VERSION 5.8 ;
BUSBITCHARS "[]" ;
DIVIDERCHAR "/" ;
UNITS
    DATABASE MICRONS 1000 ;
END UNITS

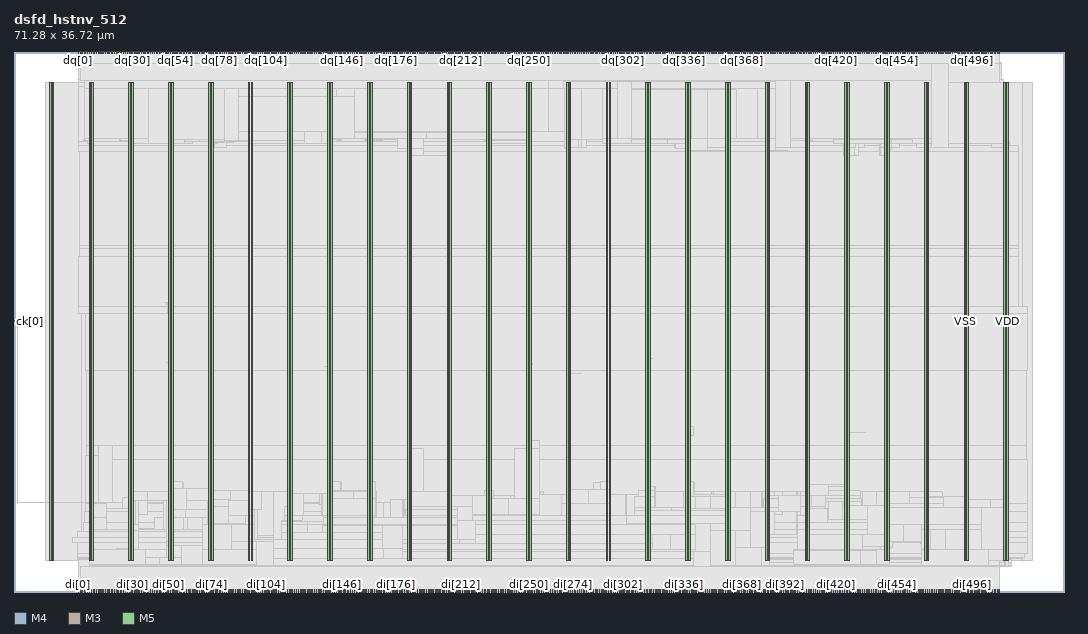
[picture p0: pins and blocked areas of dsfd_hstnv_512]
MACRO dsfd_hstnv_512
  FOREIGN dsfd_hstnv_512 0 0 ;
  CLASS BLOCK ;
  SIZE 71.28 BY 36.72 ;
  PIN ck[0]
    DIRECTION INPUT ;
    USE SIGNAL ;
    PORT
      LAYER M4 ;
        RECT  0 18.384 0.192 18.408 ;
    END
    PORT
      LAYER M4 ;
        RECT  0.156 18.384 0.275 18.408 ;
    END
  END ck[0]
  PIN di[0]
    DIRECTION INPUT ;
    USE SIGNAL ;
    PORT
      LAYER M3 ;
        RECT  4.356 0 4.374 0.144 ;
    END
  END di[0]
  PIN di[100]
    DIRECTION INPUT ;
    USE SIGNAL ;
    PORT
      LAYER M3 ;
        RECT  16.596 0 16.614 0.144 ;
    END
  END di[100]
  PIN di[101]
    DIRECTION INPUT ;
    USE SIGNAL ;
    PORT
      LAYER M5 ;
        RECT  16.704 0 16.728 0.192 ;
    END
  END di[101]
  PIN di[102]
    DIRECTION INPUT ;
    USE SIGNAL ;
    PORT
      LAYER M3 ;
        RECT  16.848 0 16.866 0.144 ;
    END
  END di[102]
  PIN di[103]
    DIRECTION INPUT ;
    USE SIGNAL ;
    PORT
      LAYER M5 ;
        RECT  16.992 0 17.016 0.192 ;
    END
  END di[103]
  PIN di[104]
    DIRECTION INPUT ;
    USE SIGNAL ;
    PORT
      LAYER M3 ;
        RECT  17.1 0 17.118 0.144 ;
    END
  END di[104]
  PIN di[105]
    DIRECTION INPUT ;
    USE SIGNAL ;
    PORT
      LAYER M5 ;
        RECT  17.232 0 17.256 0.192 ;
    END
  END di[105]
  PIN di[106]
    DIRECTION INPUT ;
    USE SIGNAL ;
    PORT
      LAYER M3 ;
        RECT  17.352 0 17.37 0.144 ;
    END
  END di[106]
  PIN di[107]
    DIRECTION INPUT ;
    USE SIGNAL ;
    PORT
      LAYER M5 ;
        RECT  17.472 0 17.496 0.192 ;
    END
  END di[107]
  PIN di[108]
    DIRECTION INPUT ;
    USE SIGNAL ;
    PORT
      LAYER M3 ;
        RECT  17.568 0 17.586 0.144 ;
    END
  END di[108]
  PIN di[109]
    DIRECTION INPUT ;
    USE SIGNAL ;
    PORT
      LAYER M5 ;
        RECT  17.712 0 17.736 0.192 ;
    END
  END di[109]
  PIN di[10]
    DIRECTION INPUT ;
    USE SIGNAL ;
    PORT
      LAYER M3 ;
        RECT  5.58 0 5.598 0.144 ;
    END
  END di[10]
  PIN di[110]
    DIRECTION INPUT ;
    USE SIGNAL ;
    PORT
      LAYER M3 ;
        RECT  17.82 0 17.838 0.144 ;
    END
  END di[110]
  PIN di[111]
    DIRECTION INPUT ;
    USE SIGNAL ;
    PORT
      LAYER M5 ;
        RECT  17.952 0 17.976 0.192 ;
    END
  END di[111]
  PIN di[112]
    DIRECTION INPUT ;
    USE SIGNAL ;
    PORT
      LAYER M3 ;
        RECT  18.072 0 18.09 0.144 ;
    END
  END di[112]
  PIN di[113]
    DIRECTION INPUT ;
    USE SIGNAL ;
    PORT
      LAYER M5 ;
        RECT  18.192 0 18.216 0.192 ;
    END
  END di[113]
  PIN di[114]
    DIRECTION INPUT ;
    USE SIGNAL ;
    PORT
      LAYER M3 ;
        RECT  18.324 0 18.342 0.144 ;
    END
  END di[114]
  PIN di[115]
    DIRECTION INPUT ;
    USE SIGNAL ;
    PORT
      LAYER M5 ;
        RECT  18.432 0 18.456 0.192 ;
    END
  END di[115]
  PIN di[116]
    DIRECTION INPUT ;
    USE SIGNAL ;
    PORT
      LAYER M3 ;
        RECT  18.576 0 18.594 0.144 ;
    END
  END di[116]
  PIN di[117]
    DIRECTION INPUT ;
    USE SIGNAL ;
    PORT
      LAYER M5 ;
        RECT  18.672 0 18.696 0.192 ;
    END
  END di[117]
  PIN di[118]
    DIRECTION INPUT ;
    USE SIGNAL ;
    PORT
      LAYER M3 ;
        RECT  18.792 0 18.81 0.144 ;
    END
  END di[118]
  PIN di[119]
    DIRECTION INPUT ;
    USE SIGNAL ;
    PORT
      LAYER M5 ;
        RECT  18.912 0 18.936 0.192 ;
    END
  END di[119]
  PIN di[11]
    DIRECTION INPUT ;
    USE SIGNAL ;
    PORT
      LAYER M5 ;
        RECT  5.712 0 5.736 0.192 ;
    END
  END di[11]
  PIN di[120]
    DIRECTION INPUT ;
    USE SIGNAL ;
    PORT
      LAYER M3 ;
        RECT  19.044 0 19.062 0.144 ;
    END
  END di[120]
  PIN di[121]
    DIRECTION INPUT ;
    USE SIGNAL ;
    PORT
      LAYER M5 ;
        RECT  19.152 0 19.176 0.192 ;
    END
  END di[121]
  PIN di[122]
    DIRECTION INPUT ;
    USE SIGNAL ;
    PORT
      LAYER M3 ;
        RECT  19.296 0 19.314 0.144 ;
    END
  END di[122]
  PIN di[123]
    DIRECTION INPUT ;
    USE SIGNAL ;
    PORT
      LAYER M5 ;
        RECT  19.44 0 19.464 0.192 ;
    END
  END di[123]
  PIN di[124]
    DIRECTION INPUT ;
    USE SIGNAL ;
    PORT
      LAYER M3 ;
        RECT  19.548 0 19.566 0.144 ;
    END
  END di[124]
  PIN di[125]
    DIRECTION INPUT ;
    USE SIGNAL ;
    PORT
      LAYER M5 ;
        RECT  19.68 0 19.704 0.192 ;
    END
  END di[125]
  PIN di[126]
    DIRECTION INPUT ;
    USE SIGNAL ;
    PORT
      LAYER M3 ;
        RECT  19.8 0 19.818 0.144 ;
    END
  END di[126]
  PIN di[127]
    DIRECTION INPUT ;
    USE SIGNAL ;
    PORT
      LAYER M5 ;
        RECT  19.92 0 19.944 0.192 ;
    END
  END di[127]
  PIN di[128]
    DIRECTION INPUT ;
    USE SIGNAL ;
    PORT
      LAYER M3 ;
        RECT  20.016 0 20.034 0.144 ;
    END
  END di[128]
  PIN di[129]
    DIRECTION INPUT ;
    USE SIGNAL ;
    PORT
      LAYER M5 ;
        RECT  20.16 0 20.184 0.192 ;
    END
  END di[129]
  PIN di[12]
    DIRECTION INPUT ;
    USE SIGNAL ;
    PORT
      LAYER M3 ;
        RECT  5.832 0 5.85 0.144 ;
    END
  END di[12]
  PIN di[130]
    DIRECTION INPUT ;
    USE SIGNAL ;
    PORT
      LAYER M3 ;
        RECT  20.268 0 20.286 0.144 ;
    END
  END di[130]
  PIN di[131]
    DIRECTION INPUT ;
    USE SIGNAL ;
    PORT
      LAYER M5 ;
        RECT  20.4 0 20.424 0.192 ;
    END
  END di[131]
  PIN di[132]
    DIRECTION INPUT ;
    USE SIGNAL ;
    PORT
      LAYER M3 ;
        RECT  20.52 0 20.538 0.144 ;
    END
  END di[132]
  PIN di[133]
    DIRECTION INPUT ;
    USE SIGNAL ;
    PORT
      LAYER M5 ;
        RECT  20.64 0 20.664 0.192 ;
    END
  END di[133]
  PIN di[134]
    DIRECTION INPUT ;
    USE SIGNAL ;
    PORT
      LAYER M3 ;
        RECT  20.772 0 20.79 0.144 ;
    END
  END di[134]
  PIN di[135]
    DIRECTION INPUT ;
    USE SIGNAL ;
    PORT
      LAYER M5 ;
        RECT  20.88 0 20.904 0.192 ;
    END
  END di[135]
  PIN di[136]
    DIRECTION INPUT ;
    USE SIGNAL ;
    PORT
      LAYER M3 ;
        RECT  21.024 0 21.042 0.144 ;
    END
  END di[136]
  PIN di[137]
    DIRECTION INPUT ;
    USE SIGNAL ;
    PORT
      LAYER M5 ;
        RECT  21.12 0 21.144 0.192 ;
    END
  END di[137]
  PIN di[138]
    DIRECTION INPUT ;
    USE SIGNAL ;
    PORT
      LAYER M3 ;
        RECT  21.24 0 21.258 0.144 ;
    END
  END di[138]
  PIN di[139]
    DIRECTION INPUT ;
    USE SIGNAL ;
    PORT
      LAYER M5 ;
        RECT  21.36 0 21.384 0.192 ;
    END
  END di[139]
  PIN di[13]
    DIRECTION INPUT ;
    USE SIGNAL ;
    PORT
      LAYER M5 ;
        RECT  5.952 0 5.976 0.192 ;
    END
  END di[13]
  PIN di[140]
    DIRECTION INPUT ;
    USE SIGNAL ;
    PORT
      LAYER M3 ;
        RECT  21.492 0 21.51 0.144 ;
    END
  END di[140]
  PIN di[141]
    DIRECTION INPUT ;
    USE SIGNAL ;
    PORT
      LAYER M5 ;
        RECT  21.6 0 21.624 0.192 ;
    END
  END di[141]
  PIN di[142]
    DIRECTION INPUT ;
    USE SIGNAL ;
    PORT
      LAYER M3 ;
        RECT  21.744 0 21.762 0.144 ;
    END
  END di[142]
  PIN di[143]
    DIRECTION INPUT ;
    USE SIGNAL ;
    PORT
      LAYER M5 ;
        RECT  21.888 0 21.912 0.192 ;
    END
  END di[143]
  PIN di[144]
    DIRECTION INPUT ;
    USE SIGNAL ;
    PORT
      LAYER M3 ;
        RECT  21.996 0 22.014 0.144 ;
    END
  END di[144]
  PIN di[145]
    DIRECTION INPUT ;
    USE SIGNAL ;
    PORT
      LAYER M5 ;
        RECT  22.128 0 22.152 0.192 ;
    END
  END di[145]
  PIN di[146]
    DIRECTION INPUT ;
    USE SIGNAL ;
    PORT
      LAYER M3 ;
        RECT  22.248 0 22.266 0.144 ;
    END
  END di[146]
  PIN di[147]
    DIRECTION INPUT ;
    USE SIGNAL ;
    PORT
      LAYER M5 ;
        RECT  22.368 0 22.392 0.192 ;
    END
  END di[147]
  PIN di[148]
    DIRECTION INPUT ;
    USE SIGNAL ;
    PORT
      LAYER M3 ;
        RECT  22.464 0 22.482 0.144 ;
    END
  END di[148]
  PIN di[149]
    DIRECTION INPUT ;
    USE SIGNAL ;
    PORT
      LAYER M5 ;
        RECT  22.608 0 22.632 0.192 ;
    END
  END di[149]
  PIN di[14]
    DIRECTION INPUT ;
    USE SIGNAL ;
    PORT
      LAYER M3 ;
        RECT  6.084 0 6.102 0.144 ;
    END
  END di[14]
  PIN di[150]
    DIRECTION INPUT ;
    USE SIGNAL ;
    PORT
      LAYER M3 ;
        RECT  22.716 0 22.734 0.144 ;
    END
  END di[150]
  PIN di[151]
    DIRECTION INPUT ;
    USE SIGNAL ;
    PORT
      LAYER M5 ;
        RECT  22.848 0 22.872 0.192 ;
    END
  END di[151]
  PIN di[152]
    DIRECTION INPUT ;
    USE SIGNAL ;
    PORT
      LAYER M3 ;
        RECT  22.968 0 22.986 0.144 ;
    END
  END di[152]
  PIN di[153]
    DIRECTION INPUT ;
    USE SIGNAL ;
    PORT
      LAYER M5 ;
        RECT  23.088 0 23.112 0.192 ;
    END
  END di[153]
  PIN di[154]
    DIRECTION INPUT ;
    USE SIGNAL ;
    PORT
      LAYER M3 ;
        RECT  23.22 0 23.238 0.144 ;
    END
  END di[154]
  PIN di[155]
    DIRECTION INPUT ;
    USE SIGNAL ;
    PORT
      LAYER M5 ;
        RECT  23.328 0 23.352 0.192 ;
    END
  END di[155]
  PIN di[156]
    DIRECTION INPUT ;
    USE SIGNAL ;
    PORT
      LAYER M3 ;
        RECT  23.472 0 23.49 0.144 ;
    END
  END di[156]
  PIN di[157]
    DIRECTION INPUT ;
    USE SIGNAL ;
    PORT
      LAYER M5 ;
        RECT  23.568 0 23.592 0.192 ;
    END
  END di[157]
  PIN di[158]
    DIRECTION INPUT ;
    USE SIGNAL ;
    PORT
      LAYER M3 ;
        RECT  23.688 0 23.706 0.144 ;
    END
  END di[158]
  PIN di[159]
    DIRECTION INPUT ;
    USE SIGNAL ;
    PORT
      LAYER M5 ;
        RECT  23.808 0 23.832 0.192 ;
    END
  END di[159]
  PIN di[15]
    DIRECTION INPUT ;
    USE SIGNAL ;
    PORT
      LAYER M5 ;
        RECT  6.192 0 6.216 0.192 ;
    END
  END di[15]
  PIN di[160]
    DIRECTION INPUT ;
    USE SIGNAL ;
    PORT
      LAYER M3 ;
        RECT  23.94 0 23.958 0.144 ;
    END
  END di[160]
  PIN di[161]
    DIRECTION INPUT ;
    USE SIGNAL ;
    PORT
      LAYER M5 ;
        RECT  24.048 0 24.072 0.192 ;
    END
  END di[161]
  PIN di[162]
    DIRECTION INPUT ;
    USE SIGNAL ;
    PORT
      LAYER M3 ;
        RECT  24.192 0 24.21 0.144 ;
    END
  END di[162]
  PIN di[163]
    DIRECTION INPUT ;
    USE SIGNAL ;
    PORT
      LAYER M5 ;
        RECT  24.288 0 24.312 0.192 ;
    END
  END di[163]
  PIN di[164]
    DIRECTION INPUT ;
    USE SIGNAL ;
    PORT
      LAYER M3 ;
        RECT  24.444 0 24.462 0.144 ;
    END
  END di[164]
  PIN di[165]
    DIRECTION INPUT ;
    USE SIGNAL ;
    PORT
      LAYER M5 ;
        RECT  24.576 0 24.6 0.192 ;
    END
  END di[165]
  PIN di[166]
    DIRECTION INPUT ;
    USE SIGNAL ;
    PORT
      LAYER M3 ;
        RECT  24.696 0 24.714 0.144 ;
    END
  END di[166]
  PIN di[167]
    DIRECTION INPUT ;
    USE SIGNAL ;
    PORT
      LAYER M5 ;
        RECT  24.816 0 24.84 0.192 ;
    END
  END di[167]
  PIN di[168]
    DIRECTION INPUT ;
    USE SIGNAL ;
    PORT
      LAYER M3 ;
        RECT  24.912 0 24.93 0.144 ;
    END
  END di[168]
  PIN di[169]
    DIRECTION INPUT ;
    USE SIGNAL ;
    PORT
      LAYER M5 ;
        RECT  25.056 0 25.08 0.192 ;
    END
  END di[169]
  PIN di[16]
    DIRECTION INPUT ;
    USE SIGNAL ;
    PORT
      LAYER M3 ;
        RECT  6.336 0 6.354 0.144 ;
    END
  END di[16]
  PIN di[170]
    DIRECTION INPUT ;
    USE SIGNAL ;
    PORT
      LAYER M3 ;
        RECT  25.164 0 25.182 0.144 ;
    END
  END di[170]
  PIN di[171]
    DIRECTION INPUT ;
    USE SIGNAL ;
    PORT
      LAYER M5 ;
        RECT  25.296 0 25.32 0.192 ;
    END
  END di[171]
  PIN di[172]
    DIRECTION INPUT ;
    USE SIGNAL ;
    PORT
      LAYER M3 ;
        RECT  25.416 0 25.434 0.144 ;
    END
  END di[172]
  PIN di[173]
    DIRECTION INPUT ;
    USE SIGNAL ;
    PORT
      LAYER M5 ;
        RECT  25.536 0 25.56 0.192 ;
    END
  END di[173]
  PIN di[174]
    DIRECTION INPUT ;
    USE SIGNAL ;
    PORT
      LAYER M3 ;
        RECT  25.668 0 25.686 0.144 ;
    END
  END di[174]
  PIN di[175]
    DIRECTION INPUT ;
    USE SIGNAL ;
    PORT
      LAYER M5 ;
        RECT  25.776 0 25.8 0.192 ;
    END
  END di[175]
  PIN di[176]
    DIRECTION INPUT ;
    USE SIGNAL ;
    PORT
      LAYER M3 ;
        RECT  25.92 0 25.938 0.144 ;
    END
  END di[176]
  PIN di[177]
    DIRECTION INPUT ;
    USE SIGNAL ;
    PORT
      LAYER M5 ;
        RECT  26.016 0 26.04 0.192 ;
    END
  END di[177]
  PIN di[178]
    DIRECTION INPUT ;
    USE SIGNAL ;
    PORT
      LAYER M3 ;
        RECT  26.136 0 26.154 0.144 ;
    END
  END di[178]
  PIN di[179]
    DIRECTION INPUT ;
    USE SIGNAL ;
    PORT
      LAYER M5 ;
        RECT  26.256 0 26.28 0.192 ;
    END
  END di[179]
  PIN di[17]
    DIRECTION INPUT ;
    USE SIGNAL ;
    PORT
      LAYER M5 ;
        RECT  6.432 0 6.456 0.192 ;
    END
  END di[17]
  PIN di[180]
    DIRECTION INPUT ;
    USE SIGNAL ;
    PORT
      LAYER M3 ;
        RECT  26.388 0 26.406 0.144 ;
    END
  END di[180]
  PIN di[181]
    DIRECTION INPUT ;
    USE SIGNAL ;
    PORT
      LAYER M5 ;
        RECT  26.496 0 26.52 0.192 ;
    END
  END di[181]
  PIN di[182]
    DIRECTION INPUT ;
    USE SIGNAL ;
    PORT
      LAYER M3 ;
        RECT  26.64 0 26.658 0.144 ;
    END
  END di[182]
  PIN di[183]
    DIRECTION INPUT ;
    USE SIGNAL ;
    PORT
      LAYER M5 ;
        RECT  26.736 0 26.76 0.192 ;
    END
  END di[183]
  PIN di[184]
    DIRECTION INPUT ;
    USE SIGNAL ;
    PORT
      LAYER M3 ;
        RECT  26.892 0 26.91 0.144 ;
    END
  END di[184]
  PIN di[185]
    DIRECTION INPUT ;
    USE SIGNAL ;
    PORT
      LAYER M5 ;
        RECT  27.024 0 27.048 0.192 ;
    END
  END di[185]
  PIN di[186]
    DIRECTION INPUT ;
    USE SIGNAL ;
    PORT
      LAYER M3 ;
        RECT  27.144 0 27.162 0.144 ;
    END
  END di[186]
  PIN di[187]
    DIRECTION INPUT ;
    USE SIGNAL ;
    PORT
      LAYER M5 ;
        RECT  27.264 0 27.288 0.192 ;
    END
  END di[187]
  PIN di[188]
    DIRECTION INPUT ;
    USE SIGNAL ;
    PORT
      LAYER M3 ;
        RECT  27.36 0 27.378 0.144 ;
    END
  END di[188]
  PIN di[189]
    DIRECTION INPUT ;
    USE SIGNAL ;
    PORT
      LAYER M5 ;
        RECT  27.504 0 27.528 0.192 ;
    END
  END di[189]
  PIN di[18]
    DIRECTION INPUT ;
    USE SIGNAL ;
    PORT
      LAYER M3 ;
        RECT  6.588 0 6.606 0.144 ;
    END
  END di[18]
  PIN di[190]
    DIRECTION INPUT ;
    USE SIGNAL ;
    PORT
      LAYER M3 ;
        RECT  27.612 0 27.63 0.144 ;
    END
  END di[190]
  PIN di[191]
    DIRECTION INPUT ;
    USE SIGNAL ;
    PORT
      LAYER M5 ;
        RECT  27.744 0 27.768 0.192 ;
    END
  END di[191]
  PIN di[192]
    DIRECTION INPUT ;
    USE SIGNAL ;
    PORT
      LAYER M3 ;
        RECT  27.864 0 27.882 0.144 ;
    END
  END di[192]
  PIN di[193]
    DIRECTION INPUT ;
    USE SIGNAL ;
    PORT
      LAYER M5 ;
        RECT  27.984 0 28.008 0.192 ;
    END
  END di[193]
  PIN di[194]
    DIRECTION INPUT ;
    USE SIGNAL ;
    PORT
      LAYER M3 ;
        RECT  28.116 0 28.134 0.144 ;
    END
  END di[194]
  PIN di[195]
    DIRECTION INPUT ;
    USE SIGNAL ;
    PORT
      LAYER M5 ;
        RECT  28.224 0 28.248 0.192 ;
    END
  END di[195]
  PIN di[196]
    DIRECTION INPUT ;
    USE SIGNAL ;
    PORT
      LAYER M3 ;
        RECT  28.368 0 28.386 0.144 ;
    END
  END di[196]
  PIN di[197]
    DIRECTION INPUT ;
    USE SIGNAL ;
    PORT
      LAYER M5 ;
        RECT  28.464 0 28.488 0.192 ;
    END
  END di[197]
  PIN di[198]
    DIRECTION INPUT ;
    USE SIGNAL ;
    PORT
      LAYER M3 ;
        RECT  28.584 0 28.602 0.144 ;
    END
  END di[198]
  PIN di[199]
    DIRECTION INPUT ;
    USE SIGNAL ;
    PORT
      LAYER M5 ;
        RECT  28.704 0 28.728 0.192 ;
    END
  END di[199]
  PIN di[19]
    DIRECTION INPUT ;
    USE SIGNAL ;
    PORT
      LAYER M5 ;
        RECT  6.672 0 6.696 0.192 ;
    END
  END di[19]
  PIN di[1]
    DIRECTION INPUT ;
    USE SIGNAL ;
    PORT
      LAYER M5 ;
        RECT  4.512 0 4.536 0.192 ;
    END
  END di[1]
  PIN di[200]
    DIRECTION INPUT ;
    USE SIGNAL ;
    PORT
      LAYER M3 ;
        RECT  28.836 0 28.854 0.144 ;
    END
  END di[200]
  PIN di[201]
    DIRECTION INPUT ;
    USE SIGNAL ;
    PORT
      LAYER M5 ;
        RECT  28.944 0 28.968 0.192 ;
    END
  END di[201]
  PIN di[202]
    DIRECTION INPUT ;
    USE SIGNAL ;
    PORT
      LAYER M3 ;
        RECT  29.088 0 29.106 0.144 ;
    END
  END di[202]
  PIN di[203]
    DIRECTION INPUT ;
    USE SIGNAL ;
    PORT
      LAYER M5 ;
        RECT  29.184 0 29.208 0.192 ;
    END
  END di[203]
  PIN di[204]
    DIRECTION INPUT ;
    USE SIGNAL ;
    PORT
      LAYER M3 ;
        RECT  29.34 0 29.358 0.144 ;
    END
  END di[204]
  PIN di[205]
    DIRECTION INPUT ;
    USE SIGNAL ;
    PORT
      LAYER M5 ;
        RECT  29.472 0 29.496 0.192 ;
    END
  END di[205]
  PIN di[206]
    DIRECTION INPUT ;
    USE SIGNAL ;
    PORT
      LAYER M3 ;
        RECT  29.592 0 29.61 0.144 ;
    END
  END di[206]
  PIN di[207]
    DIRECTION INPUT ;
    USE SIGNAL ;
    PORT
      LAYER M5 ;
        RECT  29.712 0 29.736 0.192 ;
    END
  END di[207]
  PIN di[208]
    DIRECTION INPUT ;
    USE SIGNAL ;
    PORT
      LAYER M3 ;
        RECT  29.808 0 29.826 0.144 ;
    END
  END di[208]
  PIN di[209]
    DIRECTION INPUT ;
    USE SIGNAL ;
    PORT
      LAYER M5 ;
        RECT  29.952 0 29.976 0.192 ;
    END
  END di[209]
  PIN di[20]
    DIRECTION INPUT ;
    USE SIGNAL ;
    PORT
      LAYER M3 ;
        RECT  6.804 0 6.822 0.144 ;
    END
  END di[20]
  PIN di[210]
    DIRECTION INPUT ;
    USE SIGNAL ;
    PORT
      LAYER M3 ;
        RECT  30.06 0 30.078 0.144 ;
    END
  END di[210]
  PIN di[211]
    DIRECTION INPUT ;
    USE SIGNAL ;
    PORT
      LAYER M5 ;
        RECT  30.192 0 30.216 0.192 ;
    END
  END di[211]
  PIN di[212]
    DIRECTION INPUT ;
    USE SIGNAL ;
    PORT
      LAYER M3 ;
        RECT  30.312 0 30.33 0.144 ;
    END
  END di[212]
  PIN di[213]
    DIRECTION INPUT ;
    USE SIGNAL ;
    PORT
      LAYER M5 ;
        RECT  30.432 0 30.456 0.192 ;
    END
  END di[213]
  PIN di[214]
    DIRECTION INPUT ;
    USE SIGNAL ;
    PORT
      LAYER M3 ;
        RECT  30.564 0 30.582 0.144 ;
    END
  END di[214]
  PIN di[215]
    DIRECTION INPUT ;
    USE SIGNAL ;
    PORT
      LAYER M5 ;
        RECT  30.672 0 30.696 0.192 ;
    END
  END di[215]
  PIN di[216]
    DIRECTION INPUT ;
    USE SIGNAL ;
    PORT
      LAYER M3 ;
        RECT  30.816 0 30.834 0.144 ;
    END
  END di[216]
  PIN di[217]
    DIRECTION INPUT ;
    USE SIGNAL ;
    PORT
      LAYER M5 ;
        RECT  30.912 0 30.936 0.192 ;
    END
  END di[217]
  PIN di[218]
    DIRECTION INPUT ;
    USE SIGNAL ;
    PORT
      LAYER M3 ;
        RECT  31.032 0 31.05 0.144 ;
    END
  END di[218]
  PIN di[219]
    DIRECTION INPUT ;
    USE SIGNAL ;
    PORT
      LAYER M5 ;
        RECT  31.152 0 31.176 0.192 ;
    END
  END di[219]
  PIN di[21]
    DIRECTION INPUT ;
    USE SIGNAL ;
    PORT
      LAYER M5 ;
        RECT  6.96 0 6.984 0.192 ;
    END
  END di[21]
  PIN di[220]
    DIRECTION INPUT ;
    USE SIGNAL ;
    PORT
      LAYER M3 ;
        RECT  31.284 0 31.302 0.144 ;
    END
  END di[220]
  PIN di[221]
    DIRECTION INPUT ;
    USE SIGNAL ;
    PORT
      LAYER M5 ;
        RECT  31.392 0 31.416 0.192 ;
    END
  END di[221]
  PIN di[222]
    DIRECTION INPUT ;
    USE SIGNAL ;
    PORT
      LAYER M3 ;
        RECT  31.536 0 31.554 0.144 ;
    END
  END di[222]
  PIN di[223]
    DIRECTION INPUT ;
    USE SIGNAL ;
    PORT
      LAYER M5 ;
        RECT  31.632 0 31.656 0.192 ;
    END
  END di[223]
  PIN di[224]
    DIRECTION INPUT ;
    USE SIGNAL ;
    PORT
      LAYER M3 ;
        RECT  31.788 0 31.806 0.144 ;
    END
  END di[224]
  PIN di[225]
    DIRECTION INPUT ;
    USE SIGNAL ;
    PORT
      LAYER M5 ;
        RECT  31.92 0 31.944 0.192 ;
    END
  END di[225]
  PIN di[226]
    DIRECTION INPUT ;
    USE SIGNAL ;
    PORT
      LAYER M3 ;
        RECT  32.004 0 32.022 0.144 ;
    END
  END di[226]
  PIN di[227]
    DIRECTION INPUT ;
    USE SIGNAL ;
    PORT
      LAYER M5 ;
        RECT  32.16 0 32.184 0.192 ;
    END
  END di[227]
  PIN di[228]
    DIRECTION INPUT ;
    USE SIGNAL ;
    PORT
      LAYER M3 ;
        RECT  32.256 0 32.274 0.144 ;
    END
  END di[228]
  PIN di[229]
    DIRECTION INPUT ;
    USE SIGNAL ;
    PORT
      LAYER M5 ;
        RECT  32.4 0 32.424 0.192 ;
    END
  END di[229]
  PIN di[22]
    DIRECTION INPUT ;
    USE SIGNAL ;
    PORT
      LAYER M3 ;
        RECT  7.056 0 7.074 0.144 ;
    END
  END di[22]
  PIN di[230]
    DIRECTION INPUT ;
    USE SIGNAL ;
    PORT
      LAYER M3 ;
        RECT  32.508 0 32.526 0.144 ;
    END
  END di[230]
  PIN di[231]
    DIRECTION INPUT ;
    USE SIGNAL ;
    PORT
      LAYER M5 ;
        RECT  32.64 0 32.664 0.192 ;
    END
  END di[231]
  PIN di[232]
    DIRECTION INPUT ;
    USE SIGNAL ;
    PORT
      LAYER M3 ;
        RECT  32.76 0 32.778 0.144 ;
    END
  END di[232]
  PIN di[233]
    DIRECTION INPUT ;
    USE SIGNAL ;
    PORT
      LAYER M5 ;
        RECT  32.88 0 32.904 0.192 ;
    END
  END di[233]
  PIN di[234]
    DIRECTION INPUT ;
    USE SIGNAL ;
    PORT
      LAYER M3 ;
        RECT  33.012 0 33.03 0.144 ;
    END
  END di[234]
  PIN di[235]
    DIRECTION INPUT ;
    USE SIGNAL ;
    PORT
      LAYER M5 ;
        RECT  33.12 0 33.144 0.192 ;
    END
  END di[235]
  PIN di[236]
    DIRECTION INPUT ;
    USE SIGNAL ;
    PORT
      LAYER M3 ;
        RECT  33.228 0 33.246 0.144 ;
    END
  END di[236]
  PIN di[237]
    DIRECTION INPUT ;
    USE SIGNAL ;
    PORT
      LAYER M5 ;
        RECT  33.36 0 33.384 0.192 ;
    END
  END di[237]
  PIN di[238]
    DIRECTION INPUT ;
    USE SIGNAL ;
    PORT
      LAYER M3 ;
        RECT  33.48 0 33.498 0.144 ;
    END
  END di[238]
  PIN di[239]
    DIRECTION INPUT ;
    USE SIGNAL ;
    PORT
      LAYER M5 ;
        RECT  33.6 0 33.624 0.192 ;
    END
  END di[239]
  PIN di[23]
    DIRECTION INPUT ;
    USE SIGNAL ;
    PORT
      LAYER M5 ;
        RECT  7.2 0 7.224 0.192 ;
    END
  END di[23]
  PIN di[240]
    DIRECTION INPUT ;
    USE SIGNAL ;
    PORT
      LAYER M3 ;
        RECT  33.732 0 33.75 0.144 ;
    END
  END di[240]
  PIN di[241]
    DIRECTION INPUT ;
    USE SIGNAL ;
    PORT
      LAYER M5 ;
        RECT  33.84 0 33.864 0.192 ;
    END
  END di[241]
  PIN di[242]
    DIRECTION INPUT ;
    USE SIGNAL ;
    PORT
      LAYER M3 ;
        RECT  33.984 0 34.002 0.144 ;
    END
  END di[242]
  PIN di[243]
    DIRECTION INPUT ;
    USE SIGNAL ;
    PORT
      LAYER M5 ;
        RECT  34.08 0 34.104 0.192 ;
    END
  END di[243]
  PIN di[244]
    DIRECTION INPUT ;
    USE SIGNAL ;
    PORT
      LAYER M3 ;
        RECT  34.236 0 34.254 0.144 ;
    END
  END di[244]
  PIN di[245]
    DIRECTION INPUT ;
    USE SIGNAL ;
    PORT
      LAYER M5 ;
        RECT  34.32 0 34.344 0.192 ;
    END
  END di[245]
  PIN di[246]
    DIRECTION INPUT ;
    USE SIGNAL ;
    PORT
      LAYER M3 ;
        RECT  34.452 0 34.47 0.144 ;
    END
  END di[246]
  PIN di[247]
    DIRECTION INPUT ;
    USE SIGNAL ;
    PORT
      LAYER M5 ;
        RECT  34.608 0 34.632 0.192 ;
    END
  END di[247]
  PIN di[248]
    DIRECTION INPUT ;
    USE SIGNAL ;
    PORT
      LAYER M3 ;
        RECT  34.704 0 34.722 0.144 ;
    END
  END di[248]
  PIN di[249]
    DIRECTION INPUT ;
    USE SIGNAL ;
    PORT
      LAYER M5 ;
        RECT  34.848 0 34.872 0.192 ;
    END
  END di[249]
  PIN di[24]
    DIRECTION INPUT ;
    USE SIGNAL ;
    PORT
      LAYER M3 ;
        RECT  7.308 0 7.326 0.144 ;
    END
  END di[24]
  PIN di[250]
    DIRECTION INPUT ;
    USE SIGNAL ;
    PORT
      LAYER M3 ;
        RECT  34.956 0 34.974 0.144 ;
    END
  END di[250]
  PIN di[251]
    DIRECTION INPUT ;
    USE SIGNAL ;
    PORT
      LAYER M5 ;
        RECT  35.088 0 35.112 0.192 ;
    END
  END di[251]
  PIN di[252]
    DIRECTION INPUT ;
    USE SIGNAL ;
    PORT
      LAYER M3 ;
        RECT  35.208 0 35.226 0.144 ;
    END
  END di[252]
  PIN di[253]
    DIRECTION INPUT ;
    USE SIGNAL ;
    PORT
      LAYER M5 ;
        RECT  35.328 0 35.352 0.192 ;
    END
  END di[253]
  PIN di[254]
    DIRECTION INPUT ;
    USE SIGNAL ;
    PORT
      LAYER M3 ;
        RECT  35.46 0 35.478 0.144 ;
    END
  END di[254]
  PIN di[255]
    DIRECTION INPUT ;
    USE SIGNAL ;
    PORT
      LAYER M5 ;
        RECT  35.568 0 35.592 0.192 ;
    END
  END di[255]
  PIN di[256]
    DIRECTION INPUT ;
    USE SIGNAL ;
    PORT
      LAYER M3 ;
        RECT  35.676 0 35.694 0.144 ;
    END
  END di[256]
  PIN di[257]
    DIRECTION INPUT ;
    USE SIGNAL ;
    PORT
      LAYER M5 ;
        RECT  35.808 0 35.832 0.192 ;
    END
  END di[257]
  PIN di[258]
    DIRECTION INPUT ;
    USE SIGNAL ;
    PORT
      LAYER M3 ;
        RECT  35.928 0 35.946 0.144 ;
    END
  END di[258]
  PIN di[259]
    DIRECTION INPUT ;
    USE SIGNAL ;
    PORT
      LAYER M5 ;
        RECT  36.048 0 36.072 0.192 ;
    END
  END di[259]
  PIN di[25]
    DIRECTION INPUT ;
    USE SIGNAL ;
    PORT
      LAYER M5 ;
        RECT  7.44 0 7.464 0.192 ;
    END
  END di[25]
  PIN di[260]
    DIRECTION INPUT ;
    USE SIGNAL ;
    PORT
      LAYER M3 ;
        RECT  36.18 0 36.198 0.144 ;
    END
  END di[260]
  PIN di[261]
    DIRECTION INPUT ;
    USE SIGNAL ;
    PORT
      LAYER M5 ;
        RECT  36.288 0 36.312 0.192 ;
    END
  END di[261]
  PIN di[262]
    DIRECTION INPUT ;
    USE SIGNAL ;
    PORT
      LAYER M3 ;
        RECT  36.432 0 36.45 0.144 ;
    END
  END di[262]
  PIN di[263]
    DIRECTION INPUT ;
    USE SIGNAL ;
    PORT
      LAYER M5 ;
        RECT  36.528 0 36.552 0.192 ;
    END
  END di[263]
  PIN di[264]
    DIRECTION INPUT ;
    USE SIGNAL ;
    PORT
      LAYER M3 ;
        RECT  36.684 0 36.702 0.144 ;
    END
  END di[264]
  PIN di[265]
    DIRECTION INPUT ;
    USE SIGNAL ;
    PORT
      LAYER M5 ;
        RECT  36.768 0 36.792 0.192 ;
    END
  END di[265]
  PIN di[266]
    DIRECTION INPUT ;
    USE SIGNAL ;
    PORT
      LAYER M3 ;
        RECT  36.9 0 36.918 0.144 ;
    END
  END di[266]
  PIN di[267]
    DIRECTION INPUT ;
    USE SIGNAL ;
    PORT
      LAYER M5 ;
        RECT  37.056 0 37.08 0.192 ;
    END
  END di[267]
  PIN di[268]
    DIRECTION INPUT ;
    USE SIGNAL ;
    PORT
      LAYER M3 ;
        RECT  37.152 0 37.17 0.144 ;
    END
  END di[268]
  PIN di[269]
    DIRECTION INPUT ;
    USE SIGNAL ;
    PORT
      LAYER M5 ;
        RECT  37.296 0 37.32 0.192 ;
    END
  END di[269]
  PIN di[26]
    DIRECTION INPUT ;
    USE SIGNAL ;
    PORT
      LAYER M3 ;
        RECT  7.56 0 7.578 0.144 ;
    END
  END di[26]
  PIN di[270]
    DIRECTION INPUT ;
    USE SIGNAL ;
    PORT
      LAYER M3 ;
        RECT  37.404 0 37.422 0.144 ;
    END
  END di[270]
  PIN di[271]
    DIRECTION INPUT ;
    USE SIGNAL ;
    PORT
      LAYER M5 ;
        RECT  37.536 0 37.56 0.192 ;
    END
  END di[271]
  PIN di[272]
    DIRECTION INPUT ;
    USE SIGNAL ;
    PORT
      LAYER M3 ;
        RECT  37.656 0 37.674 0.144 ;
    END
  END di[272]
  PIN di[273]
    DIRECTION INPUT ;
    USE SIGNAL ;
    PORT
      LAYER M5 ;
        RECT  37.776 0 37.8 0.192 ;
    END
  END di[273]
  PIN di[274]
    DIRECTION INPUT ;
    USE SIGNAL ;
    PORT
      LAYER M3 ;
        RECT  37.908 0 37.926 0.144 ;
    END
  END di[274]
  PIN di[275]
    DIRECTION INPUT ;
    USE SIGNAL ;
    PORT
      LAYER M5 ;
        RECT  38.016 0 38.04 0.192 ;
    END
  END di[275]
  PIN di[276]
    DIRECTION INPUT ;
    USE SIGNAL ;
    PORT
      LAYER M3 ;
        RECT  38.124 0 38.142 0.144 ;
    END
  END di[276]
  PIN di[277]
    DIRECTION INPUT ;
    USE SIGNAL ;
    PORT
      LAYER M5 ;
        RECT  38.256 0 38.28 0.192 ;
    END
  END di[277]
  PIN di[278]
    DIRECTION INPUT ;
    USE SIGNAL ;
    PORT
      LAYER M3 ;
        RECT  38.376 0 38.394 0.144 ;
    END
  END di[278]
  PIN di[279]
    DIRECTION INPUT ;
    USE SIGNAL ;
    PORT
      LAYER M5 ;
        RECT  38.496 0 38.52 0.192 ;
    END
  END di[279]
  PIN di[27]
    DIRECTION INPUT ;
    USE SIGNAL ;
    PORT
      LAYER M5 ;
        RECT  7.68 0 7.704 0.192 ;
    END
  END di[27]
  PIN di[280]
    DIRECTION INPUT ;
    USE SIGNAL ;
    PORT
      LAYER M3 ;
        RECT  38.628 0 38.646 0.144 ;
    END
  END di[280]
  PIN di[281]
    DIRECTION INPUT ;
    USE SIGNAL ;
    PORT
      LAYER M5 ;
        RECT  38.736 0 38.76 0.192 ;
    END
  END di[281]
  PIN di[282]
    DIRECTION INPUT ;
    USE SIGNAL ;
    PORT
      LAYER M3 ;
        RECT  38.88 0 38.898 0.144 ;
    END
  END di[282]
  PIN di[283]
    DIRECTION INPUT ;
    USE SIGNAL ;
    PORT
      LAYER M5 ;
        RECT  38.976 0 39 0.192 ;
    END
  END di[283]
  PIN di[284]
    DIRECTION INPUT ;
    USE SIGNAL ;
    PORT
      LAYER M3 ;
        RECT  39.132 0 39.15 0.144 ;
    END
  END di[284]
  PIN di[285]
    DIRECTION INPUT ;
    USE SIGNAL ;
    PORT
      LAYER M5 ;
        RECT  39.216 0 39.24 0.192 ;
    END
  END di[285]
  PIN di[286]
    DIRECTION INPUT ;
    USE SIGNAL ;
    PORT
      LAYER M3 ;
        RECT  39.348 0 39.366 0.144 ;
    END
  END di[286]
  PIN di[287]
    DIRECTION INPUT ;
    USE SIGNAL ;
    PORT
      LAYER M5 ;
        RECT  39.504 0 39.528 0.192 ;
    END
  END di[287]
  PIN di[288]
    DIRECTION INPUT ;
    USE SIGNAL ;
    PORT
      LAYER M3 ;
        RECT  39.6 0 39.618 0.144 ;
    END
  END di[288]
  PIN di[289]
    DIRECTION INPUT ;
    USE SIGNAL ;
    PORT
      LAYER M5 ;
        RECT  39.744 0 39.768 0.192 ;
    END
  END di[289]
  PIN di[28]
    DIRECTION INPUT ;
    USE SIGNAL ;
    PORT
      LAYER M3 ;
        RECT  7.812 0 7.83 0.144 ;
    END
  END di[28]
  PIN di[290]
    DIRECTION INPUT ;
    USE SIGNAL ;
    PORT
      LAYER M3 ;
        RECT  39.852 0 39.87 0.144 ;
    END
  END di[290]
  PIN di[291]
    DIRECTION INPUT ;
    USE SIGNAL ;
    PORT
      LAYER M5 ;
        RECT  39.984 0 40.008 0.192 ;
    END
  END di[291]
  PIN di[292]
    DIRECTION INPUT ;
    USE SIGNAL ;
    PORT
      LAYER M3 ;
        RECT  40.104 0 40.122 0.144 ;
    END
  END di[292]
  PIN di[293]
    DIRECTION INPUT ;
    USE SIGNAL ;
    PORT
      LAYER M5 ;
        RECT  40.224 0 40.248 0.192 ;
    END
  END di[293]
  PIN di[294]
    DIRECTION INPUT ;
    USE SIGNAL ;
    PORT
      LAYER M3 ;
        RECT  40.356 0 40.374 0.144 ;
    END
  END di[294]
  PIN di[295]
    DIRECTION INPUT ;
    USE SIGNAL ;
    PORT
      LAYER M5 ;
        RECT  40.464 0 40.488 0.192 ;
    END
  END di[295]
  PIN di[296]
    DIRECTION INPUT ;
    USE SIGNAL ;
    PORT
      LAYER M3 ;
        RECT  40.572 0 40.59 0.144 ;
    END
  END di[296]
  PIN di[297]
    DIRECTION INPUT ;
    USE SIGNAL ;
    PORT
      LAYER M5 ;
        RECT  40.704 0 40.728 0.192 ;
    END
  END di[297]
  PIN di[298]
    DIRECTION INPUT ;
    USE SIGNAL ;
    PORT
      LAYER M3 ;
        RECT  40.824 0 40.842 0.144 ;
    END
  END di[298]
  PIN di[299]
    DIRECTION INPUT ;
    USE SIGNAL ;
    PORT
      LAYER M5 ;
        RECT  40.944 0 40.968 0.192 ;
    END
  END di[299]
  PIN di[29]
    DIRECTION INPUT ;
    USE SIGNAL ;
    PORT
      LAYER M5 ;
        RECT  7.92 0 7.944 0.192 ;
    END
  END di[29]
  PIN di[2]
    DIRECTION INPUT ;
    USE SIGNAL ;
    PORT
      LAYER M3 ;
        RECT  4.608 0 4.626 0.144 ;
    END
  END di[2]
  PIN di[300]
    DIRECTION INPUT ;
    USE SIGNAL ;
    PORT
      LAYER M3 ;
        RECT  41.076 0 41.094 0.144 ;
    END
  END di[300]
  PIN di[301]
    DIRECTION INPUT ;
    USE SIGNAL ;
    PORT
      LAYER M5 ;
        RECT  41.184 0 41.208 0.192 ;
    END
  END di[301]
  PIN di[302]
    DIRECTION INPUT ;
    USE SIGNAL ;
    PORT
      LAYER M3 ;
        RECT  41.328 0 41.346 0.144 ;
    END
  END di[302]
  PIN di[303]
    DIRECTION INPUT ;
    USE SIGNAL ;
    PORT
      LAYER M5 ;
        RECT  41.424 0 41.448 0.192 ;
    END
  END di[303]
  PIN di[304]
    DIRECTION INPUT ;
    USE SIGNAL ;
    PORT
      LAYER M3 ;
        RECT  41.58 0 41.598 0.144 ;
    END
  END di[304]
  PIN di[305]
    DIRECTION INPUT ;
    USE SIGNAL ;
    PORT
      LAYER M5 ;
        RECT  41.664 0 41.688 0.192 ;
    END
  END di[305]
  PIN di[306]
    DIRECTION INPUT ;
    USE SIGNAL ;
    PORT
      LAYER M3 ;
        RECT  41.796 0 41.814 0.144 ;
    END
  END di[306]
  PIN di[307]
    DIRECTION INPUT ;
    USE SIGNAL ;
    PORT
      LAYER M5 ;
        RECT  41.952 0 41.976 0.192 ;
    END
  END di[307]
  PIN di[308]
    DIRECTION INPUT ;
    USE SIGNAL ;
    PORT
      LAYER M3 ;
        RECT  42.048 0 42.066 0.144 ;
    END
  END di[308]
  PIN di[309]
    DIRECTION INPUT ;
    USE SIGNAL ;
    PORT
      LAYER M5 ;
        RECT  42.192 0 42.216 0.192 ;
    END
  END di[309]
  PIN di[30]
    DIRECTION INPUT ;
    USE SIGNAL ;
    PORT
      LAYER M3 ;
        RECT  8.028 0 8.046 0.144 ;
    END
  END di[30]
  PIN di[310]
    DIRECTION INPUT ;
    USE SIGNAL ;
    PORT
      LAYER M3 ;
        RECT  42.3 0 42.318 0.144 ;
    END
  END di[310]
  PIN di[311]
    DIRECTION INPUT ;
    USE SIGNAL ;
    PORT
      LAYER M5 ;
        RECT  42.432 0 42.456 0.192 ;
    END
  END di[311]
  PIN di[312]
    DIRECTION INPUT ;
    USE SIGNAL ;
    PORT
      LAYER M3 ;
        RECT  42.552 0 42.57 0.144 ;
    END
  END di[312]
  PIN di[313]
    DIRECTION INPUT ;
    USE SIGNAL ;
    PORT
      LAYER M5 ;
        RECT  42.672 0 42.696 0.192 ;
    END
  END di[313]
  PIN di[314]
    DIRECTION INPUT ;
    USE SIGNAL ;
    PORT
      LAYER M3 ;
        RECT  42.804 0 42.822 0.144 ;
    END
  END di[314]
  PIN di[315]
    DIRECTION INPUT ;
    USE SIGNAL ;
    PORT
      LAYER M5 ;
        RECT  42.912 0 42.936 0.192 ;
    END
  END di[315]
  PIN di[316]
    DIRECTION INPUT ;
    USE SIGNAL ;
    PORT
      LAYER M3 ;
        RECT  43.02 0 43.038 0.144 ;
    END
  END di[316]
  PIN di[317]
    DIRECTION INPUT ;
    USE SIGNAL ;
    PORT
      LAYER M5 ;
        RECT  43.152 0 43.176 0.192 ;
    END
  END di[317]
  PIN di[318]
    DIRECTION INPUT ;
    USE SIGNAL ;
    PORT
      LAYER M3 ;
        RECT  43.272 0 43.29 0.144 ;
    END
  END di[318]
  PIN di[319]
    DIRECTION INPUT ;
    USE SIGNAL ;
    PORT
      LAYER M5 ;
        RECT  43.392 0 43.416 0.192 ;
    END
  END di[319]
  PIN di[31]
    DIRECTION INPUT ;
    USE SIGNAL ;
    PORT
      LAYER M5 ;
        RECT  8.16 0 8.184 0.192 ;
    END
  END di[31]
  PIN di[320]
    DIRECTION INPUT ;
    USE SIGNAL ;
    PORT
      LAYER M3 ;
        RECT  43.524 0 43.542 0.144 ;
    END
  END di[320]
  PIN di[321]
    DIRECTION INPUT ;
    USE SIGNAL ;
    PORT
      LAYER M5 ;
        RECT  43.632 0 43.656 0.192 ;
    END
  END di[321]
  PIN di[322]
    DIRECTION INPUT ;
    USE SIGNAL ;
    PORT
      LAYER M3 ;
        RECT  43.776 0 43.794 0.144 ;
    END
  END di[322]
  PIN di[323]
    DIRECTION INPUT ;
    USE SIGNAL ;
    PORT
      LAYER M5 ;
        RECT  43.872 0 43.896 0.192 ;
    END
  END di[323]
  PIN di[324]
    DIRECTION INPUT ;
    USE SIGNAL ;
    PORT
      LAYER M3 ;
        RECT  44.028 0 44.046 0.144 ;
    END
  END di[324]
  PIN di[325]
    DIRECTION INPUT ;
    USE SIGNAL ;
    PORT
      LAYER M5 ;
        RECT  44.112 0 44.136 0.192 ;
    END
  END di[325]
  PIN di[326]
    DIRECTION INPUT ;
    USE SIGNAL ;
    PORT
      LAYER M3 ;
        RECT  44.244 0 44.262 0.144 ;
    END
  END di[326]
  PIN di[327]
    DIRECTION INPUT ;
    USE SIGNAL ;
    PORT
      LAYER M5 ;
        RECT  44.352 0 44.376 0.192 ;
    END
  END di[327]
  PIN di[328]
    DIRECTION INPUT ;
    USE SIGNAL ;
    PORT
      LAYER M3 ;
        RECT  44.496 0 44.514 0.144 ;
    END
  END di[328]
  PIN di[329]
    DIRECTION INPUT ;
    USE SIGNAL ;
    PORT
      LAYER M5 ;
        RECT  44.64 0 44.664 0.192 ;
    END
  END di[329]
  PIN di[32]
    DIRECTION INPUT ;
    USE SIGNAL ;
    PORT
      LAYER M3 ;
        RECT  8.28 0 8.298 0.144 ;
    END
  END di[32]
  PIN di[330]
    DIRECTION INPUT ;
    USE SIGNAL ;
    PORT
      LAYER M3 ;
        RECT  44.748 0 44.766 0.144 ;
    END
  END di[330]
  PIN di[331]
    DIRECTION INPUT ;
    USE SIGNAL ;
    PORT
      LAYER M5 ;
        RECT  44.88 0 44.904 0.192 ;
    END
  END di[331]
  PIN di[332]
    DIRECTION INPUT ;
    USE SIGNAL ;
    PORT
      LAYER M3 ;
        RECT  45 0 45.018 0.144 ;
    END
  END di[332]
  PIN di[333]
    DIRECTION INPUT ;
    USE SIGNAL ;
    PORT
      LAYER M5 ;
        RECT  45.12 0 45.144 0.192 ;
    END
  END di[333]
  PIN di[334]
    DIRECTION INPUT ;
    USE SIGNAL ;
    PORT
      LAYER M3 ;
        RECT  45.252 0 45.27 0.144 ;
    END
  END di[334]
  PIN di[335]
    DIRECTION INPUT ;
    USE SIGNAL ;
    PORT
      LAYER M5 ;
        RECT  45.36 0 45.384 0.192 ;
    END
  END di[335]
  PIN di[336]
    DIRECTION INPUT ;
    USE SIGNAL ;
    PORT
      LAYER M3 ;
        RECT  45.468 0 45.486 0.144 ;
    END
  END di[336]
  PIN di[337]
    DIRECTION INPUT ;
    USE SIGNAL ;
    PORT
      LAYER M5 ;
        RECT  45.6 0 45.624 0.192 ;
    END
  END di[337]
  PIN di[338]
    DIRECTION INPUT ;
    USE SIGNAL ;
    PORT
      LAYER M3 ;
        RECT  45.72 0 45.738 0.144 ;
    END
  END di[338]
  PIN di[339]
    DIRECTION INPUT ;
    USE SIGNAL ;
    PORT
      LAYER M5 ;
        RECT  45.84 0 45.864 0.192 ;
    END
  END di[339]
  PIN di[33]
    DIRECTION INPUT ;
    USE SIGNAL ;
    PORT
      LAYER M5 ;
        RECT  8.4 0 8.424 0.192 ;
    END
  END di[33]
  PIN di[340]
    DIRECTION INPUT ;
    USE SIGNAL ;
    PORT
      LAYER M3 ;
        RECT  45.972 0 45.99 0.144 ;
    END
  END di[340]
  PIN di[341]
    DIRECTION INPUT ;
    USE SIGNAL ;
    PORT
      LAYER M5 ;
        RECT  46.08 0 46.104 0.192 ;
    END
  END di[341]
  PIN di[342]
    DIRECTION INPUT ;
    USE SIGNAL ;
    PORT
      LAYER M3 ;
        RECT  46.224 0 46.242 0.144 ;
    END
  END di[342]
  PIN di[343]
    DIRECTION INPUT ;
    USE SIGNAL ;
    PORT
      LAYER M5 ;
        RECT  46.32 0 46.344 0.192 ;
    END
  END di[343]
  PIN di[344]
    DIRECTION INPUT ;
    USE SIGNAL ;
    PORT
      LAYER M3 ;
        RECT  46.476 0 46.494 0.144 ;
    END
  END di[344]
  PIN di[345]
    DIRECTION INPUT ;
    USE SIGNAL ;
    PORT
      LAYER M5 ;
        RECT  46.56 0 46.584 0.192 ;
    END
  END di[345]
  PIN di[346]
    DIRECTION INPUT ;
    USE SIGNAL ;
    PORT
      LAYER M3 ;
        RECT  46.692 0 46.71 0.144 ;
    END
  END di[346]
  PIN di[347]
    DIRECTION INPUT ;
    USE SIGNAL ;
    PORT
      LAYER M5 ;
        RECT  46.8 0 46.824 0.192 ;
    END
  END di[347]
  PIN di[348]
    DIRECTION INPUT ;
    USE SIGNAL ;
    PORT
      LAYER M3 ;
        RECT  46.944 0 46.962 0.144 ;
    END
  END di[348]
  PIN di[349]
    DIRECTION INPUT ;
    USE SIGNAL ;
    PORT
      LAYER M5 ;
        RECT  47.088 0 47.112 0.192 ;
    END
  END di[349]
  PIN di[34]
    DIRECTION INPUT ;
    USE SIGNAL ;
    PORT
      LAYER M3 ;
        RECT  8.532 0 8.55 0.144 ;
    END
  END di[34]
  PIN di[350]
    DIRECTION INPUT ;
    USE SIGNAL ;
    PORT
      LAYER M3 ;
        RECT  47.196 0 47.214 0.144 ;
    END
  END di[350]
  PIN di[351]
    DIRECTION INPUT ;
    USE SIGNAL ;
    PORT
      LAYER M5 ;
        RECT  47.328 0 47.352 0.192 ;
    END
  END di[351]
  PIN di[352]
    DIRECTION INPUT ;
    USE SIGNAL ;
    PORT
      LAYER M3 ;
        RECT  47.448 0 47.466 0.144 ;
    END
  END di[352]
  PIN di[353]
    DIRECTION INPUT ;
    USE SIGNAL ;
    PORT
      LAYER M5 ;
        RECT  47.568 0 47.592 0.192 ;
    END
  END di[353]
  PIN di[354]
    DIRECTION INPUT ;
    USE SIGNAL ;
    PORT
      LAYER M3 ;
        RECT  47.664 0 47.682 0.144 ;
    END
  END di[354]
  PIN di[355]
    DIRECTION INPUT ;
    USE SIGNAL ;
    PORT
      LAYER M5 ;
        RECT  47.808 0 47.832 0.192 ;
    END
  END di[355]
  PIN di[356]
    DIRECTION INPUT ;
    USE SIGNAL ;
    PORT
      LAYER M3 ;
        RECT  47.916 0 47.934 0.144 ;
    END
  END di[356]
  PIN di[357]
    DIRECTION INPUT ;
    USE SIGNAL ;
    PORT
      LAYER M5 ;
        RECT  48.048 0 48.072 0.192 ;
    END
  END di[357]
  PIN di[358]
    DIRECTION INPUT ;
    USE SIGNAL ;
    PORT
      LAYER M3 ;
        RECT  48.168 0 48.186 0.144 ;
    END
  END di[358]
  PIN di[359]
    DIRECTION INPUT ;
    USE SIGNAL ;
    PORT
      LAYER M5 ;
        RECT  48.288 0 48.312 0.192 ;
    END
  END di[359]
  PIN di[35]
    DIRECTION INPUT ;
    USE SIGNAL ;
    PORT
      LAYER M5 ;
        RECT  8.64 0 8.664 0.192 ;
    END
  END di[35]
  PIN di[360]
    DIRECTION INPUT ;
    USE SIGNAL ;
    PORT
      LAYER M3 ;
        RECT  48.42 0 48.438 0.144 ;
    END
  END di[360]
  PIN di[361]
    DIRECTION INPUT ;
    USE SIGNAL ;
    PORT
      LAYER M5 ;
        RECT  48.528 0 48.552 0.192 ;
    END
  END di[361]
  PIN di[362]
    DIRECTION INPUT ;
    USE SIGNAL ;
    PORT
      LAYER M3 ;
        RECT  48.672 0 48.69 0.144 ;
    END
  END di[362]
  PIN di[363]
    DIRECTION INPUT ;
    USE SIGNAL ;
    PORT
      LAYER M5 ;
        RECT  48.768 0 48.792 0.192 ;
    END
  END di[363]
  PIN di[364]
    DIRECTION INPUT ;
    USE SIGNAL ;
    PORT
      LAYER M3 ;
        RECT  48.888 0 48.906 0.144 ;
    END
  END di[364]
  PIN di[365]
    DIRECTION INPUT ;
    USE SIGNAL ;
    PORT
      LAYER M5 ;
        RECT  49.008 0 49.032 0.192 ;
    END
  END di[365]
  PIN di[366]
    DIRECTION INPUT ;
    USE SIGNAL ;
    PORT
      LAYER M3 ;
        RECT  49.14 0 49.158 0.144 ;
    END
  END di[366]
  PIN di[367]
    DIRECTION INPUT ;
    USE SIGNAL ;
    PORT
      LAYER M5 ;
        RECT  49.248 0 49.272 0.192 ;
    END
  END di[367]
  PIN di[368]
    DIRECTION INPUT ;
    USE SIGNAL ;
    PORT
      LAYER M3 ;
        RECT  49.392 0 49.41 0.144 ;
    END
  END di[368]
  PIN di[369]
    DIRECTION INPUT ;
    USE SIGNAL ;
    PORT
      LAYER M5 ;
        RECT  49.536 0 49.56 0.192 ;
    END
  END di[369]
  PIN di[36]
    DIRECTION INPUT ;
    USE SIGNAL ;
    PORT
      LAYER M3 ;
        RECT  8.784 0 8.802 0.144 ;
    END
  END di[36]
  PIN di[370]
    DIRECTION INPUT ;
    USE SIGNAL ;
    PORT
      LAYER M3 ;
        RECT  49.644 0 49.662 0.144 ;
    END
  END di[370]
  PIN di[371]
    DIRECTION INPUT ;
    USE SIGNAL ;
    PORT
      LAYER M5 ;
        RECT  49.776 0 49.8 0.192 ;
    END
  END di[371]
  PIN di[372]
    DIRECTION INPUT ;
    USE SIGNAL ;
    PORT
      LAYER M3 ;
        RECT  49.896 0 49.914 0.144 ;
    END
  END di[372]
  PIN di[373]
    DIRECTION INPUT ;
    USE SIGNAL ;
    PORT
      LAYER M5 ;
        RECT  50.016 0 50.04 0.192 ;
    END
  END di[373]
  PIN di[374]
    DIRECTION INPUT ;
    USE SIGNAL ;
    PORT
      LAYER M3 ;
        RECT  50.112 0 50.13 0.144 ;
    END
  END di[374]
  PIN di[375]
    DIRECTION INPUT ;
    USE SIGNAL ;
    PORT
      LAYER M5 ;
        RECT  50.256 0 50.28 0.192 ;
    END
  END di[375]
  PIN di[376]
    DIRECTION INPUT ;
    USE SIGNAL ;
    PORT
      LAYER M3 ;
        RECT  50.364 0 50.382 0.144 ;
    END
  END di[376]
  PIN di[377]
    DIRECTION INPUT ;
    USE SIGNAL ;
    PORT
      LAYER M5 ;
        RECT  50.496 0 50.52 0.192 ;
    END
  END di[377]
  PIN di[378]
    DIRECTION INPUT ;
    USE SIGNAL ;
    PORT
      LAYER M3 ;
        RECT  50.616 0 50.634 0.144 ;
    END
  END di[378]
  PIN di[379]
    DIRECTION INPUT ;
    USE SIGNAL ;
    PORT
      LAYER M5 ;
        RECT  50.736 0 50.76 0.192 ;
    END
  END di[379]
  PIN di[37]
    DIRECTION INPUT ;
    USE SIGNAL ;
    PORT
      LAYER M5 ;
        RECT  8.88 0 8.904 0.192 ;
    END
  END di[37]
  PIN di[380]
    DIRECTION INPUT ;
    USE SIGNAL ;
    PORT
      LAYER M3 ;
        RECT  50.868 0 50.886 0.144 ;
    END
  END di[380]
  PIN di[381]
    DIRECTION INPUT ;
    USE SIGNAL ;
    PORT
      LAYER M5 ;
        RECT  50.976 0 51 0.192 ;
    END
  END di[381]
  PIN di[382]
    DIRECTION INPUT ;
    USE SIGNAL ;
    PORT
      LAYER M3 ;
        RECT  51.12 0 51.138 0.144 ;
    END
  END di[382]
  PIN di[383]
    DIRECTION INPUT ;
    USE SIGNAL ;
    PORT
      LAYER M5 ;
        RECT  51.216 0 51.24 0.192 ;
    END
  END di[383]
  PIN di[384]
    DIRECTION INPUT ;
    USE SIGNAL ;
    PORT
      LAYER M3 ;
        RECT  51.336 0 51.354 0.144 ;
    END
  END di[384]
  PIN di[385]
    DIRECTION INPUT ;
    USE SIGNAL ;
    PORT
      LAYER M5 ;
        RECT  51.456 0 51.48 0.192 ;
    END
  END di[385]
  PIN di[386]
    DIRECTION INPUT ;
    USE SIGNAL ;
    PORT
      LAYER M3 ;
        RECT  51.588 0 51.606 0.144 ;
    END
  END di[386]
  PIN di[387]
    DIRECTION INPUT ;
    USE SIGNAL ;
    PORT
      LAYER M5 ;
        RECT  51.696 0 51.72 0.192 ;
    END
  END di[387]
  PIN di[388]
    DIRECTION INPUT ;
    USE SIGNAL ;
    PORT
      LAYER M3 ;
        RECT  51.84 0 51.858 0.144 ;
    END
  END di[388]
  PIN di[389]
    DIRECTION INPUT ;
    USE SIGNAL ;
    PORT
      LAYER M5 ;
        RECT  51.984 0 52.008 0.192 ;
    END
  END di[389]
  PIN di[38]
    DIRECTION INPUT ;
    USE SIGNAL ;
    PORT
      LAYER M3 ;
        RECT  9.036 0 9.054 0.144 ;
    END
  END di[38]
  PIN di[390]
    DIRECTION INPUT ;
    USE SIGNAL ;
    PORT
      LAYER M3 ;
        RECT  52.092 0 52.11 0.144 ;
    END
  END di[390]
  PIN di[391]
    DIRECTION INPUT ;
    USE SIGNAL ;
    PORT
      LAYER M5 ;
        RECT  52.224 0 52.248 0.192 ;
    END
  END di[391]
  PIN di[392]
    DIRECTION INPUT ;
    USE SIGNAL ;
    PORT
      LAYER M3 ;
        RECT  52.344 0 52.362 0.144 ;
    END
  END di[392]
  PIN di[393]
    DIRECTION INPUT ;
    USE SIGNAL ;
    PORT
      LAYER M5 ;
        RECT  52.464 0 52.488 0.192 ;
    END
  END di[393]
  PIN di[394]
    DIRECTION INPUT ;
    USE SIGNAL ;
    PORT
      LAYER M3 ;
        RECT  52.56 0 52.578 0.144 ;
    END
  END di[394]
  PIN di[395]
    DIRECTION INPUT ;
    USE SIGNAL ;
    PORT
      LAYER M5 ;
        RECT  52.704 0 52.728 0.192 ;
    END
  END di[395]
  PIN di[396]
    DIRECTION INPUT ;
    USE SIGNAL ;
    PORT
      LAYER M3 ;
        RECT  52.812 0 52.83 0.144 ;
    END
  END di[396]
  PIN di[397]
    DIRECTION INPUT ;
    USE SIGNAL ;
    PORT
      LAYER M5 ;
        RECT  52.944 0 52.968 0.192 ;
    END
  END di[397]
  PIN di[398]
    DIRECTION INPUT ;
    USE SIGNAL ;
    PORT
      LAYER M3 ;
        RECT  53.064 0 53.082 0.144 ;
    END
  END di[398]
  PIN di[399]
    DIRECTION INPUT ;
    USE SIGNAL ;
    PORT
      LAYER M5 ;
        RECT  53.184 0 53.208 0.192 ;
    END
  END di[399]
  PIN di[39]
    DIRECTION INPUT ;
    USE SIGNAL ;
    PORT
      LAYER M5 ;
        RECT  9.12 0 9.144 0.192 ;
    END
  END di[39]
  PIN di[3]
    DIRECTION INPUT ;
    USE SIGNAL ;
    PORT
      LAYER M5 ;
        RECT  4.752 0 4.776 0.192 ;
    END
  END di[3]
  PIN di[400]
    DIRECTION INPUT ;
    USE SIGNAL ;
    PORT
      LAYER M3 ;
        RECT  53.316 0 53.334 0.144 ;
    END
  END di[400]
  PIN di[401]
    DIRECTION INPUT ;
    USE SIGNAL ;
    PORT
      LAYER M5 ;
        RECT  53.424 0 53.448 0.192 ;
    END
  END di[401]
  PIN di[402]
    DIRECTION INPUT ;
    USE SIGNAL ;
    PORT
      LAYER M3 ;
        RECT  53.568 0 53.586 0.144 ;
    END
  END di[402]
  PIN di[403]
    DIRECTION INPUT ;
    USE SIGNAL ;
    PORT
      LAYER M5 ;
        RECT  53.664 0 53.688 0.192 ;
    END
  END di[403]
  PIN di[404]
    DIRECTION INPUT ;
    USE SIGNAL ;
    PORT
      LAYER M3 ;
        RECT  53.784 0 53.802 0.144 ;
    END
  END di[404]
  PIN di[405]
    DIRECTION INPUT ;
    USE SIGNAL ;
    PORT
      LAYER M5 ;
        RECT  53.904 0 53.928 0.192 ;
    END
  END di[405]
  PIN di[406]
    DIRECTION INPUT ;
    USE SIGNAL ;
    PORT
      LAYER M3 ;
        RECT  54.036 0 54.054 0.144 ;
    END
  END di[406]
  PIN di[407]
    DIRECTION INPUT ;
    USE SIGNAL ;
    PORT
      LAYER M5 ;
        RECT  54.144 0 54.168 0.192 ;
    END
  END di[407]
  PIN di[408]
    DIRECTION INPUT ;
    USE SIGNAL ;
    PORT
      LAYER M3 ;
        RECT  54.288 0 54.306 0.144 ;
    END
  END di[408]
  PIN di[409]
    DIRECTION INPUT ;
    USE SIGNAL ;
    PORT
      LAYER M5 ;
        RECT  54.384 0 54.408 0.192 ;
    END
  END di[409]
  PIN di[40]
    DIRECTION INPUT ;
    USE SIGNAL ;
    PORT
      LAYER M3 ;
        RECT  9.252 0 9.27 0.144 ;
    END
  END di[40]
  PIN di[410]
    DIRECTION INPUT ;
    USE SIGNAL ;
    PORT
      LAYER M3 ;
        RECT  54.54 0 54.558 0.144 ;
    END
  END di[410]
  PIN di[411]
    DIRECTION INPUT ;
    USE SIGNAL ;
    PORT
      LAYER M5 ;
        RECT  54.672 0 54.696 0.192 ;
    END
  END di[411]
  PIN di[412]
    DIRECTION INPUT ;
    USE SIGNAL ;
    PORT
      LAYER M3 ;
        RECT  54.792 0 54.81 0.144 ;
    END
  END di[412]
  PIN di[413]
    DIRECTION INPUT ;
    USE SIGNAL ;
    PORT
      LAYER M5 ;
        RECT  54.912 0 54.936 0.192 ;
    END
  END di[413]
  PIN di[414]
    DIRECTION INPUT ;
    USE SIGNAL ;
    PORT
      LAYER M3 ;
        RECT  55.008 0 55.026 0.144 ;
    END
  END di[414]
  PIN di[415]
    DIRECTION INPUT ;
    USE SIGNAL ;
    PORT
      LAYER M5 ;
        RECT  55.152 0 55.176 0.192 ;
    END
  END di[415]
  PIN di[416]
    DIRECTION INPUT ;
    USE SIGNAL ;
    PORT
      LAYER M3 ;
        RECT  55.26 0 55.278 0.144 ;
    END
  END di[416]
  PIN di[417]
    DIRECTION INPUT ;
    USE SIGNAL ;
    PORT
      LAYER M5 ;
        RECT  55.392 0 55.416 0.192 ;
    END
  END di[417]
  PIN di[418]
    DIRECTION INPUT ;
    USE SIGNAL ;
    PORT
      LAYER M3 ;
        RECT  55.512 0 55.53 0.144 ;
    END
  END di[418]
  PIN di[419]
    DIRECTION INPUT ;
    USE SIGNAL ;
    PORT
      LAYER M5 ;
        RECT  55.632 0 55.656 0.192 ;
    END
  END di[419]
  PIN di[41]
    DIRECTION INPUT ;
    USE SIGNAL ;
    PORT
      LAYER M5 ;
        RECT  9.408 0 9.432 0.192 ;
    END
  END di[41]
  PIN di[420]
    DIRECTION INPUT ;
    USE SIGNAL ;
    PORT
      LAYER M3 ;
        RECT  55.764 0 55.782 0.144 ;
    END
  END di[420]
  PIN di[421]
    DIRECTION INPUT ;
    USE SIGNAL ;
    PORT
      LAYER M5 ;
        RECT  55.872 0 55.896 0.192 ;
    END
  END di[421]
  PIN di[422]
    DIRECTION INPUT ;
    USE SIGNAL ;
    PORT
      LAYER M3 ;
        RECT  56.016 0 56.034 0.144 ;
    END
  END di[422]
  PIN di[423]
    DIRECTION INPUT ;
    USE SIGNAL ;
    PORT
      LAYER M5 ;
        RECT  56.112 0 56.136 0.192 ;
    END
  END di[423]
  PIN di[424]
    DIRECTION INPUT ;
    USE SIGNAL ;
    PORT
      LAYER M3 ;
        RECT  56.232 0 56.25 0.144 ;
    END
  END di[424]
  PIN di[425]
    DIRECTION INPUT ;
    USE SIGNAL ;
    PORT
      LAYER M5 ;
        RECT  56.352 0 56.376 0.192 ;
    END
  END di[425]
  PIN di[426]
    DIRECTION INPUT ;
    USE SIGNAL ;
    PORT
      LAYER M3 ;
        RECT  56.484 0 56.502 0.144 ;
    END
  END di[426]
  PIN di[427]
    DIRECTION INPUT ;
    USE SIGNAL ;
    PORT
      LAYER M5 ;
        RECT  56.592 0 56.616 0.192 ;
    END
  END di[427]
  PIN di[428]
    DIRECTION INPUT ;
    USE SIGNAL ;
    PORT
      LAYER M3 ;
        RECT  56.736 0 56.754 0.144 ;
    END
  END di[428]
  PIN di[429]
    DIRECTION INPUT ;
    USE SIGNAL ;
    PORT
      LAYER M5 ;
        RECT  56.832 0 56.856 0.192 ;
    END
  END di[429]
  PIN di[42]
    DIRECTION INPUT ;
    USE SIGNAL ;
    PORT
      LAYER M3 ;
        RECT  9.504 0 9.522 0.144 ;
    END
  END di[42]
  PIN di[430]
    DIRECTION INPUT ;
    USE SIGNAL ;
    PORT
      LAYER M3 ;
        RECT  56.988 0 57.006 0.144 ;
    END
  END di[430]
  PIN di[431]
    DIRECTION INPUT ;
    USE SIGNAL ;
    PORT
      LAYER M5 ;
        RECT  57.12 0 57.144 0.192 ;
    END
  END di[431]
  PIN di[432]
    DIRECTION INPUT ;
    USE SIGNAL ;
    PORT
      LAYER M3 ;
        RECT  57.24 0 57.258 0.144 ;
    END
  END di[432]
  PIN di[433]
    DIRECTION INPUT ;
    USE SIGNAL ;
    PORT
      LAYER M5 ;
        RECT  57.36 0 57.384 0.192 ;
    END
  END di[433]
  PIN di[434]
    DIRECTION INPUT ;
    USE SIGNAL ;
    PORT
      LAYER M3 ;
        RECT  57.456 0 57.474 0.144 ;
    END
  END di[434]
  PIN di[435]
    DIRECTION INPUT ;
    USE SIGNAL ;
    PORT
      LAYER M5 ;
        RECT  57.6 0 57.624 0.192 ;
    END
  END di[435]
  PIN di[436]
    DIRECTION INPUT ;
    USE SIGNAL ;
    PORT
      LAYER M3 ;
        RECT  57.708 0 57.726 0.144 ;
    END
  END di[436]
  PIN di[437]
    DIRECTION INPUT ;
    USE SIGNAL ;
    PORT
      LAYER M5 ;
        RECT  57.84 0 57.864 0.192 ;
    END
  END di[437]
  PIN di[438]
    DIRECTION INPUT ;
    USE SIGNAL ;
    PORT
      LAYER M3 ;
        RECT  57.96 0 57.978 0.144 ;
    END
  END di[438]
  PIN di[439]
    DIRECTION INPUT ;
    USE SIGNAL ;
    PORT
      LAYER M5 ;
        RECT  58.08 0 58.104 0.192 ;
    END
  END di[439]
  PIN di[43]
    DIRECTION INPUT ;
    USE SIGNAL ;
    PORT
      LAYER M5 ;
        RECT  9.648 0 9.672 0.192 ;
    END
  END di[43]
  PIN di[440]
    DIRECTION INPUT ;
    USE SIGNAL ;
    PORT
      LAYER M3 ;
        RECT  58.212 0 58.23 0.144 ;
    END
  END di[440]
  PIN di[441]
    DIRECTION INPUT ;
    USE SIGNAL ;
    PORT
      LAYER M5 ;
        RECT  58.32 0 58.344 0.192 ;
    END
  END di[441]
  PIN di[442]
    DIRECTION INPUT ;
    USE SIGNAL ;
    PORT
      LAYER M3 ;
        RECT  58.464 0 58.482 0.144 ;
    END
  END di[442]
  PIN di[443]
    DIRECTION INPUT ;
    USE SIGNAL ;
    PORT
      LAYER M5 ;
        RECT  58.56 0 58.584 0.192 ;
    END
  END di[443]
  PIN di[444]
    DIRECTION INPUT ;
    USE SIGNAL ;
    PORT
      LAYER M3 ;
        RECT  58.68 0 58.698 0.144 ;
    END
  END di[444]
  PIN di[445]
    DIRECTION INPUT ;
    USE SIGNAL ;
    PORT
      LAYER M5 ;
        RECT  58.8 0 58.824 0.192 ;
    END
  END di[445]
  PIN di[446]
    DIRECTION INPUT ;
    USE SIGNAL ;
    PORT
      LAYER M3 ;
        RECT  58.932 0 58.95 0.144 ;
    END
  END di[446]
  PIN di[447]
    DIRECTION INPUT ;
    USE SIGNAL ;
    PORT
      LAYER M5 ;
        RECT  59.04 0 59.064 0.192 ;
    END
  END di[447]
  PIN di[448]
    DIRECTION INPUT ;
    USE SIGNAL ;
    PORT
      LAYER M3 ;
        RECT  59.184 0 59.202 0.144 ;
    END
  END di[448]
  PIN di[449]
    DIRECTION INPUT ;
    USE SIGNAL ;
    PORT
      LAYER M5 ;
        RECT  59.28 0 59.304 0.192 ;
    END
  END di[449]
  PIN di[44]
    DIRECTION INPUT ;
    USE SIGNAL ;
    PORT
      LAYER M3 ;
        RECT  9.756 0 9.774 0.144 ;
    END
  END di[44]
  PIN di[450]
    DIRECTION INPUT ;
    USE SIGNAL ;
    PORT
      LAYER M3 ;
        RECT  59.436 0 59.454 0.144 ;
    END
  END di[450]
  PIN di[451]
    DIRECTION INPUT ;
    USE SIGNAL ;
    PORT
      LAYER M5 ;
        RECT  59.568 0 59.592 0.192 ;
    END
  END di[451]
  PIN di[452]
    DIRECTION INPUT ;
    USE SIGNAL ;
    PORT
      LAYER M3 ;
        RECT  59.688 0 59.706 0.144 ;
    END
  END di[452]
  PIN di[453]
    DIRECTION INPUT ;
    USE SIGNAL ;
    PORT
      LAYER M5 ;
        RECT  59.808 0 59.832 0.192 ;
    END
  END di[453]
  PIN di[454]
    DIRECTION INPUT ;
    USE SIGNAL ;
    PORT
      LAYER M3 ;
        RECT  59.904 0 59.922 0.144 ;
    END
  END di[454]
  PIN di[455]
    DIRECTION INPUT ;
    USE SIGNAL ;
    PORT
      LAYER M5 ;
        RECT  60.048 0 60.072 0.192 ;
    END
  END di[455]
  PIN di[456]
    DIRECTION INPUT ;
    USE SIGNAL ;
    PORT
      LAYER M3 ;
        RECT  60.156 0 60.174 0.144 ;
    END
  END di[456]
  PIN di[457]
    DIRECTION INPUT ;
    USE SIGNAL ;
    PORT
      LAYER M5 ;
        RECT  60.288 0 60.312 0.192 ;
    END
  END di[457]
  PIN di[458]
    DIRECTION INPUT ;
    USE SIGNAL ;
    PORT
      LAYER M3 ;
        RECT  60.408 0 60.426 0.144 ;
    END
  END di[458]
  PIN di[459]
    DIRECTION INPUT ;
    USE SIGNAL ;
    PORT
      LAYER M5 ;
        RECT  60.528 0 60.552 0.192 ;
    END
  END di[459]
  PIN di[45]
    DIRECTION INPUT ;
    USE SIGNAL ;
    PORT
      LAYER M5 ;
        RECT  9.888 0 9.912 0.192 ;
    END
  END di[45]
  PIN di[460]
    DIRECTION INPUT ;
    USE SIGNAL ;
    PORT
      LAYER M3 ;
        RECT  60.66 0 60.678 0.144 ;
    END
  END di[460]
  PIN di[461]
    DIRECTION INPUT ;
    USE SIGNAL ;
    PORT
      LAYER M5 ;
        RECT  60.768 0 60.792 0.192 ;
    END
  END di[461]
  PIN di[462]
    DIRECTION INPUT ;
    USE SIGNAL ;
    PORT
      LAYER M3 ;
        RECT  60.912 0 60.93 0.144 ;
    END
  END di[462]
  PIN di[463]
    DIRECTION INPUT ;
    USE SIGNAL ;
    PORT
      LAYER M5 ;
        RECT  61.008 0 61.032 0.192 ;
    END
  END di[463]
  PIN di[464]
    DIRECTION INPUT ;
    USE SIGNAL ;
    PORT
      LAYER M3 ;
        RECT  61.128 0 61.146 0.144 ;
    END
  END di[464]
  PIN di[465]
    DIRECTION INPUT ;
    USE SIGNAL ;
    PORT
      LAYER M5 ;
        RECT  61.248 0 61.272 0.192 ;
    END
  END di[465]
  PIN di[466]
    DIRECTION INPUT ;
    USE SIGNAL ;
    PORT
      LAYER M3 ;
        RECT  61.38 0 61.398 0.144 ;
    END
  END di[466]
  PIN di[467]
    DIRECTION INPUT ;
    USE SIGNAL ;
    PORT
      LAYER M5 ;
        RECT  61.488 0 61.512 0.192 ;
    END
  END di[467]
  PIN di[468]
    DIRECTION INPUT ;
    USE SIGNAL ;
    PORT
      LAYER M3 ;
        RECT  61.632 0 61.65 0.144 ;
    END
  END di[468]
  PIN di[469]
    DIRECTION INPUT ;
    USE SIGNAL ;
    PORT
      LAYER M5 ;
        RECT  61.728 0 61.752 0.192 ;
    END
  END di[469]
  PIN di[46]
    DIRECTION INPUT ;
    USE SIGNAL ;
    PORT
      LAYER M3 ;
        RECT  10.008 0 10.026 0.144 ;
    END
  END di[46]
  PIN di[470]
    DIRECTION INPUT ;
    USE SIGNAL ;
    PORT
      LAYER M3 ;
        RECT  61.884 0 61.902 0.144 ;
    END
  END di[470]
  PIN di[471]
    DIRECTION INPUT ;
    USE SIGNAL ;
    PORT
      LAYER M5 ;
        RECT  62.016 0 62.04 0.192 ;
    END
  END di[471]
  PIN di[472]
    DIRECTION INPUT ;
    USE SIGNAL ;
    PORT
      LAYER M3 ;
        RECT  62.136 0 62.154 0.144 ;
    END
  END di[472]
  PIN di[473]
    DIRECTION INPUT ;
    USE SIGNAL ;
    PORT
      LAYER M5 ;
        RECT  62.256 0 62.28 0.192 ;
    END
  END di[473]
  PIN di[474]
    DIRECTION INPUT ;
    USE SIGNAL ;
    PORT
      LAYER M3 ;
        RECT  62.352 0 62.37 0.144 ;
    END
  END di[474]
  PIN di[475]
    DIRECTION INPUT ;
    USE SIGNAL ;
    PORT
      LAYER M5 ;
        RECT  62.496 0 62.52 0.192 ;
    END
  END di[475]
  PIN di[476]
    DIRECTION INPUT ;
    USE SIGNAL ;
    PORT
      LAYER M3 ;
        RECT  62.604 0 62.622 0.144 ;
    END
  END di[476]
  PIN di[477]
    DIRECTION INPUT ;
    USE SIGNAL ;
    PORT
      LAYER M5 ;
        RECT  62.736 0 62.76 0.192 ;
    END
  END di[477]
  PIN di[478]
    DIRECTION INPUT ;
    USE SIGNAL ;
    PORT
      LAYER M3 ;
        RECT  62.856 0 62.874 0.144 ;
    END
  END di[478]
  PIN di[479]
    DIRECTION INPUT ;
    USE SIGNAL ;
    PORT
      LAYER M5 ;
        RECT  62.976 0 63 0.192 ;
    END
  END di[479]
  PIN di[47]
    DIRECTION INPUT ;
    USE SIGNAL ;
    PORT
      LAYER M5 ;
        RECT  10.128 0 10.152 0.192 ;
    END
  END di[47]
  PIN di[480]
    DIRECTION INPUT ;
    USE SIGNAL ;
    PORT
      LAYER M3 ;
        RECT  63.108 0 63.126 0.144 ;
    END
  END di[480]
  PIN di[481]
    DIRECTION INPUT ;
    USE SIGNAL ;
    PORT
      LAYER M5 ;
        RECT  63.216 0 63.24 0.192 ;
    END
  END di[481]
  PIN di[482]
    DIRECTION INPUT ;
    USE SIGNAL ;
    PORT
      LAYER M3 ;
        RECT  63.324 0 63.342 0.144 ;
    END
  END di[482]
  PIN di[483]
    DIRECTION INPUT ;
    USE SIGNAL ;
    PORT
      LAYER M5 ;
        RECT  63.456 0 63.48 0.192 ;
    END
  END di[483]
  PIN di[484]
    DIRECTION INPUT ;
    USE SIGNAL ;
    PORT
      LAYER M3 ;
        RECT  63.576 0 63.594 0.144 ;
    END
  END di[484]
  PIN di[485]
    DIRECTION INPUT ;
    USE SIGNAL ;
    PORT
      LAYER M5 ;
        RECT  63.696 0 63.72 0.192 ;
    END
  END di[485]
  PIN di[486]
    DIRECTION INPUT ;
    USE SIGNAL ;
    PORT
      LAYER M3 ;
        RECT  63.828 0 63.846 0.144 ;
    END
  END di[486]
  PIN di[487]
    DIRECTION INPUT ;
    USE SIGNAL ;
    PORT
      LAYER M5 ;
        RECT  63.936 0 63.96 0.192 ;
    END
  END di[487]
  PIN di[488]
    DIRECTION INPUT ;
    USE SIGNAL ;
    PORT
      LAYER M3 ;
        RECT  64.08 0 64.098 0.144 ;
    END
  END di[488]
  PIN di[489]
    DIRECTION INPUT ;
    USE SIGNAL ;
    PORT
      LAYER M5 ;
        RECT  64.176 0 64.2 0.192 ;
    END
  END di[489]
  PIN di[48]
    DIRECTION INPUT ;
    USE SIGNAL ;
    PORT
      LAYER M3 ;
        RECT  10.26 0 10.278 0.144 ;
    END
  END di[48]
  PIN di[490]
    DIRECTION INPUT ;
    USE SIGNAL ;
    PORT
      LAYER M3 ;
        RECT  64.332 0 64.35 0.144 ;
    END
  END di[490]
  PIN di[491]
    DIRECTION INPUT ;
    USE SIGNAL ;
    PORT
      LAYER M5 ;
        RECT  64.416 0 64.44 0.192 ;
    END
  END di[491]
  PIN di[492]
    DIRECTION INPUT ;
    USE SIGNAL ;
    PORT
      LAYER M3 ;
        RECT  64.548 0 64.566 0.144 ;
    END
  END di[492]
  PIN di[493]
    DIRECTION INPUT ;
    USE SIGNAL ;
    PORT
      LAYER M5 ;
        RECT  64.704 0 64.728 0.192 ;
    END
  END di[493]
  PIN di[494]
    DIRECTION INPUT ;
    USE SIGNAL ;
    PORT
      LAYER M3 ;
        RECT  64.8 0 64.818 0.144 ;
    END
  END di[494]
  PIN di[495]
    DIRECTION INPUT ;
    USE SIGNAL ;
    PORT
      LAYER M5 ;
        RECT  64.944 0 64.968 0.192 ;
    END
  END di[495]
  PIN di[496]
    DIRECTION INPUT ;
    USE SIGNAL ;
    PORT
      LAYER M3 ;
        RECT  65.052 0 65.07 0.144 ;
    END
  END di[496]
  PIN di[497]
    DIRECTION INPUT ;
    USE SIGNAL ;
    PORT
      LAYER M5 ;
        RECT  65.184 0 65.208 0.192 ;
    END
  END di[497]
  PIN di[498]
    DIRECTION INPUT ;
    USE SIGNAL ;
    PORT
      LAYER M3 ;
        RECT  65.304 0 65.322 0.144 ;
    END
  END di[498]
  PIN di[499]
    DIRECTION INPUT ;
    USE SIGNAL ;
    PORT
      LAYER M5 ;
        RECT  65.424 0 65.448 0.192 ;
    END
  END di[499]
  PIN di[49]
    DIRECTION INPUT ;
    USE SIGNAL ;
    PORT
      LAYER M5 ;
        RECT  10.368 0 10.392 0.192 ;
    END
  END di[49]
  PIN di[4]
    DIRECTION INPUT ;
    USE SIGNAL ;
    PORT
      LAYER M3 ;
        RECT  4.86 0 4.878 0.144 ;
    END
  END di[4]
  PIN di[500]
    DIRECTION INPUT ;
    USE SIGNAL ;
    PORT
      LAYER M3 ;
        RECT  65.556 0 65.574 0.144 ;
    END
  END di[500]
  PIN di[501]
    DIRECTION INPUT ;
    USE SIGNAL ;
    PORT
      LAYER M5 ;
        RECT  65.664 0 65.688 0.192 ;
    END
  END di[501]
  PIN di[502]
    DIRECTION INPUT ;
    USE SIGNAL ;
    PORT
      LAYER M3 ;
        RECT  65.772 0 65.79 0.144 ;
    END
  END di[502]
  PIN di[503]
    DIRECTION INPUT ;
    USE SIGNAL ;
    PORT
      LAYER M5 ;
        RECT  65.904 0 65.928 0.192 ;
    END
  END di[503]
  PIN di[504]
    DIRECTION INPUT ;
    USE SIGNAL ;
    PORT
      LAYER M3 ;
        RECT  66.024 0 66.042 0.144 ;
    END
  END di[504]
  PIN di[505]
    DIRECTION INPUT ;
    USE SIGNAL ;
    PORT
      LAYER M5 ;
        RECT  66.144 0 66.168 0.192 ;
    END
  END di[505]
  PIN di[506]
    DIRECTION INPUT ;
    USE SIGNAL ;
    PORT
      LAYER M3 ;
        RECT  66.276 0 66.294 0.144 ;
    END
  END di[506]
  PIN di[507]
    DIRECTION INPUT ;
    USE SIGNAL ;
    PORT
      LAYER M5 ;
        RECT  66.384 0 66.408 0.192 ;
    END
  END di[507]
  PIN di[508]
    DIRECTION INPUT ;
    USE SIGNAL ;
    PORT
      LAYER M3 ;
        RECT  66.528 0 66.546 0.144 ;
    END
  END di[508]
  PIN di[509]
    DIRECTION INPUT ;
    USE SIGNAL ;
    PORT
      LAYER M5 ;
        RECT  66.624 0 66.648 0.192 ;
    END
  END di[509]
  PIN di[50]
    DIRECTION INPUT ;
    USE SIGNAL ;
    PORT
      LAYER M3 ;
        RECT  10.476 0 10.494 0.144 ;
    END
  END di[50]
  PIN di[510]
    DIRECTION INPUT ;
    USE SIGNAL ;
    PORT
      LAYER M3 ;
        RECT  66.78 0 66.798 0.144 ;
    END
  END di[510]
  PIN di[511]
    DIRECTION INPUT ;
    USE SIGNAL ;
    PORT
      LAYER M5 ;
        RECT  66.864 0 66.888 0.192 ;
    END
  END di[511]
  PIN di[51]
    DIRECTION INPUT ;
    USE SIGNAL ;
    PORT
      LAYER M5 ;
        RECT  10.608 0 10.632 0.192 ;
    END
  END di[51]
  PIN di[52]
    DIRECTION INPUT ;
    USE SIGNAL ;
    PORT
      LAYER M3 ;
        RECT  10.728 0 10.746 0.144 ;
    END
  END di[52]
  PIN di[53]
    DIRECTION INPUT ;
    USE SIGNAL ;
    PORT
      LAYER M5 ;
        RECT  10.848 0 10.872 0.192 ;
    END
  END di[53]
  PIN di[54]
    DIRECTION INPUT ;
    USE SIGNAL ;
    PORT
      LAYER M3 ;
        RECT  10.98 0 10.998 0.144 ;
    END
  END di[54]
  PIN di[55]
    DIRECTION INPUT ;
    USE SIGNAL ;
    PORT
      LAYER M5 ;
        RECT  11.088 0 11.112 0.192 ;
    END
  END di[55]
  PIN di[56]
    DIRECTION INPUT ;
    USE SIGNAL ;
    PORT
      LAYER M3 ;
        RECT  11.232 0 11.25 0.144 ;
    END
  END di[56]
  PIN di[57]
    DIRECTION INPUT ;
    USE SIGNAL ;
    PORT
      LAYER M5 ;
        RECT  11.328 0 11.352 0.192 ;
    END
  END di[57]
  PIN di[58]
    DIRECTION INPUT ;
    USE SIGNAL ;
    PORT
      LAYER M3 ;
        RECT  11.484 0 11.502 0.144 ;
    END
  END di[58]
  PIN di[59]
    DIRECTION INPUT ;
    USE SIGNAL ;
    PORT
      LAYER M5 ;
        RECT  11.568 0 11.592 0.192 ;
    END
  END di[59]
  PIN di[5]
    DIRECTION INPUT ;
    USE SIGNAL ;
    PORT
      LAYER M5 ;
        RECT  4.992 0 5.016 0.192 ;
    END
  END di[5]
  PIN di[60]
    DIRECTION INPUT ;
    USE SIGNAL ;
    PORT
      LAYER M3 ;
        RECT  11.7 0 11.718 0.144 ;
    END
  END di[60]
  PIN di[61]
    DIRECTION INPUT ;
    USE SIGNAL ;
    PORT
      LAYER M5 ;
        RECT  11.856 0 11.88 0.192 ;
    END
  END di[61]
  PIN di[62]
    DIRECTION INPUT ;
    USE SIGNAL ;
    PORT
      LAYER M3 ;
        RECT  11.952 0 11.97 0.144 ;
    END
  END di[62]
  PIN di[63]
    DIRECTION INPUT ;
    USE SIGNAL ;
    PORT
      LAYER M5 ;
        RECT  12.096 0 12.12 0.192 ;
    END
  END di[63]
  PIN di[64]
    DIRECTION INPUT ;
    USE SIGNAL ;
    PORT
      LAYER M3 ;
        RECT  12.204 0 12.222 0.144 ;
    END
  END di[64]
  PIN di[65]
    DIRECTION INPUT ;
    USE SIGNAL ;
    PORT
      LAYER M5 ;
        RECT  12.336 0 12.36 0.192 ;
    END
  END di[65]
  PIN di[66]
    DIRECTION INPUT ;
    USE SIGNAL ;
    PORT
      LAYER M3 ;
        RECT  12.456 0 12.474 0.144 ;
    END
  END di[66]
  PIN di[67]
    DIRECTION INPUT ;
    USE SIGNAL ;
    PORT
      LAYER M5 ;
        RECT  12.576 0 12.6 0.192 ;
    END
  END di[67]
  PIN di[68]
    DIRECTION INPUT ;
    USE SIGNAL ;
    PORT
      LAYER M3 ;
        RECT  12.708 0 12.726 0.144 ;
    END
  END di[68]
  PIN di[69]
    DIRECTION INPUT ;
    USE SIGNAL ;
    PORT
      LAYER M5 ;
        RECT  12.816 0 12.84 0.192 ;
    END
  END di[69]
  PIN di[6]
    DIRECTION INPUT ;
    USE SIGNAL ;
    PORT
      LAYER M3 ;
        RECT  5.112 0 5.13 0.144 ;
    END
  END di[6]
  PIN di[70]
    DIRECTION INPUT ;
    USE SIGNAL ;
    PORT
      LAYER M3 ;
        RECT  12.924 0 12.942 0.144 ;
    END
  END di[70]
  PIN di[71]
    DIRECTION INPUT ;
    USE SIGNAL ;
    PORT
      LAYER M5 ;
        RECT  13.056 0 13.08 0.192 ;
    END
  END di[71]
  PIN di[72]
    DIRECTION INPUT ;
    USE SIGNAL ;
    PORT
      LAYER M3 ;
        RECT  13.176 0 13.194 0.144 ;
    END
  END di[72]
  PIN di[73]
    DIRECTION INPUT ;
    USE SIGNAL ;
    PORT
      LAYER M5 ;
        RECT  13.296 0 13.32 0.192 ;
    END
  END di[73]
  PIN di[74]
    DIRECTION INPUT ;
    USE SIGNAL ;
    PORT
      LAYER M3 ;
        RECT  13.428 0 13.446 0.144 ;
    END
  END di[74]
  PIN di[75]
    DIRECTION INPUT ;
    USE SIGNAL ;
    PORT
      LAYER M5 ;
        RECT  13.536 0 13.56 0.192 ;
    END
  END di[75]
  PIN di[76]
    DIRECTION INPUT ;
    USE SIGNAL ;
    PORT
      LAYER M3 ;
        RECT  13.68 0 13.698 0.144 ;
    END
  END di[76]
  PIN di[77]
    DIRECTION INPUT ;
    USE SIGNAL ;
    PORT
      LAYER M5 ;
        RECT  13.776 0 13.8 0.192 ;
    END
  END di[77]
  PIN di[78]
    DIRECTION INPUT ;
    USE SIGNAL ;
    PORT
      LAYER M3 ;
        RECT  13.932 0 13.95 0.144 ;
    END
  END di[78]
  PIN di[79]
    DIRECTION INPUT ;
    USE SIGNAL ;
    PORT
      LAYER M5 ;
        RECT  14.016 0 14.04 0.192 ;
    END
  END di[79]
  PIN di[7]
    DIRECTION INPUT ;
    USE SIGNAL ;
    PORT
      LAYER M5 ;
        RECT  5.232 0 5.256 0.192 ;
    END
  END di[7]
  PIN di[80]
    DIRECTION INPUT ;
    USE SIGNAL ;
    PORT
      LAYER M3 ;
        RECT  14.148 0 14.166 0.144 ;
    END
  END di[80]
  PIN di[81]
    DIRECTION INPUT ;
    USE SIGNAL ;
    PORT
      LAYER M5 ;
        RECT  14.256 0 14.28 0.192 ;
    END
  END di[81]
  PIN di[82]
    DIRECTION INPUT ;
    USE SIGNAL ;
    PORT
      LAYER M3 ;
        RECT  14.4 0 14.418 0.144 ;
    END
  END di[82]
  PIN di[83]
    DIRECTION INPUT ;
    USE SIGNAL ;
    PORT
      LAYER M5 ;
        RECT  14.544 0 14.568 0.192 ;
    END
  END di[83]
  PIN di[84]
    DIRECTION INPUT ;
    USE SIGNAL ;
    PORT
      LAYER M3 ;
        RECT  14.652 0 14.67 0.144 ;
    END
  END di[84]
  PIN di[85]
    DIRECTION INPUT ;
    USE SIGNAL ;
    PORT
      LAYER M5 ;
        RECT  14.784 0 14.808 0.192 ;
    END
  END di[85]
  PIN di[86]
    DIRECTION INPUT ;
    USE SIGNAL ;
    PORT
      LAYER M3 ;
        RECT  14.904 0 14.922 0.144 ;
    END
  END di[86]
  PIN di[87]
    DIRECTION INPUT ;
    USE SIGNAL ;
    PORT
      LAYER M5 ;
        RECT  15.024 0 15.048 0.192 ;
    END
  END di[87]
  PIN di[88]
    DIRECTION INPUT ;
    USE SIGNAL ;
    PORT
      LAYER M3 ;
        RECT  15.156 0 15.174 0.144 ;
    END
  END di[88]
  PIN di[89]
    DIRECTION INPUT ;
    USE SIGNAL ;
    PORT
      LAYER M5 ;
        RECT  15.264 0 15.288 0.192 ;
    END
  END di[89]
  PIN di[8]
    DIRECTION INPUT ;
    USE SIGNAL ;
    PORT
      LAYER M3 ;
        RECT  5.364 0 5.382 0.144 ;
    END
  END di[8]
  PIN di[90]
    DIRECTION INPUT ;
    USE SIGNAL ;
    PORT
      LAYER M3 ;
        RECT  15.372 0 15.39 0.144 ;
    END
  END di[90]
  PIN di[91]
    DIRECTION INPUT ;
    USE SIGNAL ;
    PORT
      LAYER M5 ;
        RECT  15.504 0 15.528 0.192 ;
    END
  END di[91]
  PIN di[92]
    DIRECTION INPUT ;
    USE SIGNAL ;
    PORT
      LAYER M3 ;
        RECT  15.624 0 15.642 0.144 ;
    END
  END di[92]
  PIN di[93]
    DIRECTION INPUT ;
    USE SIGNAL ;
    PORT
      LAYER M5 ;
        RECT  15.744 0 15.768 0.192 ;
    END
  END di[93]
  PIN di[94]
    DIRECTION INPUT ;
    USE SIGNAL ;
    PORT
      LAYER M3 ;
        RECT  15.876 0 15.894 0.144 ;
    END
  END di[94]
  PIN di[95]
    DIRECTION INPUT ;
    USE SIGNAL ;
    PORT
      LAYER M5 ;
        RECT  15.984 0 16.008 0.192 ;
    END
  END di[95]
  PIN di[96]
    DIRECTION INPUT ;
    USE SIGNAL ;
    PORT
      LAYER M3 ;
        RECT  16.128 0 16.146 0.144 ;
    END
  END di[96]
  PIN di[97]
    DIRECTION INPUT ;
    USE SIGNAL ;
    PORT
      LAYER M5 ;
        RECT  16.224 0 16.248 0.192 ;
    END
  END di[97]
  PIN di[98]
    DIRECTION INPUT ;
    USE SIGNAL ;
    PORT
      LAYER M3 ;
        RECT  16.344 0 16.362 0.144 ;
    END
  END di[98]
  PIN di[99]
    DIRECTION INPUT ;
    USE SIGNAL ;
    PORT
      LAYER M5 ;
        RECT  16.464 0 16.488 0.192 ;
    END
  END di[99]
  PIN di[9]
    DIRECTION INPUT ;
    USE SIGNAL ;
    PORT
      LAYER M5 ;
        RECT  5.472 0 5.496 0.192 ;
    END
  END di[9]
  PIN dq[0]
    DIRECTION OUTPUT ;
    USE SIGNAL ;
    PORT
      LAYER M3 ;
        RECT  4.356 36.576 4.374 36.72 ;
    END
  END dq[0]
  PIN dq[100]
    DIRECTION OUTPUT ;
    USE SIGNAL ;
    PORT
      LAYER M3 ;
        RECT  16.596 36.576 16.614 36.72 ;
    END
  END dq[100]
  PIN dq[101]
    DIRECTION OUTPUT ;
    USE SIGNAL ;
    PORT
      LAYER M5 ;
        RECT  16.704 36.528 16.728 36.72 ;
    END
  END dq[101]
  PIN dq[102]
    DIRECTION OUTPUT ;
    USE SIGNAL ;
    PORT
      LAYER M3 ;
        RECT  16.848 36.576 16.866 36.72 ;
    END
  END dq[102]
  PIN dq[103]
    DIRECTION OUTPUT ;
    USE SIGNAL ;
    PORT
      LAYER M5 ;
        RECT  16.992 36.528 17.016 36.72 ;
    END
  END dq[103]
  PIN dq[104]
    DIRECTION OUTPUT ;
    USE SIGNAL ;
    PORT
      LAYER M3 ;
        RECT  17.1 36.576 17.118 36.72 ;
    END
  END dq[104]
  PIN dq[105]
    DIRECTION OUTPUT ;
    USE SIGNAL ;
    PORT
      LAYER M5 ;
        RECT  17.232 36.528 17.256 36.72 ;
    END
  END dq[105]
  PIN dq[106]
    DIRECTION OUTPUT ;
    USE SIGNAL ;
    PORT
      LAYER M3 ;
        RECT  17.352 36.576 17.37 36.72 ;
    END
  END dq[106]
  PIN dq[107]
    DIRECTION OUTPUT ;
    USE SIGNAL ;
    PORT
      LAYER M5 ;
        RECT  17.472 36.528 17.496 36.72 ;
    END
  END dq[107]
  PIN dq[108]
    DIRECTION OUTPUT ;
    USE SIGNAL ;
    PORT
      LAYER M3 ;
        RECT  17.568 36.576 17.586 36.72 ;
    END
  END dq[108]
  PIN dq[109]
    DIRECTION OUTPUT ;
    USE SIGNAL ;
    PORT
      LAYER M5 ;
        RECT  17.712 36.528 17.736 36.72 ;
    END
  END dq[109]
  PIN dq[10]
    DIRECTION OUTPUT ;
    USE SIGNAL ;
    PORT
      LAYER M3 ;
        RECT  5.58 36.576 5.598 36.72 ;
    END
  END dq[10]
  PIN dq[110]
    DIRECTION OUTPUT ;
    USE SIGNAL ;
    PORT
      LAYER M3 ;
        RECT  17.82 36.576 17.838 36.72 ;
    END
  END dq[110]
  PIN dq[111]
    DIRECTION OUTPUT ;
    USE SIGNAL ;
    PORT
      LAYER M5 ;
        RECT  17.952 36.528 17.976 36.72 ;
    END
  END dq[111]
  PIN dq[112]
    DIRECTION OUTPUT ;
    USE SIGNAL ;
    PORT
      LAYER M3 ;
        RECT  18.072 36.576 18.09 36.72 ;
    END
  END dq[112]
  PIN dq[113]
    DIRECTION OUTPUT ;
    USE SIGNAL ;
    PORT
      LAYER M5 ;
        RECT  18.192 36.528 18.216 36.72 ;
    END
  END dq[113]
  PIN dq[114]
    DIRECTION OUTPUT ;
    USE SIGNAL ;
    PORT
      LAYER M3 ;
        RECT  18.324 36.576 18.342 36.72 ;
    END
  END dq[114]
  PIN dq[115]
    DIRECTION OUTPUT ;
    USE SIGNAL ;
    PORT
      LAYER M5 ;
        RECT  18.432 36.528 18.456 36.72 ;
    END
  END dq[115]
  PIN dq[116]
    DIRECTION OUTPUT ;
    USE SIGNAL ;
    PORT
      LAYER M3 ;
        RECT  18.576 36.576 18.594 36.72 ;
    END
  END dq[116]
  PIN dq[117]
    DIRECTION OUTPUT ;
    USE SIGNAL ;
    PORT
      LAYER M5 ;
        RECT  18.672 36.528 18.696 36.72 ;
    END
  END dq[117]
  PIN dq[118]
    DIRECTION OUTPUT ;
    USE SIGNAL ;
    PORT
      LAYER M3 ;
        RECT  18.792 36.576 18.81 36.72 ;
    END
  END dq[118]
  PIN dq[119]
    DIRECTION OUTPUT ;
    USE SIGNAL ;
    PORT
      LAYER M5 ;
        RECT  18.912 36.528 18.936 36.72 ;
    END
  END dq[119]
  PIN dq[11]
    DIRECTION OUTPUT ;
    USE SIGNAL ;
    PORT
      LAYER M5 ;
        RECT  5.712 36.528 5.736 36.72 ;
    END
  END dq[11]
  PIN dq[120]
    DIRECTION OUTPUT ;
    USE SIGNAL ;
    PORT
      LAYER M3 ;
        RECT  19.044 36.576 19.062 36.72 ;
    END
  END dq[120]
  PIN dq[121]
    DIRECTION OUTPUT ;
    USE SIGNAL ;
    PORT
      LAYER M5 ;
        RECT  19.152 36.528 19.176 36.72 ;
    END
  END dq[121]
  PIN dq[122]
    DIRECTION OUTPUT ;
    USE SIGNAL ;
    PORT
      LAYER M3 ;
        RECT  19.296 36.576 19.314 36.72 ;
    END
  END dq[122]
  PIN dq[123]
    DIRECTION OUTPUT ;
    USE SIGNAL ;
    PORT
      LAYER M5 ;
        RECT  19.44 36.528 19.464 36.72 ;
    END
  END dq[123]
  PIN dq[124]
    DIRECTION OUTPUT ;
    USE SIGNAL ;
    PORT
      LAYER M3 ;
        RECT  19.548 36.576 19.566 36.72 ;
    END
  END dq[124]
  PIN dq[125]
    DIRECTION OUTPUT ;
    USE SIGNAL ;
    PORT
      LAYER M5 ;
        RECT  19.68 36.528 19.704 36.72 ;
    END
  END dq[125]
  PIN dq[126]
    DIRECTION OUTPUT ;
    USE SIGNAL ;
    PORT
      LAYER M3 ;
        RECT  19.8 36.576 19.818 36.72 ;
    END
  END dq[126]
  PIN dq[127]
    DIRECTION OUTPUT ;
    USE SIGNAL ;
    PORT
      LAYER M5 ;
        RECT  19.92 36.528 19.944 36.72 ;
    END
  END dq[127]
  PIN dq[128]
    DIRECTION OUTPUT ;
    USE SIGNAL ;
    PORT
      LAYER M3 ;
        RECT  20.016 36.576 20.034 36.72 ;
    END
  END dq[128]
  PIN dq[129]
    DIRECTION OUTPUT ;
    USE SIGNAL ;
    PORT
      LAYER M5 ;
        RECT  20.16 36.528 20.184 36.72 ;
    END
  END dq[129]
  PIN dq[12]
    DIRECTION OUTPUT ;
    USE SIGNAL ;
    PORT
      LAYER M3 ;
        RECT  5.832 36.576 5.85 36.72 ;
    END
  END dq[12]
  PIN dq[130]
    DIRECTION OUTPUT ;
    USE SIGNAL ;
    PORT
      LAYER M3 ;
        RECT  20.268 36.576 20.286 36.72 ;
    END
  END dq[130]
  PIN dq[131]
    DIRECTION OUTPUT ;
    USE SIGNAL ;
    PORT
      LAYER M5 ;
        RECT  20.4 36.528 20.424 36.72 ;
    END
  END dq[131]
  PIN dq[132]
    DIRECTION OUTPUT ;
    USE SIGNAL ;
    PORT
      LAYER M3 ;
        RECT  20.52 36.576 20.538 36.72 ;
    END
  END dq[132]
  PIN dq[133]
    DIRECTION OUTPUT ;
    USE SIGNAL ;
    PORT
      LAYER M5 ;
        RECT  20.64 36.528 20.664 36.72 ;
    END
  END dq[133]
  PIN dq[134]
    DIRECTION OUTPUT ;
    USE SIGNAL ;
    PORT
      LAYER M3 ;
        RECT  20.772 36.576 20.79 36.72 ;
    END
  END dq[134]
  PIN dq[135]
    DIRECTION OUTPUT ;
    USE SIGNAL ;
    PORT
      LAYER M5 ;
        RECT  20.88 36.528 20.904 36.72 ;
    END
  END dq[135]
  PIN dq[136]
    DIRECTION OUTPUT ;
    USE SIGNAL ;
    PORT
      LAYER M3 ;
        RECT  21.024 36.576 21.042 36.72 ;
    END
  END dq[136]
  PIN dq[137]
    DIRECTION OUTPUT ;
    USE SIGNAL ;
    PORT
      LAYER M5 ;
        RECT  21.12 36.528 21.144 36.72 ;
    END
  END dq[137]
  PIN dq[138]
    DIRECTION OUTPUT ;
    USE SIGNAL ;
    PORT
      LAYER M3 ;
        RECT  21.24 36.576 21.258 36.72 ;
    END
  END dq[138]
  PIN dq[139]
    DIRECTION OUTPUT ;
    USE SIGNAL ;
    PORT
      LAYER M5 ;
        RECT  21.36 36.528 21.384 36.72 ;
    END
  END dq[139]
  PIN dq[13]
    DIRECTION OUTPUT ;
    USE SIGNAL ;
    PORT
      LAYER M5 ;
        RECT  5.952 36.528 5.976 36.72 ;
    END
  END dq[13]
  PIN dq[140]
    DIRECTION OUTPUT ;
    USE SIGNAL ;
    PORT
      LAYER M3 ;
        RECT  21.492 36.576 21.51 36.72 ;
    END
    PORT
      LAYER M3 ;
        RECT  21.456 36.588 21.582 36.653 ;
    END
  END dq[140]
  PIN dq[141]
    DIRECTION OUTPUT ;
    USE SIGNAL ;
    PORT
      LAYER M5 ;
        RECT  21.6 36.528 21.624 36.72 ;
    END
  END dq[141]
  PIN dq[142]
    DIRECTION OUTPUT ;
    USE SIGNAL ;
    PORT
      LAYER M3 ;
        RECT  21.744 36.576 21.762 36.72 ;
    END
  END dq[142]
  PIN dq[143]
    DIRECTION OUTPUT ;
    USE SIGNAL ;
    PORT
      LAYER M5 ;
        RECT  21.888 36.528 21.912 36.72 ;
    END
  END dq[143]
  PIN dq[144]
    DIRECTION OUTPUT ;
    USE SIGNAL ;
    PORT
      LAYER M3 ;
        RECT  21.996 36.576 22.014 36.72 ;
    END
  END dq[144]
  PIN dq[145]
    DIRECTION OUTPUT ;
    USE SIGNAL ;
    PORT
      LAYER M5 ;
        RECT  22.128 36.528 22.152 36.72 ;
    END
  END dq[145]
  PIN dq[146]
    DIRECTION OUTPUT ;
    USE SIGNAL ;
    PORT
      LAYER M3 ;
        RECT  22.248 36.576 22.266 36.72 ;
    END
  END dq[146]
  PIN dq[147]
    DIRECTION OUTPUT ;
    USE SIGNAL ;
    PORT
      LAYER M5 ;
        RECT  22.368 36.528 22.392 36.72 ;
    END
  END dq[147]
  PIN dq[148]
    DIRECTION OUTPUT ;
    USE SIGNAL ;
    PORT
      LAYER M3 ;
        RECT  22.464 36.576 22.482 36.72 ;
    END
  END dq[148]
  PIN dq[149]
    DIRECTION OUTPUT ;
    USE SIGNAL ;
    PORT
      LAYER M5 ;
        RECT  22.608 36.528 22.632 36.72 ;
    END
  END dq[149]
  PIN dq[14]
    DIRECTION OUTPUT ;
    USE SIGNAL ;
    PORT
      LAYER M3 ;
        RECT  6.084 36.576 6.102 36.72 ;
    END
  END dq[14]
  PIN dq[150]
    DIRECTION OUTPUT ;
    USE SIGNAL ;
    PORT
      LAYER M3 ;
        RECT  22.716 36.576 22.734 36.72 ;
    END
  END dq[150]
  PIN dq[151]
    DIRECTION OUTPUT ;
    USE SIGNAL ;
    PORT
      LAYER M5 ;
        RECT  22.848 36.528 22.872 36.72 ;
    END
  END dq[151]
  PIN dq[152]
    DIRECTION OUTPUT ;
    USE SIGNAL ;
    PORT
      LAYER M3 ;
        RECT  22.968 36.576 22.986 36.72 ;
    END
  END dq[152]
  PIN dq[153]
    DIRECTION OUTPUT ;
    USE SIGNAL ;
    PORT
      LAYER M5 ;
        RECT  23.088 36.528 23.112 36.72 ;
    END
  END dq[153]
  PIN dq[154]
    DIRECTION OUTPUT ;
    USE SIGNAL ;
    PORT
      LAYER M3 ;
        RECT  23.22 36.576 23.238 36.72 ;
    END
  END dq[154]
  PIN dq[155]
    DIRECTION OUTPUT ;
    USE SIGNAL ;
    PORT
      LAYER M5 ;
        RECT  23.328 36.528 23.352 36.72 ;
    END
  END dq[155]
  PIN dq[156]
    DIRECTION OUTPUT ;
    USE SIGNAL ;
    PORT
      LAYER M3 ;
        RECT  23.472 36.576 23.49 36.72 ;
    END
  END dq[156]
  PIN dq[157]
    DIRECTION OUTPUT ;
    USE SIGNAL ;
    PORT
      LAYER M5 ;
        RECT  23.568 36.528 23.592 36.72 ;
    END
  END dq[157]
  PIN dq[158]
    DIRECTION OUTPUT ;
    USE SIGNAL ;
    PORT
      LAYER M3 ;
        RECT  23.688 36.576 23.706 36.72 ;
    END
  END dq[158]
  PIN dq[159]
    DIRECTION OUTPUT ;
    USE SIGNAL ;
    PORT
      LAYER M5 ;
        RECT  23.808 36.528 23.832 36.72 ;
    END
  END dq[159]
  PIN dq[15]
    DIRECTION OUTPUT ;
    USE SIGNAL ;
    PORT
      LAYER M5 ;
        RECT  6.192 36.528 6.216 36.72 ;
    END
  END dq[15]
  PIN dq[160]
    DIRECTION OUTPUT ;
    USE SIGNAL ;
    PORT
      LAYER M3 ;
        RECT  23.94 36.576 23.958 36.72 ;
    END
  END dq[160]
  PIN dq[161]
    DIRECTION OUTPUT ;
    USE SIGNAL ;
    PORT
      LAYER M5 ;
        RECT  24.048 36.528 24.072 36.72 ;
    END
  END dq[161]
  PIN dq[162]
    DIRECTION OUTPUT ;
    USE SIGNAL ;
    PORT
      LAYER M3 ;
        RECT  24.192 36.576 24.21 36.72 ;
    END
  END dq[162]
  PIN dq[163]
    DIRECTION OUTPUT ;
    USE SIGNAL ;
    PORT
      LAYER M5 ;
        RECT  24.288 36.528 24.312 36.72 ;
    END
  END dq[163]
  PIN dq[164]
    DIRECTION OUTPUT ;
    USE SIGNAL ;
    PORT
      LAYER M3 ;
        RECT  24.444 36.576 24.462 36.72 ;
    END
  END dq[164]
  PIN dq[165]
    DIRECTION OUTPUT ;
    USE SIGNAL ;
    PORT
      LAYER M5 ;
        RECT  24.576 36.528 24.6 36.72 ;
    END
  END dq[165]
  PIN dq[166]
    DIRECTION OUTPUT ;
    USE SIGNAL ;
    PORT
      LAYER M3 ;
        RECT  24.696 36.576 24.714 36.72 ;
    END
  END dq[166]
  PIN dq[167]
    DIRECTION OUTPUT ;
    USE SIGNAL ;
    PORT
      LAYER M5 ;
        RECT  24.816 36.528 24.84 36.72 ;
    END
  END dq[167]
  PIN dq[168]
    DIRECTION OUTPUT ;
    USE SIGNAL ;
    PORT
      LAYER M3 ;
        RECT  24.912 36.576 24.93 36.72 ;
    END
  END dq[168]
  PIN dq[169]
    DIRECTION OUTPUT ;
    USE SIGNAL ;
    PORT
      LAYER M5 ;
        RECT  25.056 36.528 25.08 36.72 ;
    END
  END dq[169]
  PIN dq[16]
    DIRECTION OUTPUT ;
    USE SIGNAL ;
    PORT
      LAYER M3 ;
        RECT  6.336 36.576 6.354 36.72 ;
    END
  END dq[16]
  PIN dq[170]
    DIRECTION OUTPUT ;
    USE SIGNAL ;
    PORT
      LAYER M3 ;
        RECT  25.164 36.576 25.182 36.72 ;
    END
  END dq[170]
  PIN dq[171]
    DIRECTION OUTPUT ;
    USE SIGNAL ;
    PORT
      LAYER M5 ;
        RECT  25.296 36.528 25.32 36.72 ;
    END
  END dq[171]
  PIN dq[172]
    DIRECTION OUTPUT ;
    USE SIGNAL ;
    PORT
      LAYER M3 ;
        RECT  25.416 36.576 25.434 36.72 ;
    END
  END dq[172]
  PIN dq[173]
    DIRECTION OUTPUT ;
    USE SIGNAL ;
    PORT
      LAYER M5 ;
        RECT  25.536 36.528 25.56 36.72 ;
    END
  END dq[173]
  PIN dq[174]
    DIRECTION OUTPUT ;
    USE SIGNAL ;
    PORT
      LAYER M3 ;
        RECT  25.668 36.576 25.686 36.72 ;
    END
  END dq[174]
  PIN dq[175]
    DIRECTION OUTPUT ;
    USE SIGNAL ;
    PORT
      LAYER M5 ;
        RECT  25.776 36.528 25.8 36.72 ;
    END
  END dq[175]
  PIN dq[176]
    DIRECTION OUTPUT ;
    USE SIGNAL ;
    PORT
      LAYER M3 ;
        RECT  25.92 36.576 25.938 36.72 ;
    END
  END dq[176]
  PIN dq[177]
    DIRECTION OUTPUT ;
    USE SIGNAL ;
    PORT
      LAYER M5 ;
        RECT  26.016 36.528 26.04 36.72 ;
    END
  END dq[177]
  PIN dq[178]
    DIRECTION OUTPUT ;
    USE SIGNAL ;
    PORT
      LAYER M3 ;
        RECT  26.136 36.576 26.154 36.72 ;
    END
  END dq[178]
  PIN dq[179]
    DIRECTION OUTPUT ;
    USE SIGNAL ;
    PORT
      LAYER M5 ;
        RECT  26.256 36.528 26.28 36.72 ;
    END
  END dq[179]
  PIN dq[17]
    DIRECTION OUTPUT ;
    USE SIGNAL ;
    PORT
      LAYER M5 ;
        RECT  6.432 36.528 6.456 36.72 ;
    END
  END dq[17]
  PIN dq[180]
    DIRECTION OUTPUT ;
    USE SIGNAL ;
    PORT
      LAYER M3 ;
        RECT  26.388 36.576 26.406 36.72 ;
    END
  END dq[180]
  PIN dq[181]
    DIRECTION OUTPUT ;
    USE SIGNAL ;
    PORT
      LAYER M5 ;
        RECT  26.496 36.528 26.52 36.72 ;
    END
  END dq[181]
  PIN dq[182]
    DIRECTION OUTPUT ;
    USE SIGNAL ;
    PORT
      LAYER M3 ;
        RECT  26.64 36.576 26.658 36.72 ;
    END
  END dq[182]
  PIN dq[183]
    DIRECTION OUTPUT ;
    USE SIGNAL ;
    PORT
      LAYER M5 ;
        RECT  26.736 36.528 26.76 36.72 ;
    END
  END dq[183]
  PIN dq[184]
    DIRECTION OUTPUT ;
    USE SIGNAL ;
    PORT
      LAYER M3 ;
        RECT  26.892 36.576 26.91 36.72 ;
    END
  END dq[184]
  PIN dq[185]
    DIRECTION OUTPUT ;
    USE SIGNAL ;
    PORT
      LAYER M5 ;
        RECT  27.024 36.528 27.048 36.72 ;
    END
  END dq[185]
  PIN dq[186]
    DIRECTION OUTPUT ;
    USE SIGNAL ;
    PORT
      LAYER M3 ;
        RECT  27.144 36.576 27.162 36.72 ;
    END
  END dq[186]
  PIN dq[187]
    DIRECTION OUTPUT ;
    USE SIGNAL ;
    PORT
      LAYER M5 ;
        RECT  27.264 36.528 27.288 36.72 ;
    END
  END dq[187]
  PIN dq[188]
    DIRECTION OUTPUT ;
    USE SIGNAL ;
    PORT
      LAYER M3 ;
        RECT  27.36 36.576 27.378 36.72 ;
    END
  END dq[188]
  PIN dq[189]
    DIRECTION OUTPUT ;
    USE SIGNAL ;
    PORT
      LAYER M5 ;
        RECT  27.504 36.528 27.528 36.72 ;
    END
  END dq[189]
  PIN dq[18]
    DIRECTION OUTPUT ;
    USE SIGNAL ;
    PORT
      LAYER M3 ;
        RECT  6.588 36.576 6.606 36.72 ;
    END
  END dq[18]
  PIN dq[190]
    DIRECTION OUTPUT ;
    USE SIGNAL ;
    PORT
      LAYER M3 ;
        RECT  27.612 36.576 27.63 36.72 ;
    END
  END dq[190]
  PIN dq[191]
    DIRECTION OUTPUT ;
    USE SIGNAL ;
    PORT
      LAYER M5 ;
        RECT  27.744 36.528 27.768 36.72 ;
    END
  END dq[191]
  PIN dq[192]
    DIRECTION OUTPUT ;
    USE SIGNAL ;
    PORT
      LAYER M3 ;
        RECT  27.864 36.576 27.882 36.72 ;
    END
  END dq[192]
  PIN dq[193]
    DIRECTION OUTPUT ;
    USE SIGNAL ;
    PORT
      LAYER M5 ;
        RECT  27.984 36.528 28.008 36.72 ;
    END
  END dq[193]
  PIN dq[194]
    DIRECTION OUTPUT ;
    USE SIGNAL ;
    PORT
      LAYER M3 ;
        RECT  28.116 36.576 28.134 36.72 ;
    END
  END dq[194]
  PIN dq[195]
    DIRECTION OUTPUT ;
    USE SIGNAL ;
    PORT
      LAYER M5 ;
        RECT  28.224 36.528 28.248 36.72 ;
    END
  END dq[195]
  PIN dq[196]
    DIRECTION OUTPUT ;
    USE SIGNAL ;
    PORT
      LAYER M3 ;
        RECT  28.368 36.576 28.386 36.72 ;
    END
  END dq[196]
  PIN dq[197]
    DIRECTION OUTPUT ;
    USE SIGNAL ;
    PORT
      LAYER M5 ;
        RECT  28.464 36.528 28.488 36.72 ;
    END
  END dq[197]
  PIN dq[198]
    DIRECTION OUTPUT ;
    USE SIGNAL ;
    PORT
      LAYER M3 ;
        RECT  28.584 36.576 28.602 36.72 ;
    END
  END dq[198]
  PIN dq[199]
    DIRECTION OUTPUT ;
    USE SIGNAL ;
    PORT
      LAYER M5 ;
        RECT  28.704 36.528 28.728 36.72 ;
    END
  END dq[199]
  PIN dq[19]
    DIRECTION OUTPUT ;
    USE SIGNAL ;
    PORT
      LAYER M5 ;
        RECT  6.672 36.528 6.696 36.72 ;
    END
  END dq[19]
  PIN dq[1]
    DIRECTION OUTPUT ;
    USE SIGNAL ;
    PORT
      LAYER M5 ;
        RECT  4.512 36.528 4.536 36.72 ;
    END
  END dq[1]
  PIN dq[200]
    DIRECTION OUTPUT ;
    USE SIGNAL ;
    PORT
      LAYER M3 ;
        RECT  28.836 36.576 28.854 36.72 ;
    END
  END dq[200]
  PIN dq[201]
    DIRECTION OUTPUT ;
    USE SIGNAL ;
    PORT
      LAYER M5 ;
        RECT  28.944 36.528 28.968 36.72 ;
    END
  END dq[201]
  PIN dq[202]
    DIRECTION OUTPUT ;
    USE SIGNAL ;
    PORT
      LAYER M3 ;
        RECT  29.088 36.576 29.106 36.72 ;
    END
  END dq[202]
  PIN dq[203]
    DIRECTION OUTPUT ;
    USE SIGNAL ;
    PORT
      LAYER M5 ;
        RECT  29.184 36.528 29.208 36.72 ;
    END
  END dq[203]
  PIN dq[204]
    DIRECTION OUTPUT ;
    USE SIGNAL ;
    PORT
      LAYER M3 ;
        RECT  29.34 36.576 29.358 36.72 ;
    END
  END dq[204]
  PIN dq[205]
    DIRECTION OUTPUT ;
    USE SIGNAL ;
    PORT
      LAYER M5 ;
        RECT  29.472 36.528 29.496 36.72 ;
    END
  END dq[205]
  PIN dq[206]
    DIRECTION OUTPUT ;
    USE SIGNAL ;
    PORT
      LAYER M3 ;
        RECT  29.592 36.576 29.61 36.72 ;
    END
  END dq[206]
  PIN dq[207]
    DIRECTION OUTPUT ;
    USE SIGNAL ;
    PORT
      LAYER M5 ;
        RECT  29.712 36.528 29.736 36.72 ;
    END
  END dq[207]
  PIN dq[208]
    DIRECTION OUTPUT ;
    USE SIGNAL ;
    PORT
      LAYER M3 ;
        RECT  29.808 36.576 29.826 36.72 ;
    END
  END dq[208]
  PIN dq[209]
    DIRECTION OUTPUT ;
    USE SIGNAL ;
    PORT
      LAYER M5 ;
        RECT  29.952 36.528 29.976 36.72 ;
    END
  END dq[209]
  PIN dq[20]
    DIRECTION OUTPUT ;
    USE SIGNAL ;
    PORT
      LAYER M3 ;
        RECT  6.804 36.576 6.822 36.72 ;
    END
  END dq[20]
  PIN dq[210]
    DIRECTION OUTPUT ;
    USE SIGNAL ;
    PORT
      LAYER M3 ;
        RECT  30.06 36.576 30.078 36.72 ;
    END
  END dq[210]
  PIN dq[211]
    DIRECTION OUTPUT ;
    USE SIGNAL ;
    PORT
      LAYER M5 ;
        RECT  30.192 36.528 30.216 36.72 ;
    END
  END dq[211]
  PIN dq[212]
    DIRECTION OUTPUT ;
    USE SIGNAL ;
    PORT
      LAYER M3 ;
        RECT  30.312 36.576 30.33 36.72 ;
    END
  END dq[212]
  PIN dq[213]
    DIRECTION OUTPUT ;
    USE SIGNAL ;
    PORT
      LAYER M5 ;
        RECT  30.432 36.528 30.456 36.72 ;
    END
  END dq[213]
  PIN dq[214]
    DIRECTION OUTPUT ;
    USE SIGNAL ;
    PORT
      LAYER M3 ;
        RECT  30.564 36.576 30.582 36.72 ;
    END
  END dq[214]
  PIN dq[215]
    DIRECTION OUTPUT ;
    USE SIGNAL ;
    PORT
      LAYER M5 ;
        RECT  30.672 36.528 30.696 36.72 ;
    END
  END dq[215]
  PIN dq[216]
    DIRECTION OUTPUT ;
    USE SIGNAL ;
    PORT
      LAYER M3 ;
        RECT  30.816 36.576 30.834 36.72 ;
    END
  END dq[216]
  PIN dq[217]
    DIRECTION OUTPUT ;
    USE SIGNAL ;
    PORT
      LAYER M5 ;
        RECT  30.912 36.528 30.936 36.72 ;
    END
  END dq[217]
  PIN dq[218]
    DIRECTION OUTPUT ;
    USE SIGNAL ;
    PORT
      LAYER M3 ;
        RECT  31.032 36.576 31.05 36.72 ;
    END
  END dq[218]
  PIN dq[219]
    DIRECTION OUTPUT ;
    USE SIGNAL ;
    PORT
      LAYER M5 ;
        RECT  31.152 36.528 31.176 36.72 ;
    END
  END dq[219]
  PIN dq[21]
    DIRECTION OUTPUT ;
    USE SIGNAL ;
    PORT
      LAYER M5 ;
        RECT  6.96 36.528 6.984 36.72 ;
    END
  END dq[21]
  PIN dq[220]
    DIRECTION OUTPUT ;
    USE SIGNAL ;
    PORT
      LAYER M3 ;
        RECT  31.284 36.576 31.302 36.72 ;
    END
  END dq[220]
  PIN dq[221]
    DIRECTION OUTPUT ;
    USE SIGNAL ;
    PORT
      LAYER M5 ;
        RECT  31.392 36.528 31.416 36.72 ;
    END
  END dq[221]
  PIN dq[222]
    DIRECTION OUTPUT ;
    USE SIGNAL ;
    PORT
      LAYER M3 ;
        RECT  31.536 36.576 31.554 36.72 ;
    END
  END dq[222]
  PIN dq[223]
    DIRECTION OUTPUT ;
    USE SIGNAL ;
    PORT
      LAYER M5 ;
        RECT  31.632 36.528 31.656 36.72 ;
    END
  END dq[223]
  PIN dq[224]
    DIRECTION OUTPUT ;
    USE SIGNAL ;
    PORT
      LAYER M3 ;
        RECT  31.788 36.576 31.806 36.72 ;
    END
  END dq[224]
  PIN dq[225]
    DIRECTION OUTPUT ;
    USE SIGNAL ;
    PORT
      LAYER M5 ;
        RECT  31.92 36.528 31.944 36.72 ;
    END
  END dq[225]
  PIN dq[226]
    DIRECTION OUTPUT ;
    USE SIGNAL ;
    PORT
      LAYER M3 ;
        RECT  32.004 36.576 32.022 36.72 ;
    END
  END dq[226]
  PIN dq[227]
    DIRECTION OUTPUT ;
    USE SIGNAL ;
    PORT
      LAYER M5 ;
        RECT  32.16 36.528 32.184 36.72 ;
    END
  END dq[227]
  PIN dq[228]
    DIRECTION OUTPUT ;
    USE SIGNAL ;
    PORT
      LAYER M3 ;
        RECT  32.256 36.576 32.274 36.72 ;
    END
  END dq[228]
  PIN dq[229]
    DIRECTION OUTPUT ;
    USE SIGNAL ;
    PORT
      LAYER M5 ;
        RECT  32.4 36.528 32.424 36.72 ;
    END
  END dq[229]
  PIN dq[22]
    DIRECTION OUTPUT ;
    USE SIGNAL ;
    PORT
      LAYER M3 ;
        RECT  7.056 36.576 7.074 36.72 ;
    END
  END dq[22]
  PIN dq[230]
    DIRECTION OUTPUT ;
    USE SIGNAL ;
    PORT
      LAYER M3 ;
        RECT  32.508 36.576 32.526 36.72 ;
    END
  END dq[230]
  PIN dq[231]
    DIRECTION OUTPUT ;
    USE SIGNAL ;
    PORT
      LAYER M5 ;
        RECT  32.64 36.528 32.664 36.72 ;
    END
  END dq[231]
  PIN dq[232]
    DIRECTION OUTPUT ;
    USE SIGNAL ;
    PORT
      LAYER M3 ;
        RECT  32.76 36.576 32.778 36.72 ;
    END
  END dq[232]
  PIN dq[233]
    DIRECTION OUTPUT ;
    USE SIGNAL ;
    PORT
      LAYER M5 ;
        RECT  32.88 36.528 32.904 36.72 ;
    END
  END dq[233]
  PIN dq[234]
    DIRECTION OUTPUT ;
    USE SIGNAL ;
    PORT
      LAYER M3 ;
        RECT  33.012 36.576 33.03 36.72 ;
    END
  END dq[234]
  PIN dq[235]
    DIRECTION OUTPUT ;
    USE SIGNAL ;
    PORT
      LAYER M5 ;
        RECT  33.12 36.528 33.144 36.72 ;
    END
  END dq[235]
  PIN dq[236]
    DIRECTION OUTPUT ;
    USE SIGNAL ;
    PORT
      LAYER M3 ;
        RECT  33.228 36.576 33.246 36.72 ;
    END
  END dq[236]
  PIN dq[237]
    DIRECTION OUTPUT ;
    USE SIGNAL ;
    PORT
      LAYER M5 ;
        RECT  33.36 36.528 33.384 36.72 ;
    END
  END dq[237]
  PIN dq[238]
    DIRECTION OUTPUT ;
    USE SIGNAL ;
    PORT
      LAYER M3 ;
        RECT  33.48 36.576 33.498 36.72 ;
    END
  END dq[238]
  PIN dq[239]
    DIRECTION OUTPUT ;
    USE SIGNAL ;
    PORT
      LAYER M5 ;
        RECT  33.6 36.528 33.624 36.72 ;
    END
  END dq[239]
  PIN dq[23]
    DIRECTION OUTPUT ;
    USE SIGNAL ;
    PORT
      LAYER M5 ;
        RECT  7.2 36.528 7.224 36.72 ;
    END
  END dq[23]
  PIN dq[240]
    DIRECTION OUTPUT ;
    USE SIGNAL ;
    PORT
      LAYER M3 ;
        RECT  33.732 36.576 33.75 36.72 ;
    END
  END dq[240]
  PIN dq[241]
    DIRECTION OUTPUT ;
    USE SIGNAL ;
    PORT
      LAYER M5 ;
        RECT  33.84 36.528 33.864 36.72 ;
    END
  END dq[241]
  PIN dq[242]
    DIRECTION OUTPUT ;
    USE SIGNAL ;
    PORT
      LAYER M3 ;
        RECT  33.984 36.576 34.002 36.72 ;
    END
  END dq[242]
  PIN dq[243]
    DIRECTION OUTPUT ;
    USE SIGNAL ;
    PORT
      LAYER M5 ;
        RECT  34.08 36.528 34.104 36.72 ;
    END
  END dq[243]
  PIN dq[244]
    DIRECTION OUTPUT ;
    USE SIGNAL ;
    PORT
      LAYER M3 ;
        RECT  34.236 36.576 34.254 36.72 ;
    END
  END dq[244]
  PIN dq[245]
    DIRECTION OUTPUT ;
    USE SIGNAL ;
    PORT
      LAYER M5 ;
        RECT  34.32 36.528 34.344 36.72 ;
    END
  END dq[245]
  PIN dq[246]
    DIRECTION OUTPUT ;
    USE SIGNAL ;
    PORT
      LAYER M3 ;
        RECT  34.452 36.576 34.47 36.72 ;
    END
  END dq[246]
  PIN dq[247]
    DIRECTION OUTPUT ;
    USE SIGNAL ;
    PORT
      LAYER M5 ;
        RECT  34.608 36.528 34.632 36.72 ;
    END
  END dq[247]
  PIN dq[248]
    DIRECTION OUTPUT ;
    USE SIGNAL ;
    PORT
      LAYER M3 ;
        RECT  34.704 36.576 34.722 36.72 ;
    END
  END dq[248]
  PIN dq[249]
    DIRECTION OUTPUT ;
    USE SIGNAL ;
    PORT
      LAYER M5 ;
        RECT  34.848 36.528 34.872 36.72 ;
    END
  END dq[249]
  PIN dq[24]
    DIRECTION OUTPUT ;
    USE SIGNAL ;
    PORT
      LAYER M3 ;
        RECT  7.308 36.576 7.326 36.72 ;
    END
  END dq[24]
  PIN dq[250]
    DIRECTION OUTPUT ;
    USE SIGNAL ;
    PORT
      LAYER M3 ;
        RECT  34.956 36.576 34.974 36.72 ;
    END
  END dq[250]
  PIN dq[251]
    DIRECTION OUTPUT ;
    USE SIGNAL ;
    PORT
      LAYER M5 ;
        RECT  35.088 36.528 35.112 36.72 ;
    END
  END dq[251]
  PIN dq[252]
    DIRECTION OUTPUT ;
    USE SIGNAL ;
    PORT
      LAYER M3 ;
        RECT  35.208 36.576 35.226 36.72 ;
    END
  END dq[252]
  PIN dq[253]
    DIRECTION OUTPUT ;
    USE SIGNAL ;
    PORT
      LAYER M5 ;
        RECT  35.328 36.528 35.352 36.72 ;
    END
  END dq[253]
  PIN dq[254]
    DIRECTION OUTPUT ;
    USE SIGNAL ;
    PORT
      LAYER M3 ;
        RECT  35.46 36.576 35.478 36.72 ;
    END
  END dq[254]
  PIN dq[255]
    DIRECTION OUTPUT ;
    USE SIGNAL ;
    PORT
      LAYER M5 ;
        RECT  35.568 36.528 35.592 36.72 ;
    END
  END dq[255]
  PIN dq[256]
    DIRECTION OUTPUT ;
    USE SIGNAL ;
    PORT
      LAYER M3 ;
        RECT  35.676 36.576 35.694 36.72 ;
    END
  END dq[256]
  PIN dq[257]
    DIRECTION OUTPUT ;
    USE SIGNAL ;
    PORT
      LAYER M5 ;
        RECT  35.808 36.528 35.832 36.72 ;
    END
  END dq[257]
  PIN dq[258]
    DIRECTION OUTPUT ;
    USE SIGNAL ;
    PORT
      LAYER M3 ;
        RECT  35.928 36.576 35.946 36.72 ;
    END
  END dq[258]
  PIN dq[259]
    DIRECTION OUTPUT ;
    USE SIGNAL ;
    PORT
      LAYER M5 ;
        RECT  36.048 36.528 36.072 36.72 ;
    END
  END dq[259]
  PIN dq[25]
    DIRECTION OUTPUT ;
    USE SIGNAL ;
    PORT
      LAYER M5 ;
        RECT  7.44 36.528 7.464 36.72 ;
    END
  END dq[25]
  PIN dq[260]
    DIRECTION OUTPUT ;
    USE SIGNAL ;
    PORT
      LAYER M3 ;
        RECT  36.18 36.576 36.198 36.72 ;
    END
  END dq[260]
  PIN dq[261]
    DIRECTION OUTPUT ;
    USE SIGNAL ;
    PORT
      LAYER M5 ;
        RECT  36.288 36.528 36.312 36.72 ;
    END
  END dq[261]
  PIN dq[262]
    DIRECTION OUTPUT ;
    USE SIGNAL ;
    PORT
      LAYER M3 ;
        RECT  36.432 36.576 36.45 36.72 ;
    END
  END dq[262]
  PIN dq[263]
    DIRECTION OUTPUT ;
    USE SIGNAL ;
    PORT
      LAYER M5 ;
        RECT  36.528 36.528 36.552 36.72 ;
    END
  END dq[263]
  PIN dq[264]
    DIRECTION OUTPUT ;
    USE SIGNAL ;
    PORT
      LAYER M3 ;
        RECT  36.684 36.576 36.702 36.72 ;
    END
  END dq[264]
  PIN dq[265]
    DIRECTION OUTPUT ;
    USE SIGNAL ;
    PORT
      LAYER M5 ;
        RECT  36.768 36.528 36.792 36.72 ;
    END
  END dq[265]
  PIN dq[266]
    DIRECTION OUTPUT ;
    USE SIGNAL ;
    PORT
      LAYER M3 ;
        RECT  36.9 36.576 36.918 36.72 ;
    END
  END dq[266]
  PIN dq[267]
    DIRECTION OUTPUT ;
    USE SIGNAL ;
    PORT
      LAYER M5 ;
        RECT  37.056 36.528 37.08 36.72 ;
    END
  END dq[267]
  PIN dq[268]
    DIRECTION OUTPUT ;
    USE SIGNAL ;
    PORT
      LAYER M3 ;
        RECT  37.152 36.576 37.17 36.72 ;
    END
  END dq[268]
  PIN dq[269]
    DIRECTION OUTPUT ;
    USE SIGNAL ;
    PORT
      LAYER M5 ;
        RECT  37.296 36.528 37.32 36.72 ;
    END
  END dq[269]
  PIN dq[26]
    DIRECTION OUTPUT ;
    USE SIGNAL ;
    PORT
      LAYER M3 ;
        RECT  7.56 36.576 7.578 36.72 ;
    END
  END dq[26]
  PIN dq[270]
    DIRECTION OUTPUT ;
    USE SIGNAL ;
    PORT
      LAYER M3 ;
        RECT  37.404 36.576 37.422 36.72 ;
    END
  END dq[270]
  PIN dq[271]
    DIRECTION OUTPUT ;
    USE SIGNAL ;
    PORT
      LAYER M5 ;
        RECT  37.536 36.528 37.56 36.72 ;
    END
  END dq[271]
  PIN dq[272]
    DIRECTION OUTPUT ;
    USE SIGNAL ;
    PORT
      LAYER M3 ;
        RECT  37.656 36.576 37.674 36.72 ;
    END
  END dq[272]
  PIN dq[273]
    DIRECTION OUTPUT ;
    USE SIGNAL ;
    PORT
      LAYER M5 ;
        RECT  37.776 36.528 37.8 36.72 ;
    END
  END dq[273]
  PIN dq[274]
    DIRECTION OUTPUT ;
    USE SIGNAL ;
    PORT
      LAYER M3 ;
        RECT  37.908 36.576 37.926 36.72 ;
    END
  END dq[274]
  PIN dq[275]
    DIRECTION OUTPUT ;
    USE SIGNAL ;
    PORT
      LAYER M5 ;
        RECT  38.016 36.528 38.04 36.72 ;
    END
  END dq[275]
  PIN dq[276]
    DIRECTION OUTPUT ;
    USE SIGNAL ;
    PORT
      LAYER M3 ;
        RECT  38.124 36.576 38.142 36.72 ;
    END
  END dq[276]
  PIN dq[277]
    DIRECTION OUTPUT ;
    USE SIGNAL ;
    PORT
      LAYER M5 ;
        RECT  38.256 36.528 38.28 36.72 ;
    END
  END dq[277]
  PIN dq[278]
    DIRECTION OUTPUT ;
    USE SIGNAL ;
    PORT
      LAYER M3 ;
        RECT  38.376 36.576 38.394 36.72 ;
    END
  END dq[278]
  PIN dq[279]
    DIRECTION OUTPUT ;
    USE SIGNAL ;
    PORT
      LAYER M5 ;
        RECT  38.496 36.528 38.52 36.72 ;
    END
  END dq[279]
  PIN dq[27]
    DIRECTION OUTPUT ;
    USE SIGNAL ;
    PORT
      LAYER M5 ;
        RECT  7.68 36.528 7.704 36.72 ;
    END
  END dq[27]
  PIN dq[280]
    DIRECTION OUTPUT ;
    USE SIGNAL ;
    PORT
      LAYER M3 ;
        RECT  38.628 36.576 38.646 36.72 ;
    END
  END dq[280]
  PIN dq[281]
    DIRECTION OUTPUT ;
    USE SIGNAL ;
    PORT
      LAYER M5 ;
        RECT  38.736 36.528 38.76 36.72 ;
    END
  END dq[281]
  PIN dq[282]
    DIRECTION OUTPUT ;
    USE SIGNAL ;
    PORT
      LAYER M3 ;
        RECT  38.88 36.576 38.898 36.72 ;
    END
  END dq[282]
  PIN dq[283]
    DIRECTION OUTPUT ;
    USE SIGNAL ;
    PORT
      LAYER M5 ;
        RECT  38.976 36.528 39 36.72 ;
    END
  END dq[283]
  PIN dq[284]
    DIRECTION OUTPUT ;
    USE SIGNAL ;
    PORT
      LAYER M3 ;
        RECT  39.132 36.576 39.15 36.72 ;
    END
  END dq[284]
  PIN dq[285]
    DIRECTION OUTPUT ;
    USE SIGNAL ;
    PORT
      LAYER M5 ;
        RECT  39.216 36.528 39.24 36.72 ;
    END
  END dq[285]
  PIN dq[286]
    DIRECTION OUTPUT ;
    USE SIGNAL ;
    PORT
      LAYER M3 ;
        RECT  39.348 36.576 39.366 36.72 ;
    END
  END dq[286]
  PIN dq[287]
    DIRECTION OUTPUT ;
    USE SIGNAL ;
    PORT
      LAYER M5 ;
        RECT  39.504 36.528 39.528 36.72 ;
    END
  END dq[287]
  PIN dq[288]
    DIRECTION OUTPUT ;
    USE SIGNAL ;
    PORT
      LAYER M3 ;
        RECT  39.6 36.576 39.618 36.72 ;
    END
  END dq[288]
  PIN dq[289]
    DIRECTION OUTPUT ;
    USE SIGNAL ;
    PORT
      LAYER M5 ;
        RECT  39.744 36.528 39.768 36.72 ;
    END
  END dq[289]
  PIN dq[28]
    DIRECTION OUTPUT ;
    USE SIGNAL ;
    PORT
      LAYER M3 ;
        RECT  7.812 36.576 7.83 36.72 ;
    END
  END dq[28]
  PIN dq[290]
    DIRECTION OUTPUT ;
    USE SIGNAL ;
    PORT
      LAYER M3 ;
        RECT  39.852 36.576 39.87 36.72 ;
    END
  END dq[290]
  PIN dq[291]
    DIRECTION OUTPUT ;
    USE SIGNAL ;
    PORT
      LAYER M5 ;
        RECT  39.984 36.528 40.008 36.72 ;
    END
  END dq[291]
  PIN dq[292]
    DIRECTION OUTPUT ;
    USE SIGNAL ;
    PORT
      LAYER M3 ;
        RECT  40.104 36.576 40.122 36.72 ;
    END
  END dq[292]
  PIN dq[293]
    DIRECTION OUTPUT ;
    USE SIGNAL ;
    PORT
      LAYER M5 ;
        RECT  40.224 36.528 40.248 36.72 ;
    END
  END dq[293]
  PIN dq[294]
    DIRECTION OUTPUT ;
    USE SIGNAL ;
    PORT
      LAYER M3 ;
        RECT  40.356 36.576 40.374 36.72 ;
    END
  END dq[294]
  PIN dq[295]
    DIRECTION OUTPUT ;
    USE SIGNAL ;
    PORT
      LAYER M5 ;
        RECT  40.464 36.528 40.488 36.72 ;
    END
  END dq[295]
  PIN dq[296]
    DIRECTION OUTPUT ;
    USE SIGNAL ;
    PORT
      LAYER M3 ;
        RECT  40.572 36.576 40.59 36.72 ;
    END
  END dq[296]
  PIN dq[297]
    DIRECTION OUTPUT ;
    USE SIGNAL ;
    PORT
      LAYER M5 ;
        RECT  40.704 36.528 40.728 36.72 ;
    END
  END dq[297]
  PIN dq[298]
    DIRECTION OUTPUT ;
    USE SIGNAL ;
    PORT
      LAYER M3 ;
        RECT  40.824 36.576 40.842 36.72 ;
    END
  END dq[298]
  PIN dq[299]
    DIRECTION OUTPUT ;
    USE SIGNAL ;
    PORT
      LAYER M5 ;
        RECT  40.944 36.528 40.968 36.72 ;
    END
  END dq[299]
  PIN dq[29]
    DIRECTION OUTPUT ;
    USE SIGNAL ;
    PORT
      LAYER M5 ;
        RECT  7.92 36.528 7.944 36.72 ;
    END
  END dq[29]
  PIN dq[2]
    DIRECTION OUTPUT ;
    USE SIGNAL ;
    PORT
      LAYER M3 ;
        RECT  4.608 36.576 4.626 36.72 ;
    END
  END dq[2]
  PIN dq[300]
    DIRECTION OUTPUT ;
    USE SIGNAL ;
    PORT
      LAYER M3 ;
        RECT  41.076 36.576 41.094 36.72 ;
    END
  END dq[300]
  PIN dq[301]
    DIRECTION OUTPUT ;
    USE SIGNAL ;
    PORT
      LAYER M5 ;
        RECT  41.184 36.528 41.208 36.72 ;
    END
  END dq[301]
  PIN dq[302]
    DIRECTION OUTPUT ;
    USE SIGNAL ;
    PORT
      LAYER M3 ;
        RECT  41.328 36.576 41.346 36.72 ;
    END
  END dq[302]
  PIN dq[303]
    DIRECTION OUTPUT ;
    USE SIGNAL ;
    PORT
      LAYER M5 ;
        RECT  41.424 36.528 41.448 36.72 ;
    END
  END dq[303]
  PIN dq[304]
    DIRECTION OUTPUT ;
    USE SIGNAL ;
    PORT
      LAYER M3 ;
        RECT  41.58 36.576 41.598 36.72 ;
    END
  END dq[304]
  PIN dq[305]
    DIRECTION OUTPUT ;
    USE SIGNAL ;
    PORT
      LAYER M5 ;
        RECT  41.664 36.528 41.688 36.72 ;
    END
  END dq[305]
  PIN dq[306]
    DIRECTION OUTPUT ;
    USE SIGNAL ;
    PORT
      LAYER M3 ;
        RECT  41.796 36.576 41.814 36.72 ;
    END
  END dq[306]
  PIN dq[307]
    DIRECTION OUTPUT ;
    USE SIGNAL ;
    PORT
      LAYER M5 ;
        RECT  41.952 36.528 41.976 36.72 ;
    END
  END dq[307]
  PIN dq[308]
    DIRECTION OUTPUT ;
    USE SIGNAL ;
    PORT
      LAYER M3 ;
        RECT  42.048 36.576 42.066 36.72 ;
    END
  END dq[308]
  PIN dq[309]
    DIRECTION OUTPUT ;
    USE SIGNAL ;
    PORT
      LAYER M5 ;
        RECT  42.192 36.528 42.216 36.72 ;
    END
  END dq[309]
  PIN dq[30]
    DIRECTION OUTPUT ;
    USE SIGNAL ;
    PORT
      LAYER M3 ;
        RECT  8.028 36.576 8.046 36.72 ;
    END
  END dq[30]
  PIN dq[310]
    DIRECTION OUTPUT ;
    USE SIGNAL ;
    PORT
      LAYER M3 ;
        RECT  42.3 36.576 42.318 36.72 ;
    END
  END dq[310]
  PIN dq[311]
    DIRECTION OUTPUT ;
    USE SIGNAL ;
    PORT
      LAYER M5 ;
        RECT  42.432 36.528 42.456 36.72 ;
    END
  END dq[311]
  PIN dq[312]
    DIRECTION OUTPUT ;
    USE SIGNAL ;
    PORT
      LAYER M3 ;
        RECT  42.552 36.576 42.57 36.72 ;
    END
  END dq[312]
  PIN dq[313]
    DIRECTION OUTPUT ;
    USE SIGNAL ;
    PORT
      LAYER M5 ;
        RECT  42.672 36.528 42.696 36.72 ;
    END
  END dq[313]
  PIN dq[314]
    DIRECTION OUTPUT ;
    USE SIGNAL ;
    PORT
      LAYER M3 ;
        RECT  42.804 36.576 42.822 36.72 ;
    END
  END dq[314]
  PIN dq[315]
    DIRECTION OUTPUT ;
    USE SIGNAL ;
    PORT
      LAYER M5 ;
        RECT  42.912 36.528 42.936 36.72 ;
    END
  END dq[315]
  PIN dq[316]
    DIRECTION OUTPUT ;
    USE SIGNAL ;
    PORT
      LAYER M3 ;
        RECT  43.02 36.576 43.038 36.72 ;
    END
  END dq[316]
  PIN dq[317]
    DIRECTION OUTPUT ;
    USE SIGNAL ;
    PORT
      LAYER M5 ;
        RECT  43.152 36.528 43.176 36.72 ;
    END
  END dq[317]
  PIN dq[318]
    DIRECTION OUTPUT ;
    USE SIGNAL ;
    PORT
      LAYER M3 ;
        RECT  43.272 36.576 43.29 36.72 ;
    END
  END dq[318]
  PIN dq[319]
    DIRECTION OUTPUT ;
    USE SIGNAL ;
    PORT
      LAYER M5 ;
        RECT  43.392 36.528 43.416 36.72 ;
    END
  END dq[319]
  PIN dq[31]
    DIRECTION OUTPUT ;
    USE SIGNAL ;
    PORT
      LAYER M5 ;
        RECT  8.16 36.528 8.184 36.72 ;
    END
  END dq[31]
  PIN dq[320]
    DIRECTION OUTPUT ;
    USE SIGNAL ;
    PORT
      LAYER M3 ;
        RECT  43.524 36.576 43.542 36.72 ;
    END
  END dq[320]
  PIN dq[321]
    DIRECTION OUTPUT ;
    USE SIGNAL ;
    PORT
      LAYER M5 ;
        RECT  43.632 36.528 43.656 36.72 ;
    END
  END dq[321]
  PIN dq[322]
    DIRECTION OUTPUT ;
    USE SIGNAL ;
    PORT
      LAYER M3 ;
        RECT  43.776 36.576 43.794 36.72 ;
    END
  END dq[322]
  PIN dq[323]
    DIRECTION OUTPUT ;
    USE SIGNAL ;
    PORT
      LAYER M5 ;
        RECT  43.872 36.528 43.896 36.72 ;
    END
  END dq[323]
  PIN dq[324]
    DIRECTION OUTPUT ;
    USE SIGNAL ;
    PORT
      LAYER M3 ;
        RECT  44.028 36.576 44.046 36.72 ;
    END
  END dq[324]
  PIN dq[325]
    DIRECTION OUTPUT ;
    USE SIGNAL ;
    PORT
      LAYER M5 ;
        RECT  44.112 36.528 44.136 36.72 ;
    END
  END dq[325]
  PIN dq[326]
    DIRECTION OUTPUT ;
    USE SIGNAL ;
    PORT
      LAYER M3 ;
        RECT  44.244 36.576 44.262 36.72 ;
    END
  END dq[326]
  PIN dq[327]
    DIRECTION OUTPUT ;
    USE SIGNAL ;
    PORT
      LAYER M5 ;
        RECT  44.352 36.528 44.376 36.72 ;
    END
  END dq[327]
  PIN dq[328]
    DIRECTION OUTPUT ;
    USE SIGNAL ;
    PORT
      LAYER M3 ;
        RECT  44.496 36.576 44.514 36.72 ;
    END
  END dq[328]
  PIN dq[329]
    DIRECTION OUTPUT ;
    USE SIGNAL ;
    PORT
      LAYER M5 ;
        RECT  44.64 36.528 44.664 36.72 ;
    END
  END dq[329]
  PIN dq[32]
    DIRECTION OUTPUT ;
    USE SIGNAL ;
    PORT
      LAYER M3 ;
        RECT  8.28 36.576 8.298 36.72 ;
    END
  END dq[32]
  PIN dq[330]
    DIRECTION OUTPUT ;
    USE SIGNAL ;
    PORT
      LAYER M3 ;
        RECT  44.748 36.576 44.766 36.72 ;
    END
  END dq[330]
  PIN dq[331]
    DIRECTION OUTPUT ;
    USE SIGNAL ;
    PORT
      LAYER M5 ;
        RECT  44.88 36.528 44.904 36.72 ;
    END
  END dq[331]
  PIN dq[332]
    DIRECTION OUTPUT ;
    USE SIGNAL ;
    PORT
      LAYER M3 ;
        RECT  45 36.576 45.018 36.72 ;
    END
  END dq[332]
  PIN dq[333]
    DIRECTION OUTPUT ;
    USE SIGNAL ;
    PORT
      LAYER M5 ;
        RECT  45.12 36.528 45.144 36.72 ;
    END
  END dq[333]
  PIN dq[334]
    DIRECTION OUTPUT ;
    USE SIGNAL ;
    PORT
      LAYER M3 ;
        RECT  45.252 36.576 45.27 36.72 ;
    END
  END dq[334]
  PIN dq[335]
    DIRECTION OUTPUT ;
    USE SIGNAL ;
    PORT
      LAYER M5 ;
        RECT  45.36 36.528 45.384 36.72 ;
    END
  END dq[335]
  PIN dq[336]
    DIRECTION OUTPUT ;
    USE SIGNAL ;
    PORT
      LAYER M3 ;
        RECT  45.468 36.576 45.486 36.72 ;
    END
  END dq[336]
  PIN dq[337]
    DIRECTION OUTPUT ;
    USE SIGNAL ;
    PORT
      LAYER M5 ;
        RECT  45.6 36.528 45.624 36.72 ;
    END
  END dq[337]
  PIN dq[338]
    DIRECTION OUTPUT ;
    USE SIGNAL ;
    PORT
      LAYER M3 ;
        RECT  45.72 36.576 45.738 36.72 ;
    END
  END dq[338]
  PIN dq[339]
    DIRECTION OUTPUT ;
    USE SIGNAL ;
    PORT
      LAYER M5 ;
        RECT  45.84 36.528 45.864 36.72 ;
    END
  END dq[339]
  PIN dq[33]
    DIRECTION OUTPUT ;
    USE SIGNAL ;
    PORT
      LAYER M5 ;
        RECT  8.4 36.528 8.424 36.72 ;
    END
  END dq[33]
  PIN dq[340]
    DIRECTION OUTPUT ;
    USE SIGNAL ;
    PORT
      LAYER M3 ;
        RECT  45.972 36.576 45.99 36.72 ;
    END
  END dq[340]
  PIN dq[341]
    DIRECTION OUTPUT ;
    USE SIGNAL ;
    PORT
      LAYER M5 ;
        RECT  46.08 36.528 46.104 36.72 ;
    END
  END dq[341]
  PIN dq[342]
    DIRECTION OUTPUT ;
    USE SIGNAL ;
    PORT
      LAYER M3 ;
        RECT  46.224 36.576 46.242 36.72 ;
    END
  END dq[342]
  PIN dq[343]
    DIRECTION OUTPUT ;
    USE SIGNAL ;
    PORT
      LAYER M5 ;
        RECT  46.32 36.528 46.344 36.72 ;
    END
  END dq[343]
  PIN dq[344]
    DIRECTION OUTPUT ;
    USE SIGNAL ;
    PORT
      LAYER M3 ;
        RECT  46.476 36.576 46.494 36.72 ;
    END
  END dq[344]
  PIN dq[345]
    DIRECTION OUTPUT ;
    USE SIGNAL ;
    PORT
      LAYER M5 ;
        RECT  46.56 36.528 46.584 36.72 ;
    END
  END dq[345]
  PIN dq[346]
    DIRECTION OUTPUT ;
    USE SIGNAL ;
    PORT
      LAYER M3 ;
        RECT  46.692 36.576 46.71 36.72 ;
    END
  END dq[346]
  PIN dq[347]
    DIRECTION OUTPUT ;
    USE SIGNAL ;
    PORT
      LAYER M5 ;
        RECT  46.8 36.528 46.824 36.72 ;
    END
  END dq[347]
  PIN dq[348]
    DIRECTION OUTPUT ;
    USE SIGNAL ;
    PORT
      LAYER M3 ;
        RECT  46.944 36.576 46.962 36.72 ;
    END
  END dq[348]
  PIN dq[349]
    DIRECTION OUTPUT ;
    USE SIGNAL ;
    PORT
      LAYER M5 ;
        RECT  47.088 36.528 47.112 36.72 ;
    END
  END dq[349]
  PIN dq[34]
    DIRECTION OUTPUT ;
    USE SIGNAL ;
    PORT
      LAYER M3 ;
        RECT  8.532 36.576 8.55 36.72 ;
    END
  END dq[34]
  PIN dq[350]
    DIRECTION OUTPUT ;
    USE SIGNAL ;
    PORT
      LAYER M3 ;
        RECT  47.196 36.576 47.214 36.72 ;
    END
  END dq[350]
  PIN dq[351]
    DIRECTION OUTPUT ;
    USE SIGNAL ;
    PORT
      LAYER M5 ;
        RECT  47.328 36.528 47.352 36.72 ;
    END
  END dq[351]
  PIN dq[352]
    DIRECTION OUTPUT ;
    USE SIGNAL ;
    PORT
      LAYER M3 ;
        RECT  47.448 36.576 47.466 36.72 ;
    END
  END dq[352]
  PIN dq[353]
    DIRECTION OUTPUT ;
    USE SIGNAL ;
    PORT
      LAYER M5 ;
        RECT  47.568 36.528 47.592 36.72 ;
    END
  END dq[353]
  PIN dq[354]
    DIRECTION OUTPUT ;
    USE SIGNAL ;
    PORT
      LAYER M3 ;
        RECT  47.664 36.576 47.682 36.72 ;
    END
  END dq[354]
  PIN dq[355]
    DIRECTION OUTPUT ;
    USE SIGNAL ;
    PORT
      LAYER M5 ;
        RECT  47.808 36.528 47.832 36.72 ;
    END
  END dq[355]
  PIN dq[356]
    DIRECTION OUTPUT ;
    USE SIGNAL ;
    PORT
      LAYER M3 ;
        RECT  47.916 36.576 47.934 36.72 ;
    END
  END dq[356]
  PIN dq[357]
    DIRECTION OUTPUT ;
    USE SIGNAL ;
    PORT
      LAYER M5 ;
        RECT  48.048 36.528 48.072 36.72 ;
    END
  END dq[357]
  PIN dq[358]
    DIRECTION OUTPUT ;
    USE SIGNAL ;
    PORT
      LAYER M3 ;
        RECT  48.168 36.576 48.186 36.72 ;
    END
  END dq[358]
  PIN dq[359]
    DIRECTION OUTPUT ;
    USE SIGNAL ;
    PORT
      LAYER M5 ;
        RECT  48.288 36.528 48.312 36.72 ;
    END
  END dq[359]
  PIN dq[35]
    DIRECTION OUTPUT ;
    USE SIGNAL ;
    PORT
      LAYER M5 ;
        RECT  8.64 36.528 8.664 36.72 ;
    END
  END dq[35]
  PIN dq[360]
    DIRECTION OUTPUT ;
    USE SIGNAL ;
    PORT
      LAYER M3 ;
        RECT  48.42 36.576 48.438 36.72 ;
    END
  END dq[360]
  PIN dq[361]
    DIRECTION OUTPUT ;
    USE SIGNAL ;
    PORT
      LAYER M5 ;
        RECT  48.528 36.528 48.552 36.72 ;
    END
  END dq[361]
  PIN dq[362]
    DIRECTION OUTPUT ;
    USE SIGNAL ;
    PORT
      LAYER M3 ;
        RECT  48.672 36.576 48.69 36.72 ;
    END
  END dq[362]
  PIN dq[363]
    DIRECTION OUTPUT ;
    USE SIGNAL ;
    PORT
      LAYER M5 ;
        RECT  48.768 36.528 48.792 36.72 ;
    END
  END dq[363]
  PIN dq[364]
    DIRECTION OUTPUT ;
    USE SIGNAL ;
    PORT
      LAYER M3 ;
        RECT  48.888 36.576 48.906 36.72 ;
    END
  END dq[364]
  PIN dq[365]
    DIRECTION OUTPUT ;
    USE SIGNAL ;
    PORT
      LAYER M5 ;
        RECT  49.008 36.528 49.032 36.72 ;
    END
  END dq[365]
  PIN dq[366]
    DIRECTION OUTPUT ;
    USE SIGNAL ;
    PORT
      LAYER M3 ;
        RECT  49.14 36.576 49.158 36.72 ;
    END
  END dq[366]
  PIN dq[367]
    DIRECTION OUTPUT ;
    USE SIGNAL ;
    PORT
      LAYER M5 ;
        RECT  49.248 36.528 49.272 36.72 ;
    END
  END dq[367]
  PIN dq[368]
    DIRECTION OUTPUT ;
    USE SIGNAL ;
    PORT
      LAYER M3 ;
        RECT  49.392 36.576 49.41 36.72 ;
    END
  END dq[368]
  PIN dq[369]
    DIRECTION OUTPUT ;
    USE SIGNAL ;
    PORT
      LAYER M5 ;
        RECT  49.536 36.528 49.56 36.72 ;
    END
  END dq[369]
  PIN dq[36]
    DIRECTION OUTPUT ;
    USE SIGNAL ;
    PORT
      LAYER M3 ;
        RECT  8.784 36.576 8.802 36.72 ;
    END
  END dq[36]
  PIN dq[370]
    DIRECTION OUTPUT ;
    USE SIGNAL ;
    PORT
      LAYER M3 ;
        RECT  49.644 36.576 49.662 36.72 ;
    END
  END dq[370]
  PIN dq[371]
    DIRECTION OUTPUT ;
    USE SIGNAL ;
    PORT
      LAYER M5 ;
        RECT  49.776 36.528 49.8 36.72 ;
    END
  END dq[371]
  PIN dq[372]
    DIRECTION OUTPUT ;
    USE SIGNAL ;
    PORT
      LAYER M3 ;
        RECT  49.896 36.576 49.914 36.72 ;
    END
  END dq[372]
  PIN dq[373]
    DIRECTION OUTPUT ;
    USE SIGNAL ;
    PORT
      LAYER M5 ;
        RECT  50.016 36.528 50.04 36.72 ;
    END
  END dq[373]
  PIN dq[374]
    DIRECTION OUTPUT ;
    USE SIGNAL ;
    PORT
      LAYER M3 ;
        RECT  50.112 36.576 50.13 36.72 ;
    END
  END dq[374]
  PIN dq[375]
    DIRECTION OUTPUT ;
    USE SIGNAL ;
    PORT
      LAYER M5 ;
        RECT  50.256 36.528 50.28 36.72 ;
    END
  END dq[375]
  PIN dq[376]
    DIRECTION OUTPUT ;
    USE SIGNAL ;
    PORT
      LAYER M3 ;
        RECT  50.364 36.576 50.382 36.72 ;
    END
  END dq[376]
  PIN dq[377]
    DIRECTION OUTPUT ;
    USE SIGNAL ;
    PORT
      LAYER M5 ;
        RECT  50.496 36.528 50.52 36.72 ;
    END
  END dq[377]
  PIN dq[378]
    DIRECTION OUTPUT ;
    USE SIGNAL ;
    PORT
      LAYER M3 ;
        RECT  50.616 36.576 50.634 36.72 ;
    END
  END dq[378]
  PIN dq[379]
    DIRECTION OUTPUT ;
    USE SIGNAL ;
    PORT
      LAYER M5 ;
        RECT  50.736 36.528 50.76 36.72 ;
    END
  END dq[379]
  PIN dq[37]
    DIRECTION OUTPUT ;
    USE SIGNAL ;
    PORT
      LAYER M5 ;
        RECT  8.88 36.528 8.904 36.72 ;
    END
  END dq[37]
  PIN dq[380]
    DIRECTION OUTPUT ;
    USE SIGNAL ;
    PORT
      LAYER M3 ;
        RECT  50.868 36.576 50.886 36.72 ;
    END
  END dq[380]
  PIN dq[381]
    DIRECTION OUTPUT ;
    USE SIGNAL ;
    PORT
      LAYER M5 ;
        RECT  50.976 36.528 51 36.72 ;
    END
  END dq[381]
  PIN dq[382]
    DIRECTION OUTPUT ;
    USE SIGNAL ;
    PORT
      LAYER M3 ;
        RECT  51.12 36.576 51.138 36.72 ;
    END
  END dq[382]
  PIN dq[383]
    DIRECTION OUTPUT ;
    USE SIGNAL ;
    PORT
      LAYER M5 ;
        RECT  51.216 36.528 51.24 36.72 ;
    END
  END dq[383]
  PIN dq[384]
    DIRECTION OUTPUT ;
    USE SIGNAL ;
    PORT
      LAYER M3 ;
        RECT  51.336 36.576 51.354 36.72 ;
    END
  END dq[384]
  PIN dq[385]
    DIRECTION OUTPUT ;
    USE SIGNAL ;
    PORT
      LAYER M5 ;
        RECT  51.456 36.528 51.48 36.72 ;
    END
  END dq[385]
  PIN dq[386]
    DIRECTION OUTPUT ;
    USE SIGNAL ;
    PORT
      LAYER M3 ;
        RECT  51.588 36.576 51.606 36.72 ;
    END
  END dq[386]
  PIN dq[387]
    DIRECTION OUTPUT ;
    USE SIGNAL ;
    PORT
      LAYER M5 ;
        RECT  51.696 36.528 51.72 36.72 ;
    END
  END dq[387]
  PIN dq[388]
    DIRECTION OUTPUT ;
    USE SIGNAL ;
    PORT
      LAYER M3 ;
        RECT  51.84 36.576 51.858 36.72 ;
    END
  END dq[388]
  PIN dq[389]
    DIRECTION OUTPUT ;
    USE SIGNAL ;
    PORT
      LAYER M5 ;
        RECT  51.984 36.528 52.008 36.72 ;
    END
  END dq[389]
  PIN dq[38]
    DIRECTION OUTPUT ;
    USE SIGNAL ;
    PORT
      LAYER M3 ;
        RECT  9.036 36.576 9.054 36.72 ;
    END
  END dq[38]
  PIN dq[390]
    DIRECTION OUTPUT ;
    USE SIGNAL ;
    PORT
      LAYER M3 ;
        RECT  52.092 36.576 52.11 36.72 ;
    END
  END dq[390]
  PIN dq[391]
    DIRECTION OUTPUT ;
    USE SIGNAL ;
    PORT
      LAYER M5 ;
        RECT  52.224 36.528 52.248 36.72 ;
    END
  END dq[391]
  PIN dq[392]
    DIRECTION OUTPUT ;
    USE SIGNAL ;
    PORT
      LAYER M3 ;
        RECT  52.344 36.576 52.362 36.72 ;
    END
  END dq[392]
  PIN dq[393]
    DIRECTION OUTPUT ;
    USE SIGNAL ;
    PORT
      LAYER M5 ;
        RECT  52.464 36.528 52.488 36.72 ;
    END
  END dq[393]
  PIN dq[394]
    DIRECTION OUTPUT ;
    USE SIGNAL ;
    PORT
      LAYER M3 ;
        RECT  52.56 36.576 52.578 36.72 ;
    END
  END dq[394]
  PIN dq[395]
    DIRECTION OUTPUT ;
    USE SIGNAL ;
    PORT
      LAYER M5 ;
        RECT  52.704 36.528 52.728 36.72 ;
    END
  END dq[395]
  PIN dq[396]
    DIRECTION OUTPUT ;
    USE SIGNAL ;
    PORT
      LAYER M3 ;
        RECT  52.812 36.576 52.83 36.72 ;
    END
  END dq[396]
  PIN dq[397]
    DIRECTION OUTPUT ;
    USE SIGNAL ;
    PORT
      LAYER M5 ;
        RECT  52.944 36.528 52.968 36.72 ;
    END
  END dq[397]
  PIN dq[398]
    DIRECTION OUTPUT ;
    USE SIGNAL ;
    PORT
      LAYER M3 ;
        RECT  53.064 36.576 53.082 36.72 ;
    END
  END dq[398]
  PIN dq[399]
    DIRECTION OUTPUT ;
    USE SIGNAL ;
    PORT
      LAYER M5 ;
        RECT  53.184 36.528 53.208 36.72 ;
    END
  END dq[399]
  PIN dq[39]
    DIRECTION OUTPUT ;
    USE SIGNAL ;
    PORT
      LAYER M5 ;
        RECT  9.12 36.528 9.144 36.72 ;
    END
  END dq[39]
  PIN dq[3]
    DIRECTION OUTPUT ;
    USE SIGNAL ;
    PORT
      LAYER M5 ;
        RECT  4.752 36.528 4.776 36.72 ;
    END
  END dq[3]
  PIN dq[400]
    DIRECTION OUTPUT ;
    USE SIGNAL ;
    PORT
      LAYER M3 ;
        RECT  53.316 36.576 53.334 36.72 ;
    END
  END dq[400]
  PIN dq[401]
    DIRECTION OUTPUT ;
    USE SIGNAL ;
    PORT
      LAYER M5 ;
        RECT  53.424 36.528 53.448 36.72 ;
    END
  END dq[401]
  PIN dq[402]
    DIRECTION OUTPUT ;
    USE SIGNAL ;
    PORT
      LAYER M3 ;
        RECT  53.568 36.576 53.586 36.72 ;
    END
  END dq[402]
  PIN dq[403]
    DIRECTION OUTPUT ;
    USE SIGNAL ;
    PORT
      LAYER M5 ;
        RECT  53.664 36.528 53.688 36.72 ;
    END
  END dq[403]
  PIN dq[404]
    DIRECTION OUTPUT ;
    USE SIGNAL ;
    PORT
      LAYER M3 ;
        RECT  53.784 36.576 53.802 36.72 ;
    END
  END dq[404]
  PIN dq[405]
    DIRECTION OUTPUT ;
    USE SIGNAL ;
    PORT
      LAYER M5 ;
        RECT  53.904 36.528 53.928 36.72 ;
    END
  END dq[405]
  PIN dq[406]
    DIRECTION OUTPUT ;
    USE SIGNAL ;
    PORT
      LAYER M3 ;
        RECT  54.036 36.576 54.054 36.72 ;
    END
  END dq[406]
  PIN dq[407]
    DIRECTION OUTPUT ;
    USE SIGNAL ;
    PORT
      LAYER M5 ;
        RECT  54.144 36.528 54.168 36.72 ;
    END
  END dq[407]
  PIN dq[408]
    DIRECTION OUTPUT ;
    USE SIGNAL ;
    PORT
      LAYER M3 ;
        RECT  54.288 36.576 54.306 36.72 ;
    END
  END dq[408]
  PIN dq[409]
    DIRECTION OUTPUT ;
    USE SIGNAL ;
    PORT
      LAYER M5 ;
        RECT  54.384 36.528 54.408 36.72 ;
    END
  END dq[409]
  PIN dq[40]
    DIRECTION OUTPUT ;
    USE SIGNAL ;
    PORT
      LAYER M3 ;
        RECT  9.252 36.576 9.27 36.72 ;
    END
  END dq[40]
  PIN dq[410]
    DIRECTION OUTPUT ;
    USE SIGNAL ;
    PORT
      LAYER M3 ;
        RECT  54.54 36.576 54.558 36.72 ;
    END
  END dq[410]
  PIN dq[411]
    DIRECTION OUTPUT ;
    USE SIGNAL ;
    PORT
      LAYER M5 ;
        RECT  54.672 36.528 54.696 36.72 ;
    END
  END dq[411]
  PIN dq[412]
    DIRECTION OUTPUT ;
    USE SIGNAL ;
    PORT
      LAYER M3 ;
        RECT  54.792 36.576 54.81 36.72 ;
    END
  END dq[412]
  PIN dq[413]
    DIRECTION OUTPUT ;
    USE SIGNAL ;
    PORT
      LAYER M5 ;
        RECT  54.912 36.528 54.936 36.72 ;
    END
  END dq[413]
  PIN dq[414]
    DIRECTION OUTPUT ;
    USE SIGNAL ;
    PORT
      LAYER M3 ;
        RECT  55.008 36.576 55.026 36.72 ;
    END
  END dq[414]
  PIN dq[415]
    DIRECTION OUTPUT ;
    USE SIGNAL ;
    PORT
      LAYER M5 ;
        RECT  55.152 36.528 55.176 36.72 ;
    END
  END dq[415]
  PIN dq[416]
    DIRECTION OUTPUT ;
    USE SIGNAL ;
    PORT
      LAYER M3 ;
        RECT  55.26 36.576 55.278 36.72 ;
    END
  END dq[416]
  PIN dq[417]
    DIRECTION OUTPUT ;
    USE SIGNAL ;
    PORT
      LAYER M5 ;
        RECT  55.392 36.528 55.416 36.72 ;
    END
  END dq[417]
  PIN dq[418]
    DIRECTION OUTPUT ;
    USE SIGNAL ;
    PORT
      LAYER M3 ;
        RECT  55.512 36.576 55.53 36.72 ;
    END
  END dq[418]
  PIN dq[419]
    DIRECTION OUTPUT ;
    USE SIGNAL ;
    PORT
      LAYER M5 ;
        RECT  55.632 36.528 55.656 36.72 ;
    END
  END dq[419]
  PIN dq[41]
    DIRECTION OUTPUT ;
    USE SIGNAL ;
    PORT
      LAYER M5 ;
        RECT  9.408 36.528 9.432 36.72 ;
    END
  END dq[41]
  PIN dq[420]
    DIRECTION OUTPUT ;
    USE SIGNAL ;
    PORT
      LAYER M3 ;
        RECT  55.764 36.576 55.782 36.72 ;
    END
  END dq[420]
  PIN dq[421]
    DIRECTION OUTPUT ;
    USE SIGNAL ;
    PORT
      LAYER M5 ;
        RECT  55.872 36.528 55.896 36.72 ;
    END
  END dq[421]
  PIN dq[422]
    DIRECTION OUTPUT ;
    USE SIGNAL ;
    PORT
      LAYER M3 ;
        RECT  56.016 36.576 56.034 36.72 ;
    END
  END dq[422]
  PIN dq[423]
    DIRECTION OUTPUT ;
    USE SIGNAL ;
    PORT
      LAYER M5 ;
        RECT  56.112 36.528 56.136 36.72 ;
    END
  END dq[423]
  PIN dq[424]
    DIRECTION OUTPUT ;
    USE SIGNAL ;
    PORT
      LAYER M3 ;
        RECT  56.232 36.576 56.25 36.72 ;
    END
  END dq[424]
  PIN dq[425]
    DIRECTION OUTPUT ;
    USE SIGNAL ;
    PORT
      LAYER M5 ;
        RECT  56.352 36.528 56.376 36.72 ;
    END
  END dq[425]
  PIN dq[426]
    DIRECTION OUTPUT ;
    USE SIGNAL ;
    PORT
      LAYER M3 ;
        RECT  56.484 36.576 56.502 36.72 ;
    END
  END dq[426]
  PIN dq[427]
    DIRECTION OUTPUT ;
    USE SIGNAL ;
    PORT
      LAYER M5 ;
        RECT  56.592 36.528 56.616 36.72 ;
    END
  END dq[427]
  PIN dq[428]
    DIRECTION OUTPUT ;
    USE SIGNAL ;
    PORT
      LAYER M3 ;
        RECT  56.736 36.576 56.754 36.72 ;
    END
  END dq[428]
  PIN dq[429]
    DIRECTION OUTPUT ;
    USE SIGNAL ;
    PORT
      LAYER M5 ;
        RECT  56.832 36.528 56.856 36.72 ;
    END
  END dq[429]
  PIN dq[42]
    DIRECTION OUTPUT ;
    USE SIGNAL ;
    PORT
      LAYER M3 ;
        RECT  9.504 36.576 9.522 36.72 ;
    END
  END dq[42]
  PIN dq[430]
    DIRECTION OUTPUT ;
    USE SIGNAL ;
    PORT
      LAYER M3 ;
        RECT  56.988 36.576 57.006 36.72 ;
    END
  END dq[430]
  PIN dq[431]
    DIRECTION OUTPUT ;
    USE SIGNAL ;
    PORT
      LAYER M5 ;
        RECT  57.12 36.528 57.144 36.72 ;
    END
  END dq[431]
  PIN dq[432]
    DIRECTION OUTPUT ;
    USE SIGNAL ;
    PORT
      LAYER M3 ;
        RECT  57.24 36.576 57.258 36.72 ;
    END
  END dq[432]
  PIN dq[433]
    DIRECTION OUTPUT ;
    USE SIGNAL ;
    PORT
      LAYER M5 ;
        RECT  57.36 36.528 57.384 36.72 ;
    END
  END dq[433]
  PIN dq[434]
    DIRECTION OUTPUT ;
    USE SIGNAL ;
    PORT
      LAYER M3 ;
        RECT  57.456 36.576 57.474 36.72 ;
    END
  END dq[434]
  PIN dq[435]
    DIRECTION OUTPUT ;
    USE SIGNAL ;
    PORT
      LAYER M5 ;
        RECT  57.6 36.528 57.624 36.72 ;
    END
  END dq[435]
  PIN dq[436]
    DIRECTION OUTPUT ;
    USE SIGNAL ;
    PORT
      LAYER M3 ;
        RECT  57.708 36.576 57.726 36.72 ;
    END
  END dq[436]
  PIN dq[437]
    DIRECTION OUTPUT ;
    USE SIGNAL ;
    PORT
      LAYER M5 ;
        RECT  57.84 36.528 57.864 36.72 ;
    END
  END dq[437]
  PIN dq[438]
    DIRECTION OUTPUT ;
    USE SIGNAL ;
    PORT
      LAYER M3 ;
        RECT  57.96 36.576 57.978 36.72 ;
    END
  END dq[438]
  PIN dq[439]
    DIRECTION OUTPUT ;
    USE SIGNAL ;
    PORT
      LAYER M5 ;
        RECT  58.08 36.528 58.104 36.72 ;
    END
  END dq[439]
  PIN dq[43]
    DIRECTION OUTPUT ;
    USE SIGNAL ;
    PORT
      LAYER M5 ;
        RECT  9.648 36.528 9.672 36.72 ;
    END
  END dq[43]
  PIN dq[440]
    DIRECTION OUTPUT ;
    USE SIGNAL ;
    PORT
      LAYER M3 ;
        RECT  58.212 36.576 58.23 36.72 ;
    END
  END dq[440]
  PIN dq[441]
    DIRECTION OUTPUT ;
    USE SIGNAL ;
    PORT
      LAYER M5 ;
        RECT  58.32 36.528 58.344 36.72 ;
    END
  END dq[441]
  PIN dq[442]
    DIRECTION OUTPUT ;
    USE SIGNAL ;
    PORT
      LAYER M3 ;
        RECT  58.464 36.576 58.482 36.72 ;
    END
  END dq[442]
  PIN dq[443]
    DIRECTION OUTPUT ;
    USE SIGNAL ;
    PORT
      LAYER M5 ;
        RECT  58.56 36.528 58.584 36.72 ;
    END
  END dq[443]
  PIN dq[444]
    DIRECTION OUTPUT ;
    USE SIGNAL ;
    PORT
      LAYER M3 ;
        RECT  58.68 36.576 58.698 36.72 ;
    END
  END dq[444]
  PIN dq[445]
    DIRECTION OUTPUT ;
    USE SIGNAL ;
    PORT
      LAYER M5 ;
        RECT  58.8 36.528 58.824 36.72 ;
    END
  END dq[445]
  PIN dq[446]
    DIRECTION OUTPUT ;
    USE SIGNAL ;
    PORT
      LAYER M3 ;
        RECT  58.932 36.576 58.95 36.72 ;
    END
  END dq[446]
  PIN dq[447]
    DIRECTION OUTPUT ;
    USE SIGNAL ;
    PORT
      LAYER M5 ;
        RECT  59.04 36.528 59.064 36.72 ;
    END
  END dq[447]
  PIN dq[448]
    DIRECTION OUTPUT ;
    USE SIGNAL ;
    PORT
      LAYER M3 ;
        RECT  59.184 36.576 59.202 36.72 ;
    END
  END dq[448]
  PIN dq[449]
    DIRECTION OUTPUT ;
    USE SIGNAL ;
    PORT
      LAYER M5 ;
        RECT  59.28 36.528 59.304 36.72 ;
    END
  END dq[449]
  PIN dq[44]
    DIRECTION OUTPUT ;
    USE SIGNAL ;
    PORT
      LAYER M3 ;
        RECT  9.756 36.576 9.774 36.72 ;
    END
  END dq[44]
  PIN dq[450]
    DIRECTION OUTPUT ;
    USE SIGNAL ;
    PORT
      LAYER M3 ;
        RECT  59.436 36.576 59.454 36.72 ;
    END
  END dq[450]
  PIN dq[451]
    DIRECTION OUTPUT ;
    USE SIGNAL ;
    PORT
      LAYER M5 ;
        RECT  59.568 36.528 59.592 36.72 ;
    END
  END dq[451]
  PIN dq[452]
    DIRECTION OUTPUT ;
    USE SIGNAL ;
    PORT
      LAYER M3 ;
        RECT  59.688 36.576 59.706 36.72 ;
    END
  END dq[452]
  PIN dq[453]
    DIRECTION OUTPUT ;
    USE SIGNAL ;
    PORT
      LAYER M5 ;
        RECT  59.808 36.528 59.832 36.72 ;
    END
  END dq[453]
  PIN dq[454]
    DIRECTION OUTPUT ;
    USE SIGNAL ;
    PORT
      LAYER M3 ;
        RECT  59.904 36.576 59.922 36.72 ;
    END
  END dq[454]
  PIN dq[455]
    DIRECTION OUTPUT ;
    USE SIGNAL ;
    PORT
      LAYER M5 ;
        RECT  60.048 36.528 60.072 36.72 ;
    END
  END dq[455]
  PIN dq[456]
    DIRECTION OUTPUT ;
    USE SIGNAL ;
    PORT
      LAYER M3 ;
        RECT  60.156 36.576 60.174 36.72 ;
    END
  END dq[456]
  PIN dq[457]
    DIRECTION OUTPUT ;
    USE SIGNAL ;
    PORT
      LAYER M5 ;
        RECT  60.288 36.528 60.312 36.72 ;
    END
  END dq[457]
  PIN dq[458]
    DIRECTION OUTPUT ;
    USE SIGNAL ;
    PORT
      LAYER M3 ;
        RECT  60.408 36.576 60.426 36.72 ;
    END
  END dq[458]
  PIN dq[459]
    DIRECTION OUTPUT ;
    USE SIGNAL ;
    PORT
      LAYER M5 ;
        RECT  60.528 36.528 60.552 36.72 ;
    END
  END dq[459]
  PIN dq[45]
    DIRECTION OUTPUT ;
    USE SIGNAL ;
    PORT
      LAYER M5 ;
        RECT  9.888 36.528 9.912 36.72 ;
    END
  END dq[45]
  PIN dq[460]
    DIRECTION OUTPUT ;
    USE SIGNAL ;
    PORT
      LAYER M3 ;
        RECT  60.66 36.576 60.678 36.72 ;
    END
  END dq[460]
  PIN dq[461]
    DIRECTION OUTPUT ;
    USE SIGNAL ;
    PORT
      LAYER M5 ;
        RECT  60.768 36.528 60.792 36.72 ;
    END
  END dq[461]
  PIN dq[462]
    DIRECTION OUTPUT ;
    USE SIGNAL ;
    PORT
      LAYER M3 ;
        RECT  60.912 36.576 60.93 36.72 ;
    END
  END dq[462]
  PIN dq[463]
    DIRECTION OUTPUT ;
    USE SIGNAL ;
    PORT
      LAYER M5 ;
        RECT  61.008 36.528 61.032 36.72 ;
    END
  END dq[463]
  PIN dq[464]
    DIRECTION OUTPUT ;
    USE SIGNAL ;
    PORT
      LAYER M3 ;
        RECT  61.128 36.576 61.146 36.72 ;
    END
  END dq[464]
  PIN dq[465]
    DIRECTION OUTPUT ;
    USE SIGNAL ;
    PORT
      LAYER M5 ;
        RECT  61.248 36.528 61.272 36.72 ;
    END
  END dq[465]
  PIN dq[466]
    DIRECTION OUTPUT ;
    USE SIGNAL ;
    PORT
      LAYER M3 ;
        RECT  61.38 36.576 61.398 36.72 ;
    END
  END dq[466]
  PIN dq[467]
    DIRECTION OUTPUT ;
    USE SIGNAL ;
    PORT
      LAYER M5 ;
        RECT  61.488 36.528 61.512 36.72 ;
    END
  END dq[467]
  PIN dq[468]
    DIRECTION OUTPUT ;
    USE SIGNAL ;
    PORT
      LAYER M3 ;
        RECT  61.632 36.576 61.65 36.72 ;
    END
  END dq[468]
  PIN dq[469]
    DIRECTION OUTPUT ;
    USE SIGNAL ;
    PORT
      LAYER M5 ;
        RECT  61.728 36.528 61.752 36.72 ;
    END
  END dq[469]
  PIN dq[46]
    DIRECTION OUTPUT ;
    USE SIGNAL ;
    PORT
      LAYER M3 ;
        RECT  10.008 36.576 10.026 36.72 ;
    END
  END dq[46]
  PIN dq[470]
    DIRECTION OUTPUT ;
    USE SIGNAL ;
    PORT
      LAYER M3 ;
        RECT  61.884 36.576 61.902 36.72 ;
    END
  END dq[470]
  PIN dq[471]
    DIRECTION OUTPUT ;
    USE SIGNAL ;
    PORT
      LAYER M5 ;
        RECT  62.016 36.528 62.04 36.72 ;
    END
  END dq[471]
  PIN dq[472]
    DIRECTION OUTPUT ;
    USE SIGNAL ;
    PORT
      LAYER M3 ;
        RECT  62.136 36.576 62.154 36.72 ;
    END
  END dq[472]
  PIN dq[473]
    DIRECTION OUTPUT ;
    USE SIGNAL ;
    PORT
      LAYER M5 ;
        RECT  62.256 36.528 62.28 36.72 ;
    END
  END dq[473]
  PIN dq[474]
    DIRECTION OUTPUT ;
    USE SIGNAL ;
    PORT
      LAYER M3 ;
        RECT  62.352 36.576 62.37 36.72 ;
    END
  END dq[474]
  PIN dq[475]
    DIRECTION OUTPUT ;
    USE SIGNAL ;
    PORT
      LAYER M5 ;
        RECT  62.496 36.528 62.52 36.72 ;
    END
  END dq[475]
  PIN dq[476]
    DIRECTION OUTPUT ;
    USE SIGNAL ;
    PORT
      LAYER M3 ;
        RECT  62.604 36.576 62.622 36.72 ;
    END
  END dq[476]
  PIN dq[477]
    DIRECTION OUTPUT ;
    USE SIGNAL ;
    PORT
      LAYER M5 ;
        RECT  62.736 36.528 62.76 36.72 ;
    END
  END dq[477]
  PIN dq[478]
    DIRECTION OUTPUT ;
    USE SIGNAL ;
    PORT
      LAYER M3 ;
        RECT  62.856 36.576 62.874 36.72 ;
    END
  END dq[478]
  PIN dq[479]
    DIRECTION OUTPUT ;
    USE SIGNAL ;
    PORT
      LAYER M5 ;
        RECT  62.976 36.528 63 36.72 ;
    END
  END dq[479]
  PIN dq[47]
    DIRECTION OUTPUT ;
    USE SIGNAL ;
    PORT
      LAYER M5 ;
        RECT  10.128 36.528 10.152 36.72 ;
    END
  END dq[47]
  PIN dq[480]
    DIRECTION OUTPUT ;
    USE SIGNAL ;
    PORT
      LAYER M3 ;
        RECT  63.108 36.576 63.126 36.72 ;
    END
  END dq[480]
  PIN dq[481]
    DIRECTION OUTPUT ;
    USE SIGNAL ;
    PORT
      LAYER M5 ;
        RECT  63.216 36.528 63.24 36.72 ;
    END
  END dq[481]
  PIN dq[482]
    DIRECTION OUTPUT ;
    USE SIGNAL ;
    PORT
      LAYER M3 ;
        RECT  63.324 36.576 63.342 36.72 ;
    END
  END dq[482]
  PIN dq[483]
    DIRECTION OUTPUT ;
    USE SIGNAL ;
    PORT
      LAYER M5 ;
        RECT  63.456 36.528 63.48 36.72 ;
    END
  END dq[483]
  PIN dq[484]
    DIRECTION OUTPUT ;
    USE SIGNAL ;
    PORT
      LAYER M3 ;
        RECT  63.576 36.576 63.594 36.72 ;
    END
  END dq[484]
  PIN dq[485]
    DIRECTION OUTPUT ;
    USE SIGNAL ;
    PORT
      LAYER M5 ;
        RECT  63.696 36.528 63.72 36.72 ;
    END
  END dq[485]
  PIN dq[486]
    DIRECTION OUTPUT ;
    USE SIGNAL ;
    PORT
      LAYER M3 ;
        RECT  63.828 36.576 63.846 36.72 ;
    END
  END dq[486]
  PIN dq[487]
    DIRECTION OUTPUT ;
    USE SIGNAL ;
    PORT
      LAYER M5 ;
        RECT  63.936 36.528 63.96 36.72 ;
    END
  END dq[487]
  PIN dq[488]
    DIRECTION OUTPUT ;
    USE SIGNAL ;
    PORT
      LAYER M3 ;
        RECT  64.08 36.576 64.098 36.72 ;
    END
  END dq[488]
  PIN dq[489]
    DIRECTION OUTPUT ;
    USE SIGNAL ;
    PORT
      LAYER M5 ;
        RECT  64.176 36.528 64.2 36.72 ;
    END
  END dq[489]
  PIN dq[48]
    DIRECTION OUTPUT ;
    USE SIGNAL ;
    PORT
      LAYER M3 ;
        RECT  10.26 36.576 10.278 36.72 ;
    END
  END dq[48]
  PIN dq[490]
    DIRECTION OUTPUT ;
    USE SIGNAL ;
    PORT
      LAYER M3 ;
        RECT  64.332 36.576 64.35 36.72 ;
    END
  END dq[490]
  PIN dq[491]
    DIRECTION OUTPUT ;
    USE SIGNAL ;
    PORT
      LAYER M5 ;
        RECT  64.416 36.528 64.44 36.72 ;
    END
  END dq[491]
  PIN dq[492]
    DIRECTION OUTPUT ;
    USE SIGNAL ;
    PORT
      LAYER M3 ;
        RECT  64.548 36.576 64.566 36.72 ;
    END
  END dq[492]
  PIN dq[493]
    DIRECTION OUTPUT ;
    USE SIGNAL ;
    PORT
      LAYER M5 ;
        RECT  64.704 36.528 64.728 36.72 ;
    END
  END dq[493]
  PIN dq[494]
    DIRECTION OUTPUT ;
    USE SIGNAL ;
    PORT
      LAYER M3 ;
        RECT  64.8 36.576 64.818 36.72 ;
    END
  END dq[494]
  PIN dq[495]
    DIRECTION OUTPUT ;
    USE SIGNAL ;
    PORT
      LAYER M5 ;
        RECT  64.944 36.528 64.968 36.72 ;
    END
  END dq[495]
  PIN dq[496]
    DIRECTION OUTPUT ;
    USE SIGNAL ;
    PORT
      LAYER M3 ;
        RECT  65.052 36.576 65.07 36.72 ;
    END
  END dq[496]
  PIN dq[497]
    DIRECTION OUTPUT ;
    USE SIGNAL ;
    PORT
      LAYER M5 ;
        RECT  65.184 36.528 65.208 36.72 ;
    END
  END dq[497]
  PIN dq[498]
    DIRECTION OUTPUT ;
    USE SIGNAL ;
    PORT
      LAYER M3 ;
        RECT  65.304 36.576 65.322 36.72 ;
    END
  END dq[498]
  PIN dq[499]
    DIRECTION OUTPUT ;
    USE SIGNAL ;
    PORT
      LAYER M5 ;
        RECT  65.424 36.528 65.448 36.72 ;
    END
  END dq[499]
  PIN dq[49]
    DIRECTION OUTPUT ;
    USE SIGNAL ;
    PORT
      LAYER M5 ;
        RECT  10.368 36.528 10.392 36.72 ;
    END
  END dq[49]
  PIN dq[4]
    DIRECTION OUTPUT ;
    USE SIGNAL ;
    PORT
      LAYER M3 ;
        RECT  4.86 36.576 4.878 36.72 ;
    END
  END dq[4]
  PIN dq[500]
    DIRECTION OUTPUT ;
    USE SIGNAL ;
    PORT
      LAYER M3 ;
        RECT  65.556 36.576 65.574 36.72 ;
    END
  END dq[500]
  PIN dq[501]
    DIRECTION OUTPUT ;
    USE SIGNAL ;
    PORT
      LAYER M5 ;
        RECT  65.664 36.528 65.688 36.72 ;
    END
  END dq[501]
  PIN dq[502]
    DIRECTION OUTPUT ;
    USE SIGNAL ;
    PORT
      LAYER M3 ;
        RECT  65.772 36.576 65.79 36.72 ;
    END
  END dq[502]
  PIN dq[503]
    DIRECTION OUTPUT ;
    USE SIGNAL ;
    PORT
      LAYER M5 ;
        RECT  65.904 36.528 65.928 36.72 ;
    END
  END dq[503]
  PIN dq[504]
    DIRECTION OUTPUT ;
    USE SIGNAL ;
    PORT
      LAYER M3 ;
        RECT  66.024 36.576 66.042 36.72 ;
    END
  END dq[504]
  PIN dq[505]
    DIRECTION OUTPUT ;
    USE SIGNAL ;
    PORT
      LAYER M5 ;
        RECT  66.144 36.528 66.168 36.72 ;
    END
  END dq[505]
  PIN dq[506]
    DIRECTION OUTPUT ;
    USE SIGNAL ;
    PORT
      LAYER M3 ;
        RECT  66.276 36.576 66.294 36.72 ;
    END
  END dq[506]
  PIN dq[507]
    DIRECTION OUTPUT ;
    USE SIGNAL ;
    PORT
      LAYER M5 ;
        RECT  66.384 36.528 66.408 36.72 ;
    END
  END dq[507]
  PIN dq[508]
    DIRECTION OUTPUT ;
    USE SIGNAL ;
    PORT
      LAYER M3 ;
        RECT  66.528 36.576 66.546 36.72 ;
    END
  END dq[508]
  PIN dq[509]
    DIRECTION OUTPUT ;
    USE SIGNAL ;
    PORT
      LAYER M5 ;
        RECT  66.624 36.528 66.648 36.72 ;
    END
  END dq[509]
  PIN dq[50]
    DIRECTION OUTPUT ;
    USE SIGNAL ;
    PORT
      LAYER M3 ;
        RECT  10.476 36.576 10.494 36.72 ;
    END
  END dq[50]
  PIN dq[510]
    DIRECTION OUTPUT ;
    USE SIGNAL ;
    PORT
      LAYER M3 ;
        RECT  66.78 36.576 66.798 36.72 ;
    END
  END dq[510]
  PIN dq[511]
    DIRECTION OUTPUT ;
    USE SIGNAL ;
    PORT
      LAYER M5 ;
        RECT  66.864 36.528 66.888 36.72 ;
    END
  END dq[511]
  PIN dq[51]
    DIRECTION OUTPUT ;
    USE SIGNAL ;
    PORT
      LAYER M5 ;
        RECT  10.608 36.528 10.632 36.72 ;
    END
  END dq[51]
  PIN dq[52]
    DIRECTION OUTPUT ;
    USE SIGNAL ;
    PORT
      LAYER M3 ;
        RECT  10.728 36.576 10.746 36.72 ;
    END
  END dq[52]
  PIN dq[53]
    DIRECTION OUTPUT ;
    USE SIGNAL ;
    PORT
      LAYER M5 ;
        RECT  10.848 36.528 10.872 36.72 ;
    END
  END dq[53]
  PIN dq[54]
    DIRECTION OUTPUT ;
    USE SIGNAL ;
    PORT
      LAYER M3 ;
        RECT  10.98 36.576 10.998 36.72 ;
    END
  END dq[54]
  PIN dq[55]
    DIRECTION OUTPUT ;
    USE SIGNAL ;
    PORT
      LAYER M5 ;
        RECT  11.088 36.528 11.112 36.72 ;
    END
  END dq[55]
  PIN dq[56]
    DIRECTION OUTPUT ;
    USE SIGNAL ;
    PORT
      LAYER M3 ;
        RECT  11.232 36.576 11.25 36.72 ;
    END
  END dq[56]
  PIN dq[57]
    DIRECTION OUTPUT ;
    USE SIGNAL ;
    PORT
      LAYER M5 ;
        RECT  11.328 36.528 11.352 36.72 ;
    END
  END dq[57]
  PIN dq[58]
    DIRECTION OUTPUT ;
    USE SIGNAL ;
    PORT
      LAYER M3 ;
        RECT  11.484 36.576 11.502 36.72 ;
    END
  END dq[58]
  PIN dq[59]
    DIRECTION OUTPUT ;
    USE SIGNAL ;
    PORT
      LAYER M5 ;
        RECT  11.568 36.528 11.592 36.72 ;
    END
  END dq[59]
  PIN dq[5]
    DIRECTION OUTPUT ;
    USE SIGNAL ;
    PORT
      LAYER M5 ;
        RECT  4.992 36.528 5.016 36.72 ;
    END
  END dq[5]
  PIN dq[60]
    DIRECTION OUTPUT ;
    USE SIGNAL ;
    PORT
      LAYER M3 ;
        RECT  11.7 36.576 11.718 36.72 ;
    END
  END dq[60]
  PIN dq[61]
    DIRECTION OUTPUT ;
    USE SIGNAL ;
    PORT
      LAYER M5 ;
        RECT  11.856 36.528 11.88 36.72 ;
    END
  END dq[61]
  PIN dq[62]
    DIRECTION OUTPUT ;
    USE SIGNAL ;
    PORT
      LAYER M3 ;
        RECT  11.952 36.576 11.97 36.72 ;
    END
  END dq[62]
  PIN dq[63]
    DIRECTION OUTPUT ;
    USE SIGNAL ;
    PORT
      LAYER M5 ;
        RECT  12.096 36.528 12.12 36.72 ;
    END
  END dq[63]
  PIN dq[64]
    DIRECTION OUTPUT ;
    USE SIGNAL ;
    PORT
      LAYER M3 ;
        RECT  12.204 36.576 12.222 36.72 ;
    END
  END dq[64]
  PIN dq[65]
    DIRECTION OUTPUT ;
    USE SIGNAL ;
    PORT
      LAYER M5 ;
        RECT  12.336 36.528 12.36 36.72 ;
    END
  END dq[65]
  PIN dq[66]
    DIRECTION OUTPUT ;
    USE SIGNAL ;
    PORT
      LAYER M3 ;
        RECT  12.456 36.576 12.474 36.72 ;
    END
  END dq[66]
  PIN dq[67]
    DIRECTION OUTPUT ;
    USE SIGNAL ;
    PORT
      LAYER M5 ;
        RECT  12.576 36.528 12.6 36.72 ;
    END
  END dq[67]
  PIN dq[68]
    DIRECTION OUTPUT ;
    USE SIGNAL ;
    PORT
      LAYER M3 ;
        RECT  12.708 36.576 12.726 36.72 ;
    END
  END dq[68]
  PIN dq[69]
    DIRECTION OUTPUT ;
    USE SIGNAL ;
    PORT
      LAYER M5 ;
        RECT  12.816 36.528 12.84 36.72 ;
    END
  END dq[69]
  PIN dq[6]
    DIRECTION OUTPUT ;
    USE SIGNAL ;
    PORT
      LAYER M3 ;
        RECT  5.112 36.576 5.13 36.72 ;
    END
  END dq[6]
  PIN dq[70]
    DIRECTION OUTPUT ;
    USE SIGNAL ;
    PORT
      LAYER M3 ;
        RECT  12.924 36.576 12.942 36.72 ;
    END
  END dq[70]
  PIN dq[71]
    DIRECTION OUTPUT ;
    USE SIGNAL ;
    PORT
      LAYER M5 ;
        RECT  13.056 36.528 13.08 36.72 ;
    END
  END dq[71]
  PIN dq[72]
    DIRECTION OUTPUT ;
    USE SIGNAL ;
    PORT
      LAYER M3 ;
        RECT  13.176 36.576 13.194 36.72 ;
    END
  END dq[72]
  PIN dq[73]
    DIRECTION OUTPUT ;
    USE SIGNAL ;
    PORT
      LAYER M5 ;
        RECT  13.296 36.528 13.32 36.72 ;
    END
  END dq[73]
  PIN dq[74]
    DIRECTION OUTPUT ;
    USE SIGNAL ;
    PORT
      LAYER M3 ;
        RECT  13.428 36.576 13.446 36.72 ;
    END
  END dq[74]
  PIN dq[75]
    DIRECTION OUTPUT ;
    USE SIGNAL ;
    PORT
      LAYER M5 ;
        RECT  13.536 36.528 13.56 36.72 ;
    END
  END dq[75]
  PIN dq[76]
    DIRECTION OUTPUT ;
    USE SIGNAL ;
    PORT
      LAYER M3 ;
        RECT  13.68 36.576 13.698 36.72 ;
    END
  END dq[76]
  PIN dq[77]
    DIRECTION OUTPUT ;
    USE SIGNAL ;
    PORT
      LAYER M5 ;
        RECT  13.776 36.528 13.8 36.72 ;
    END
  END dq[77]
  PIN dq[78]
    DIRECTION OUTPUT ;
    USE SIGNAL ;
    PORT
      LAYER M3 ;
        RECT  13.932 36.576 13.95 36.72 ;
    END
  END dq[78]
  PIN dq[79]
    DIRECTION OUTPUT ;
    USE SIGNAL ;
    PORT
      LAYER M5 ;
        RECT  14.016 36.528 14.04 36.72 ;
    END
  END dq[79]
  PIN dq[7]
    DIRECTION OUTPUT ;
    USE SIGNAL ;
    PORT
      LAYER M5 ;
        RECT  5.232 36.528 5.256 36.72 ;
    END
  END dq[7]
  PIN dq[80]
    DIRECTION OUTPUT ;
    USE SIGNAL ;
    PORT
      LAYER M3 ;
        RECT  14.148 36.576 14.166 36.72 ;
    END
  END dq[80]
  PIN dq[81]
    DIRECTION OUTPUT ;
    USE SIGNAL ;
    PORT
      LAYER M5 ;
        RECT  14.256 36.528 14.28 36.72 ;
    END
  END dq[81]
  PIN dq[82]
    DIRECTION OUTPUT ;
    USE SIGNAL ;
    PORT
      LAYER M3 ;
        RECT  14.4 36.576 14.418 36.72 ;
    END
  END dq[82]
  PIN dq[83]
    DIRECTION OUTPUT ;
    USE SIGNAL ;
    PORT
      LAYER M5 ;
        RECT  14.544 36.528 14.568 36.72 ;
    END
  END dq[83]
  PIN dq[84]
    DIRECTION OUTPUT ;
    USE SIGNAL ;
    PORT
      LAYER M3 ;
        RECT  14.652 36.576 14.67 36.72 ;
    END
  END dq[84]
  PIN dq[85]
    DIRECTION OUTPUT ;
    USE SIGNAL ;
    PORT
      LAYER M5 ;
        RECT  14.784 36.528 14.808 36.72 ;
    END
  END dq[85]
  PIN dq[86]
    DIRECTION OUTPUT ;
    USE SIGNAL ;
    PORT
      LAYER M3 ;
        RECT  14.904 36.576 14.922 36.72 ;
    END
  END dq[86]
  PIN dq[87]
    DIRECTION OUTPUT ;
    USE SIGNAL ;
    PORT
      LAYER M5 ;
        RECT  15.024 36.528 15.048 36.72 ;
    END
  END dq[87]
  PIN dq[88]
    DIRECTION OUTPUT ;
    USE SIGNAL ;
    PORT
      LAYER M3 ;
        RECT  15.156 36.576 15.174 36.72 ;
    END
  END dq[88]
  PIN dq[89]
    DIRECTION OUTPUT ;
    USE SIGNAL ;
    PORT
      LAYER M5 ;
        RECT  15.264 36.528 15.288 36.72 ;
    END
  END dq[89]
  PIN dq[8]
    DIRECTION OUTPUT ;
    USE SIGNAL ;
    PORT
      LAYER M3 ;
        RECT  5.364 36.576 5.382 36.72 ;
    END
  END dq[8]
  PIN dq[90]
    DIRECTION OUTPUT ;
    USE SIGNAL ;
    PORT
      LAYER M3 ;
        RECT  15.372 36.576 15.39 36.72 ;
    END
  END dq[90]
  PIN dq[91]
    DIRECTION OUTPUT ;
    USE SIGNAL ;
    PORT
      LAYER M5 ;
        RECT  15.504 36.528 15.528 36.72 ;
    END
  END dq[91]
  PIN dq[92]
    DIRECTION OUTPUT ;
    USE SIGNAL ;
    PORT
      LAYER M3 ;
        RECT  15.624 36.576 15.642 36.72 ;
    END
  END dq[92]
  PIN dq[93]
    DIRECTION OUTPUT ;
    USE SIGNAL ;
    PORT
      LAYER M5 ;
        RECT  15.744 36.528 15.768 36.72 ;
    END
  END dq[93]
  PIN dq[94]
    DIRECTION OUTPUT ;
    USE SIGNAL ;
    PORT
      LAYER M3 ;
        RECT  15.876 36.576 15.894 36.72 ;
    END
  END dq[94]
  PIN dq[95]
    DIRECTION OUTPUT ;
    USE SIGNAL ;
    PORT
      LAYER M5 ;
        RECT  15.984 36.528 16.008 36.72 ;
    END
  END dq[95]
  PIN dq[96]
    DIRECTION OUTPUT ;
    USE SIGNAL ;
    PORT
      LAYER M3 ;
        RECT  16.128 36.576 16.146 36.72 ;
    END
  END dq[96]
  PIN dq[97]
    DIRECTION OUTPUT ;
    USE SIGNAL ;
    PORT
      LAYER M5 ;
        RECT  16.224 36.528 16.248 36.72 ;
    END
  END dq[97]
  PIN dq[98]
    DIRECTION OUTPUT ;
    USE SIGNAL ;
    PORT
      LAYER M3 ;
        RECT  16.344 36.576 16.362 36.72 ;
    END
  END dq[98]
  PIN dq[99]
    DIRECTION OUTPUT ;
    USE SIGNAL ;
    PORT
      LAYER M5 ;
        RECT  16.464 36.528 16.488 36.72 ;
    END
  END dq[99]
  PIN dq[9]
    DIRECTION OUTPUT ;
    USE SIGNAL ;
    PORT
      LAYER M5 ;
        RECT  5.472 36.528 5.496 36.72 ;
    END
  END dq[9]
  PIN VDD
    DIRECTION INOUT ;
    USE POWER ;
    PORT
      LAYER M5 ;
        RECT  67.392 2.151 67.512 34.569 ;
        RECT  64.692 2.151 64.812 34.569 ;
        RECT  61.992 2.151 62.112 34.569 ;
        RECT  59.292 2.151 59.412 34.569 ;
        RECT  56.592 2.151 56.712 34.569 ;
        RECT  53.892 2.151 54.012 34.569 ;
        RECT  51.192 2.151 51.312 34.569 ;
        RECT  48.492 2.151 48.612 34.569 ;
        RECT  45.792 2.151 45.912 34.569 ;
        RECT  43.092 2.151 43.212 34.569 ;
        RECT  40.392 2.151 40.512 34.569 ;
        RECT  37.692 2.151 37.812 34.569 ;
        RECT  34.992 2.151 35.112 34.569 ;
        RECT  32.292 2.151 32.412 34.569 ;
        RECT  29.592 2.151 29.712 34.569 ;
        RECT  26.892 2.151 27.012 34.569 ;
        RECT  24.192 2.151 24.312 34.569 ;
        RECT  21.492 2.151 21.612 34.569 ;
        RECT  18.792 2.151 18.912 34.569 ;
        RECT  16.092 2.151 16.212 34.569 ;
        RECT  13.392 2.151 13.512 34.569 ;
        RECT  10.692 2.151 10.812 34.569 ;
        RECT  7.992 2.151 8.112 34.569 ;
        RECT  5.292 2.151 5.412 34.569 ;
        RECT  2.592 2.151 2.712 34.569 ;
    END
  END VDD
  PIN VSS
    DIRECTION INOUT ;
    USE GROUND ;
    PORT
      LAYER M5 ;
        RECT  67.2 2.137 67.32 34.583 ;
        RECT  64.5 2.137 64.62 34.583 ;
        RECT  61.8 2.137 61.92 34.583 ;
        RECT  59.1 2.137 59.22 34.583 ;
        RECT  56.4 2.137 56.52 34.583 ;
        RECT  53.7 2.137 53.82 34.583 ;
        RECT  51 2.137 51.12 34.583 ;
        RECT  48.3 2.137 48.42 34.583 ;
        RECT  45.6 2.137 45.72 34.583 ;
        RECT  42.9 2.137 43.02 34.583 ;
        RECT  40.2 2.137 40.32 34.583 ;
        RECT  37.5 2.137 37.62 34.583 ;
        RECT  34.8 2.137 34.92 34.583 ;
        RECT  32.1 2.137 32.22 34.583 ;
        RECT  29.4 2.137 29.52 34.583 ;
        RECT  26.7 2.137 26.82 34.583 ;
        RECT  24 2.137 24.12 34.583 ;
        RECT  21.3 2.137 21.42 34.583 ;
        RECT  18.6 2.137 18.72 34.583 ;
        RECT  15.9 2.137 16.02 34.583 ;
        RECT  13.2 2.137 13.32 34.583 ;
        RECT  10.5 2.137 10.62 34.583 ;
        RECT  7.8 2.137 7.92 34.583 ;
        RECT  5.1 2.137 5.22 34.583 ;
        RECT  2.4 2.137 2.52 34.583 ;
    END
  END VSS
  # OT_OBS_CLOSED layer=M5 d_um=1.536 added=99
  OBS
    LAYER RVTN ;
     RECT  2.16 2.16 69.12 2.295 ;
     RECT  2.16 2.565 69.12 2.835 ;
     RECT  2.16 3.105 69.12 3.375 ;
     RECT  2.16 3.645 69.12 3.915 ;
     RECT  2.16 4.185 69.12 4.455 ;
     RECT  2.16 4.725 69.12 4.995 ;
     RECT  2.16 5.265 69.12 5.535 ;
     RECT  2.16 5.805 69.12 6.075 ;
     RECT  2.16 6.345 69.12 6.615 ;
     RECT  2.16 6.885 69.12 7.155 ;
     RECT  2.16 7.425 69.12 7.695 ;
     RECT  2.16 7.965 69.12 8.235 ;
     RECT  2.16 8.505 69.12 8.775 ;
     RECT  2.16 9.045 69.12 9.315 ;
     RECT  2.16 9.585 69.12 9.855 ;
     RECT  2.16 10.125 69.12 10.395 ;
     RECT  2.16 10.665 69.12 10.935 ;
     RECT  2.16 11.205 69.12 11.475 ;
     RECT  2.16 11.745 69.12 12.015 ;
     RECT  2.16 12.285 69.12 12.555 ;
     RECT  2.16 12.825 69.12 13.095 ;
     RECT  2.16 13.365 69.12 13.635 ;
     RECT  2.16 13.905 69.12 14.175 ;
     RECT  2.16 14.445 69.12 14.715 ;
     RECT  2.16 14.985 69.12 15.255 ;
     RECT  2.16 15.525 69.12 15.795 ;
     RECT  2.16 16.065 69.12 16.335 ;
     RECT  2.16 16.605 69.12 16.875 ;
     RECT  2.16 17.145 69.12 17.415 ;
     RECT  2.16 17.685 69.12 17.955 ;
     RECT  2.16 18.225 69.12 18.495 ;
     RECT  2.16 18.765 69.12 19.035 ;
     RECT  2.16 19.305 69.12 19.575 ;
     RECT  2.16 19.845 69.12 20.115 ;
     RECT  2.16 20.385 69.12 20.655 ;
     RECT  2.16 20.925 69.12 21.195 ;
     RECT  2.16 21.465 69.12 21.735 ;
     RECT  2.16 22.005 69.12 22.275 ;
     RECT  2.16 22.545 69.12 22.815 ;
     RECT  2.16 23.085 69.12 23.355 ;
     RECT  2.16 23.625 69.12 23.895 ;
     RECT  2.16 24.165 69.12 24.435 ;
     RECT  2.16 24.705 69.12 24.975 ;
     RECT  2.16 25.245 69.12 25.515 ;
     RECT  2.16 25.785 69.12 26.055 ;
     RECT  2.16 26.325 69.12 26.595 ;
     RECT  2.16 26.865 69.12 27.135 ;
     RECT  2.16 27.405 69.12 27.675 ;
     RECT  2.16 27.945 69.12 28.215 ;
     RECT  2.16 28.485 69.12 28.755 ;
     RECT  2.16 29.025 69.12 29.295 ;
     RECT  2.16 29.565 69.12 29.835 ;
     RECT  2.16 30.105 69.12 30.375 ;
     RECT  2.16 30.645 69.12 30.915 ;
     RECT  2.16 31.185 69.12 31.455 ;
     RECT  2.16 31.725 69.12 31.995 ;
     RECT  2.16 32.265 69.12 32.535 ;
     RECT  2.16 32.805 69.12 33.075 ;
     RECT  2.16 33.345 69.12 33.615 ;
     RECT  2.16 33.885 69.12 34.155 ;
     RECT  2.16 34.425 69.12 34.56 ;
    LAYER RVTP ;
     RECT  2.16 2.295 69.12 2.565 ;
     RECT  2.16 2.835 69.12 3.105 ;
     RECT  2.16 3.375 69.12 3.645 ;
     RECT  2.16 3.915 69.12 4.185 ;
     RECT  2.16 4.455 69.12 4.725 ;
     RECT  2.16 4.995 69.12 5.265 ;
     RECT  2.16 5.535 69.12 5.805 ;
     RECT  2.16 6.075 69.12 6.345 ;
     RECT  2.16 6.615 69.12 6.885 ;
     RECT  2.16 7.155 69.12 7.425 ;
     RECT  2.16 7.695 69.12 7.965 ;
     RECT  2.16 8.235 69.12 8.505 ;
     RECT  2.16 8.775 69.12 9.045 ;
     RECT  2.16 9.315 69.12 9.585 ;
     RECT  2.16 9.855 69.12 10.125 ;
     RECT  2.16 10.395 69.12 10.665 ;
     RECT  2.16 10.935 69.12 11.205 ;
     RECT  2.16 11.475 69.12 11.745 ;
     RECT  2.16 12.015 69.12 12.285 ;
     RECT  2.16 12.555 69.12 12.825 ;
     RECT  2.16 13.095 69.12 13.365 ;
     RECT  2.16 13.635 69.12 13.905 ;
     RECT  2.16 14.175 69.12 14.445 ;
     RECT  2.16 14.715 69.12 14.985 ;
     RECT  2.16 15.255 69.12 15.525 ;
     RECT  2.16 15.795 69.12 16.065 ;
     RECT  2.16 16.335 69.12 16.605 ;
     RECT  2.16 16.875 69.12 17.145 ;
     RECT  2.16 17.415 69.12 17.685 ;
     RECT  2.16 17.955 69.12 18.225 ;
     RECT  2.16 18.495 69.12 18.765 ;
     RECT  2.16 19.035 69.12 19.305 ;
     RECT  2.16 19.575 69.12 19.845 ;
     RECT  2.16 20.115 69.12 20.385 ;
     RECT  2.16 20.655 69.12 20.925 ;
     RECT  2.16 21.195 69.12 21.465 ;
     RECT  2.16 21.735 69.12 22.005 ;
     RECT  2.16 22.275 69.12 22.545 ;
     RECT  2.16 22.815 69.12 23.085 ;
     RECT  2.16 23.355 69.12 23.625 ;
     RECT  2.16 23.895 69.12 24.165 ;
     RECT  2.16 24.435 69.12 24.705 ;
     RECT  2.16 24.975 69.12 25.245 ;
     RECT  2.16 25.515 69.12 25.785 ;
     RECT  2.16 26.055 69.12 26.325 ;
     RECT  2.16 26.595 69.12 26.865 ;
     RECT  2.16 27.135 69.12 27.405 ;
     RECT  2.16 27.675 69.12 27.945 ;
     RECT  2.16 28.215 69.12 28.485 ;
     RECT  2.16 28.755 69.12 29.025 ;
     RECT  2.16 29.295 69.12 29.565 ;
     RECT  2.16 29.835 69.12 30.105 ;
     RECT  2.16 30.375 69.12 30.645 ;
     RECT  2.16 30.915 69.12 31.185 ;
     RECT  2.16 31.455 69.12 31.725 ;
     RECT  2.16 31.995 69.12 32.265 ;
     RECT  2.16 32.535 69.12 32.805 ;
     RECT  2.16 33.075 69.12 33.345 ;
     RECT  2.16 33.615 69.12 33.885 ;
     RECT  2.16 34.155 69.12 34.425 ;
    LAYER M1 ;
     RECT  2.16 2.151 69.12 34.569 ;
    LAYER M2 ;
     RECT  2.16 2.151 4.603 34.569 ;
     RECT  4.603 2.151 4.955 34.794 ;
     RECT  4.999 36.558 5.099 36.648 ;
     RECT  5.035 0.144 5.135 0.162 ;
     RECT  5.099 36.558 5.135 36.576 ;
     RECT  4.955 2.151 7.699 34.569 ;
     RECT  7.699 2.151 7.835 34.65 ;
     RECT  7.835 2.151 8.527 34.569 ;
     RECT  8.527 1.728 8.699 34.569 ;
     RECT  7.735 0.144 8.879 0.162 ;
     RECT  8.699 2.151 10.723 34.569 ;
     RECT  10.723 1.728 10.859 34.569 ;
     RECT  10.975 35.982 11.147 36 ;
     RECT  11.227 0.144 11.327 0.162 ;
     RECT  12.451 0.144 12.551 0.162 ;
     RECT  10.859 2.151 13.171 34.569 ;
     RECT  13.171 1.728 13.559 34.569 ;
     RECT  13.559 2.106 13.595 34.569 ;
     RECT  16.123 0.144 16.259 0.162 ;
     RECT  13.595 2.151 16.519 34.569 ;
     RECT  16.339 35.901 16.835 35.919 ;
     RECT  16.519 2.106 16.879 34.569 ;
     RECT  16.879 2.07 17.095 34.569 ;
     RECT  17.095 2.07 17.483 34.794 ;
     RECT  17.483 2.106 17.663 34.794 ;
     RECT  17.275 0.144 18.383 0.162 ;
     RECT  17.663 2.151 18.427 34.794 ;
     RECT  18.427 2.151 18.815 34.839 ;
     RECT  18.815 2.151 19.543 34.569 ;
     RECT  19.291 35.901 19.751 35.919 ;
     RECT  19.543 1.728 19.795 34.569 ;
     RECT  19.795 1.728 19.895 34.839 ;
     RECT  19.895 1.728 20.399 34.794 ;
     RECT  20.399 2.151 20.471 34.794 ;
     RECT  21.451 36.63 21.487 36.648 ;
     RECT  21.487 36.558 21.587 36.648 ;
     RECT  20.471 2.151 21.991 34.569 ;
     RECT  21.991 0.144 22.199 0.162 ;
     RECT  21.991 2.151 22.631 34.794 ;
     RECT  23.467 36.558 23.503 36.576 ;
     RECT  23.503 36.558 23.603 36.648 ;
     RECT  22.631 2.151 23.935 34.569 ;
     RECT  23.935 2.151 24.187 34.794 ;
     RECT  24.187 0.144 24.359 0.162 ;
     RECT  24.187 2.151 24.359 34.839 ;
     RECT  24.359 2.151 24.395 34.794 ;
     RECT  24.395 2.151 24.439 34.569 ;
     RECT  24.439 1.728 24.899 34.569 ;
     RECT  24.899 2.151 25.159 34.569 ;
     RECT  25.159 2.151 25.403 34.839 ;
     RECT  25.403 2.151 25.619 34.758 ;
     RECT  25.619 2.151 26.383 34.569 ;
     RECT  26.383 2.151 26.635 34.794 ;
     RECT  26.635 2.151 26.771 34.884 ;
     RECT  26.887 0.144 27.059 0.162 ;
     RECT  26.771 2.151 27.131 34.794 ;
     RECT  27.131 2.151 28.579 34.569 ;
     RECT  28.579 2.151 29.155 34.794 ;
     RECT  29.155 2.151 29.263 34.839 ;
     RECT  28.579 0.144 29.363 0.162 ;
     RECT  29.371 0.216 29.615 0.234 ;
     RECT  29.263 2.151 29.615 34.884 ;
     RECT  29.615 2.151 31.027 34.569 ;
     RECT  31.027 2.151 31.207 34.794 ;
     RECT  31.207 2.151 31.307 34.884 ;
     RECT  31.307 2.151 31.343 34.839 ;
     RECT  31.343 2.151 32.099 34.794 ;
     RECT  32.755 0.144 32.855 0.162 ;
     RECT  33.727 36.558 33.763 36.576 ;
     RECT  33.763 36.558 33.863 36.648 ;
     RECT  32.099 2.151 34.447 34.569 ;
     RECT  34.447 2.151 35.203 34.794 ;
     RECT  35.383 0.144 35.483 0.162 ;
     RECT  35.203 1.728 35.843 34.794 ;
     RECT  35.843 1.728 36.023 34.758 ;
     RECT  36.023 2.151 36.311 34.758 ;
     RECT  36.355 0.144 36.455 0.162 ;
     RECT  36.311 2.151 38.119 34.569 ;
     RECT  37.399 0.576 38.327 0.594 ;
     RECT  38.119 1.728 38.371 34.569 ;
     RECT  38.371 1.728 38.435 34.794 ;
     RECT  38.435 2.151 39.595 34.794 ;
     RECT  40.027 0.144 40.127 0.162 ;
     RECT  39.595 1.728 40.127 34.794 ;
     RECT  40.819 35.901 41.387 35.919 ;
     RECT  40.127 2.151 41.459 34.794 ;
     RECT  41.459 2.151 42.799 34.569 ;
     RECT  42.799 2.151 42.835 34.794 ;
     RECT  42.835 2.151 43.043 34.839 ;
     RECT  43.043 2.151 43.259 34.794 ;
     RECT  43.267 0.576 44.231 0.594 ;
     RECT  43.259 2.151 44.491 34.569 ;
     RECT  44.491 2.151 45.103 34.794 ;
     RECT  44.239 35.901 45.347 35.919 ;
     RECT  45.103 2.106 45.599 34.794 ;
     RECT  45.599 2.151 45.967 34.794 ;
     RECT  45.967 2.151 46.139 34.884 ;
     RECT  46.139 2.151 46.939 34.569 ;
     RECT  46.939 2.151 47.183 34.794 ;
     RECT  46.687 35.946 47.191 35.964 ;
     RECT  45.715 0.144 47.291 0.162 ;
     RECT  47.191 35.901 47.507 35.964 ;
     RECT  47.507 35.901 47.723 35.919 ;
     RECT  47.183 2.151 48.055 34.569 ;
     RECT  48.055 2.151 48.443 34.794 ;
     RECT  48.443 2.151 48.883 34.569 ;
     RECT  48.883 1.728 49.127 34.569 ;
     RECT  48.883 35.901 49.379 35.919 ;
     RECT  49.127 2.151 49.387 34.569 ;
     RECT  49.387 0.144 49.487 0.162 ;
     RECT  49.387 2.151 50.171 34.794 ;
     RECT  50.171 2.151 51.115 34.569 ;
     RECT  50.863 35.901 51.115 35.919 ;
     RECT  51.115 1.728 51.331 34.569 ;
     RECT  51.331 1.728 51.575 34.794 ;
     RECT  51.575 2.151 51.583 34.794 ;
     RECT  51.583 2.151 51.791 34.884 ;
     RECT  51.115 35.901 51.835 35.964 ;
     RECT  51.835 35.901 51.935 36.036 ;
     RECT  51.935 35.946 52.007 36.036 ;
     RECT  52.007 36.018 52.151 36.036 ;
     RECT  51.791 2.151 52.555 34.569 ;
     RECT  52.555 2.151 53.015 34.794 ;
     RECT  52.339 0.144 53.411 0.162 ;
     RECT  53.311 36.018 53.411 36.036 ;
     RECT  53.015 2.151 53.779 34.569 ;
     RECT  53.779 1.728 54.095 34.65 ;
     RECT  54.095 1.728 54.383 34.569 ;
     RECT  54.383 1.8 54.527 34.569 ;
     RECT  54.031 35.901 54.635 35.919 ;
     RECT  54.527 2.151 56.479 34.569 ;
     RECT  56.479 2.151 56.795 34.65 ;
     RECT  57.451 1.152 57.551 1.17 ;
     RECT  57.703 0.144 57.803 0.162 ;
     RECT  56.983 35.901 57.875 35.919 ;
     RECT  56.795 2.151 59.071 34.569 ;
     RECT  59.071 2.151 59.207 34.65 ;
     RECT  59.071 1.152 59.279 1.17 ;
     RECT  59.179 0.144 59.531 0.162 ;
     RECT  59.683 35.901 60.295 35.919 ;
     RECT  60.295 35.901 60.971 35.964 ;
     RECT  60.971 35.946 61.331 35.964 ;
     RECT  59.207 2.151 61.627 34.569 ;
     RECT  61.627 2.151 61.979 34.794 ;
     RECT  61.879 0.144 62.267 0.162 ;
     RECT  61.979 2.151 62.851 34.758 ;
     RECT  62.851 1.728 63.275 34.839 ;
     RECT  63.275 1.728 63.419 34.794 ;
     RECT  63.419 1.8 63.455 34.794 ;
     RECT  63.571 35.982 63.743 36 ;
     RECT  63.455 2.151 64.075 34.794 ;
     RECT  64.075 0.144 64.327 0.162 ;
     RECT  64.075 2.151 64.895 34.839 ;
     RECT  64.327 0.144 65.075 0.594 ;
     RECT  65.075 0.144 65.183 0.162 ;
     RECT  64.895 2.151 65.767 34.569 ;
     RECT  65.767 2.151 65.939 34.794 ;
     RECT  65.939 2.151 66.019 34.569 ;
     RECT  66.019 1.728 66.155 34.569 ;
     RECT  65.299 35.901 66.695 35.919 ;
     RECT  66.155 2.106 66.775 34.569 ;
     RECT  66.775 2.106 67.127 34.794 ;
     RECT  67.127 2.106 68.459 34.569 ;
     RECT  68.459 2.151 69.12 34.569 ;
    LAYER M3 ;
     RECT  4.374 0.108 4.608 0.144 ;
     RECT  4.626 0.108 4.86 0.144 ;
     RECT  4.878 0.108 5.112 0.144 ;
     RECT  5.13 0.108 5.364 0.144 ;
     RECT  5.382 0.108 5.58 0.144 ;
     RECT  5.598 0.108 5.832 0.144 ;
     RECT  5.85 0.108 6.084 0.144 ;
     RECT  6.102 0.108 6.336 0.144 ;
     RECT  6.354 0.108 6.588 0.144 ;
     RECT  6.606 0.108 6.804 0.144 ;
     RECT  6.822 0.108 7.056 0.144 ;
     RECT  7.074 0.108 7.308 0.144 ;
     RECT  7.326 0.108 7.56 0.144 ;
     RECT  7.578 0.108 7.812 0.144 ;
     RECT  7.83 0.108 8.028 0.144 ;
     RECT  8.046 0.108 8.28 0.144 ;
     RECT  8.298 0.108 8.532 0.144 ;
     RECT  8.55 0.108 8.784 0.144 ;
     RECT  8.802 0.108 9.036 0.144 ;
     RECT  9.054 0.108 9.252 0.144 ;
     RECT  9.27 0.108 9.504 0.144 ;
     RECT  9.522 0.108 9.756 0.144 ;
     RECT  9.774 0.108 10.008 0.144 ;
     RECT  10.026 0.108 10.26 0.144 ;
     RECT  10.278 0.108 10.476 0.144 ;
     RECT  10.494 0.108 10.728 0.144 ;
     RECT  10.746 0.108 10.98 0.144 ;
     RECT  10.998 0.108 11.232 0.144 ;
     RECT  11.25 0.108 11.484 0.144 ;
     RECT  11.502 0.108 11.7 0.144 ;
     RECT  11.718 0.108 11.952 0.144 ;
     RECT  11.97 0.108 12.204 0.144 ;
     RECT  12.222 0.108 12.456 0.144 ;
     RECT  12.474 0.108 12.708 0.144 ;
     RECT  12.726 0.108 12.924 0.144 ;
     RECT  12.942 0.108 13.176 0.144 ;
     RECT  13.194 0.108 13.428 0.144 ;
     RECT  13.446 0.108 13.68 0.144 ;
     RECT  13.698 0.108 13.932 0.144 ;
     RECT  13.95 0.108 14.148 0.144 ;
     RECT  14.166 0.108 14.4 0.144 ;
     RECT  14.418 0.108 14.652 0.144 ;
     RECT  14.67 0.108 14.904 0.144 ;
     RECT  14.922 0.108 15.156 0.144 ;
     RECT  15.174 0.108 15.372 0.144 ;
     RECT  15.39 0.108 15.624 0.144 ;
     RECT  15.642 0.108 15.876 0.144 ;
     RECT  15.894 0.108 16.128 0.144 ;
     RECT  16.146 0.108 16.344 0.144 ;
     RECT  16.362 0.108 16.596 0.144 ;
     RECT  16.614 0.108 16.848 0.144 ;
     RECT  16.866 0.108 17.1 0.144 ;
     RECT  17.118 0.108 17.352 0.144 ;
     RECT  17.37 0.108 17.568 0.144 ;
     RECT  17.586 0.108 17.82 0.144 ;
     RECT  17.838 0.108 18.072 0.144 ;
     RECT  18.09 0.108 18.324 0.144 ;
     RECT  18.342 0.108 18.576 0.144 ;
     RECT  18.594 0.108 18.792 0.144 ;
     RECT  18.81 0.108 19.044 0.144 ;
     RECT  19.062 0.108 19.296 0.144 ;
     RECT  19.314 0.108 19.548 0.144 ;
     RECT  19.566 0.108 19.8 0.144 ;
     RECT  19.818 0.108 20.016 0.144 ;
     RECT  20.034 0.108 20.268 0.144 ;
     RECT  20.286 0.108 20.52 0.144 ;
     RECT  20.538 0.108 20.772 0.144 ;
     RECT  20.79 0.108 21.024 0.144 ;
     RECT  21.042 0.108 21.24 0.144 ;
     RECT  21.258 0.108 21.492 0.144 ;
     RECT  21.51 0.108 21.744 0.144 ;
     RECT  21.762 0.108 21.996 0.144 ;
     RECT  22.014 0.108 22.248 0.144 ;
     RECT  22.266 0.108 22.464 0.144 ;
     RECT  22.482 0.108 22.716 0.144 ;
     RECT  22.734 0.108 22.968 0.144 ;
     RECT  22.986 0.108 23.22 0.144 ;
     RECT  23.238 0.108 23.472 0.144 ;
     RECT  23.49 0.108 23.688 0.144 ;
     RECT  23.706 0.108 23.94 0.144 ;
     RECT  23.958 0.108 24.192 0.144 ;
     RECT  24.21 0.108 24.444 0.144 ;
     RECT  24.462 0.108 24.696 0.144 ;
     RECT  24.714 0.108 24.912 0.144 ;
     RECT  24.93 0.108 25.164 0.144 ;
     RECT  25.182 0.108 25.416 0.144 ;
     RECT  25.434 0.108 25.668 0.144 ;
     RECT  25.686 0.108 25.92 0.144 ;
     RECT  25.938 0.108 26.136 0.144 ;
     RECT  26.154 0.108 26.388 0.144 ;
     RECT  26.406 0.108 26.64 0.144 ;
     RECT  26.658 0.108 26.892 0.144 ;
     RECT  26.91 0.108 27.144 0.144 ;
     RECT  27.162 0.108 27.36 0.144 ;
     RECT  27.378 0.108 27.612 0.144 ;
     RECT  27.63 0.108 27.864 0.144 ;
     RECT  27.882 0.108 28.116 0.144 ;
     RECT  28.134 0.108 28.368 0.144 ;
     RECT  28.386 0.108 28.584 0.144 ;
     RECT  28.602 0.108 28.836 0.144 ;
     RECT  28.854 0.108 29.088 0.144 ;
     RECT  29.106 0.108 29.34 0.144 ;
     RECT  29.358 0.108 29.592 0.144 ;
     RECT  29.61 0.108 29.808 0.144 ;
     RECT  29.826 0.108 30.06 0.144 ;
     RECT  30.078 0.108 30.312 0.144 ;
     RECT  30.33 0.108 30.564 0.144 ;
     RECT  30.582 0.108 30.816 0.144 ;
     RECT  30.834 0.108 31.032 0.144 ;
     RECT  31.05 0.108 31.284 0.144 ;
     RECT  31.302 0.108 31.536 0.144 ;
     RECT  31.554 0.108 31.788 0.144 ;
     RECT  31.806 0.108 32.004 0.144 ;
     RECT  32.022 0.108 32.256 0.144 ;
     RECT  32.274 0.108 32.508 0.144 ;
     RECT  32.526 0.108 32.76 0.144 ;
     RECT  32.778 0.108 33.012 0.144 ;
     RECT  33.03 0.108 33.228 0.144 ;
     RECT  33.246 0.108 33.48 0.144 ;
     RECT  33.498 0.108 33.732 0.144 ;
     RECT  33.75 0.108 33.984 0.144 ;
     RECT  34.002 0.108 34.236 0.144 ;
     RECT  34.254 0.108 34.452 0.144 ;
     RECT  34.47 0.108 34.704 0.144 ;
     RECT  34.722 0.108 34.956 0.144 ;
     RECT  34.974 0.108 35.208 0.144 ;
     RECT  35.226 0.108 35.46 0.144 ;
     RECT  35.478 0.108 35.676 0.144 ;
     RECT  35.694 0.108 35.928 0.144 ;
     RECT  35.946 0.108 36.18 0.144 ;
     RECT  36.198 0.108 36.432 0.144 ;
     RECT  36.45 0.108 36.684 0.144 ;
     RECT  36.702 0.108 36.9 0.144 ;
     RECT  36.918 0.108 37.152 0.144 ;
     RECT  37.17 0.108 37.404 0.144 ;
     RECT  37.422 0.108 37.656 0.144 ;
     RECT  37.674 0.108 37.908 0.144 ;
     RECT  37.926 0.108 38.124 0.144 ;
     RECT  38.142 0.108 38.376 0.144 ;
     RECT  38.394 0.108 38.628 0.144 ;
     RECT  38.646 0.108 38.88 0.144 ;
     RECT  38.898 0.108 39.132 0.144 ;
     RECT  39.15 0.108 39.348 0.144 ;
     RECT  39.366 0.108 39.6 0.144 ;
     RECT  39.618 0.108 39.852 0.144 ;
     RECT  39.87 0.108 40.104 0.144 ;
     RECT  40.122 0.108 40.356 0.144 ;
     RECT  40.374 0.108 40.572 0.144 ;
     RECT  40.59 0.108 40.824 0.144 ;
     RECT  40.842 0.108 41.076 0.144 ;
     RECT  41.094 0.108 41.328 0.144 ;
     RECT  41.346 0.108 41.58 0.144 ;
     RECT  41.598 0.108 41.796 0.144 ;
     RECT  41.814 0.108 42.048 0.144 ;
     RECT  42.066 0.108 42.3 0.144 ;
     RECT  42.318 0.108 42.552 0.144 ;
     RECT  42.57 0.108 42.804 0.144 ;
     RECT  42.822 0.108 43.02 0.144 ;
     RECT  43.038 0.108 43.272 0.144 ;
     RECT  43.29 0.108 43.524 0.144 ;
     RECT  43.542 0.108 43.776 0.144 ;
     RECT  43.794 0.108 44.028 0.144 ;
     RECT  44.046 0.108 44.244 0.144 ;
     RECT  44.262 0.108 44.496 0.144 ;
     RECT  44.514 0.108 44.748 0.144 ;
     RECT  44.766 0.108 45 0.144 ;
     RECT  45.018 0.108 45.252 0.144 ;
     RECT  45.27 0.108 45.468 0.144 ;
     RECT  45.486 0.108 45.72 0.144 ;
     RECT  45.738 0.108 45.972 0.144 ;
     RECT  45.99 0.108 46.224 0.144 ;
     RECT  46.242 0.108 46.476 0.144 ;
     RECT  46.494 0.108 46.692 0.144 ;
     RECT  46.71 0.108 46.944 0.144 ;
     RECT  46.962 0.108 47.196 0.144 ;
     RECT  47.214 0.108 47.448 0.144 ;
     RECT  47.466 0.108 47.664 0.144 ;
     RECT  47.682 0.108 47.916 0.144 ;
     RECT  47.934 0.108 48.168 0.144 ;
     RECT  48.186 0.108 48.42 0.144 ;
     RECT  48.438 0.108 48.672 0.144 ;
     RECT  48.69 0.108 48.888 0.144 ;
     RECT  48.906 0.108 49.14 0.144 ;
     RECT  49.158 0.108 49.392 0.144 ;
     RECT  49.41 0.108 49.644 0.144 ;
     RECT  49.662 0.108 49.896 0.144 ;
     RECT  49.914 0.108 50.112 0.144 ;
     RECT  50.13 0.108 50.364 0.144 ;
     RECT  50.382 0.108 50.616 0.144 ;
     RECT  50.634 0.108 50.868 0.144 ;
     RECT  50.886 0.108 51.12 0.144 ;
     RECT  51.138 0.108 51.336 0.144 ;
     RECT  51.354 0.108 51.588 0.144 ;
     RECT  51.606 0.108 51.84 0.144 ;
     RECT  51.858 0.108 52.092 0.144 ;
     RECT  52.11 0.108 52.344 0.144 ;
     RECT  52.362 0.108 52.56 0.144 ;
     RECT  52.578 0.108 52.812 0.144 ;
     RECT  52.83 0.108 53.064 0.144 ;
     RECT  53.082 0.108 53.316 0.144 ;
     RECT  53.334 0.108 53.568 0.144 ;
     RECT  53.586 0.108 53.784 0.144 ;
     RECT  53.802 0.108 54.036 0.144 ;
     RECT  54.054 0.108 54.288 0.144 ;
     RECT  54.306 0.108 54.54 0.144 ;
     RECT  54.558 0.108 54.792 0.144 ;
     RECT  54.81 0.108 55.008 0.144 ;
     RECT  55.026 0.108 55.26 0.144 ;
     RECT  55.278 0.108 55.512 0.144 ;
     RECT  55.53 0.108 55.764 0.144 ;
     RECT  55.782 0.108 56.016 0.144 ;
     RECT  56.034 0.108 56.232 0.144 ;
     RECT  56.25 0.108 56.484 0.144 ;
     RECT  56.502 0.108 56.736 0.144 ;
     RECT  56.754 0.108 56.988 0.144 ;
     RECT  57.006 0.108 57.24 0.144 ;
     RECT  57.258 0.108 57.456 0.144 ;
     RECT  57.474 0.108 57.708 0.144 ;
     RECT  57.726 0.108 57.96 0.144 ;
     RECT  57.978 0.108 58.212 0.144 ;
     RECT  58.23 0.108 58.464 0.144 ;
     RECT  58.482 0.108 58.68 0.144 ;
     RECT  58.698 0.108 58.932 0.144 ;
     RECT  58.95 0.108 59.184 0.144 ;
     RECT  59.202 0.108 59.436 0.144 ;
     RECT  59.454 0.108 59.688 0.144 ;
     RECT  59.706 0.108 59.904 0.144 ;
     RECT  59.922 0.108 60.156 0.144 ;
     RECT  60.174 0.108 60.408 0.144 ;
     RECT  60.426 0.108 60.66 0.144 ;
     RECT  60.678 0.108 60.912 0.144 ;
     RECT  60.93 0.108 61.128 0.144 ;
     RECT  61.146 0.108 61.38 0.144 ;
     RECT  61.398 0.108 61.632 0.144 ;
     RECT  61.65 0.108 61.884 0.144 ;
     RECT  61.902 0.108 62.136 0.144 ;
     RECT  62.154 0.108 62.352 0.144 ;
     RECT  62.37 0.108 62.604 0.144 ;
     RECT  62.622 0.108 62.856 0.144 ;
     RECT  62.874 0.108 63.108 0.144 ;
     RECT  63.126 0.108 63.324 0.144 ;
     RECT  63.342 0.108 63.576 0.144 ;
     RECT  63.594 0.108 63.828 0.144 ;
     RECT  63.846 0.108 64.08 0.144 ;
     RECT  64.098 0.108 64.332 0.144 ;
     RECT  64.35 0.108 64.548 0.144 ;
     RECT  64.566 0.108 64.8 0.144 ;
     RECT  64.818 0.108 65.052 0.144 ;
     RECT  65.07 0.108 65.304 0.144 ;
     RECT  65.322 0.108 65.556 0.144 ;
     RECT  65.574 0.108 65.772 0.144 ;
     RECT  65.79 0.108 66.024 0.144 ;
     RECT  66.042 0.108 66.276 0.144 ;
     RECT  66.294 0.108 66.528 0.144 ;
     RECT  66.546 0.108 66.78 0.144 ;
     RECT  4.356 0.144 66.798 0.173 ;
     RECT  34.452 0.173 66.798 0.269 ;
     RECT  34.704 0.269 66.798 0.557 ;
     RECT  34.704 0.557 43.29 0.599 ;
     RECT  44.028 0.557 44.514 1.723 ;
     RECT  45.252 0.557 47.934 1.723 ;
     RECT  48.672 0.557 66.798 1.771 ;
     RECT  67.68 1.723 67.698 1.771 ;
     RECT  34.704 0.599 43.038 2.011 ;
     RECT  44.028 1.723 47.934 2.011 ;
     RECT  48.672 1.771 67.698 2.011 ;
     RECT  4.356 0.173 33.498 2.191 ;
     RECT  34.704 2.011 43.29 2.191 ;
     RECT  44.028 2.011 67.698 2.191 ;
     RECT  4.32 2.191 67.698 2.299 ;
     RECT  68.436 2.101 68.454 2.299 ;
     RECT  4.32 2.299 68.454 2.371 ;
     RECT  2.415 2.143 2.505 2.413 ;
     RECT  4.32 2.371 68.598 2.641 ;
     RECT  4.32 2.641 68.778 3.343 ;
     RECT  3.996 3.343 68.778 3.713 ;
     RECT  4.32 3.713 68.778 4.109 ;
     RECT  4.716 4.109 68.778 4.685 ;
     RECT  4.752 4.685 68.778 5.459 ;
     RECT  4.824 5.459 68.778 6.035 ;
     RECT  6.66 6.035 68.778 9.005 ;
     RECT  4.824 6.035 5.706 9.275 ;
     RECT  4.896 9.275 5.706 9.931 ;
     RECT  6.66 9.005 68.742 9.931 ;
     RECT  4.896 9.931 68.742 15.061 ;
     RECT  4.86 15.061 68.814 18.931 ;
     RECT  4.392 18.931 68.814 19.373 ;
     RECT  4.392 19.373 68.166 22.792 ;
     RECT  4.428 22.792 68.166 23.315 ;
     RECT  4.464 23.315 68.166 23.521 ;
     RECT  4.464 23.521 68.202 29.911 ;
     RECT  4.356 29.911 68.202 30.335 ;
     RECT  4.356 30.335 67.59 30.605 ;
     RECT  2.415 2.413 2.697 34.307 ;
     RECT  4.356 30.605 67.497 34.307 ;
     RECT  2.415 34.307 2.505 34.577 ;
     RECT  4.356 34.307 67.305 34.577 ;
     RECT  4.356 34.577 67.194 34.781 ;
     RECT  4.356 34.781 67.122 34.799 ;
     RECT  4.356 34.799 67.014 35.933 ;
     RECT  4.356 35.933 66.798 36.576 ;
     RECT  4.374 36.576 4.608 36.588 ;
     RECT  4.626 36.576 4.86 36.588 ;
     RECT  4.878 36.576 5.112 36.588 ;
     RECT  5.13 36.576 5.364 36.588 ;
     RECT  5.382 36.576 5.58 36.588 ;
     RECT  5.598 36.576 5.832 36.588 ;
     RECT  5.85 36.576 6.084 36.588 ;
     RECT  6.102 36.576 6.336 36.588 ;
     RECT  6.354 36.576 6.588 36.588 ;
     RECT  6.606 36.576 6.804 36.588 ;
     RECT  6.822 36.576 7.056 36.588 ;
     RECT  7.074 36.576 7.308 36.588 ;
     RECT  7.326 36.576 7.56 36.588 ;
     RECT  7.578 36.576 7.812 36.588 ;
     RECT  7.83 36.576 8.028 36.588 ;
     RECT  8.046 36.576 8.28 36.588 ;
     RECT  8.298 36.576 8.532 36.588 ;
     RECT  8.55 36.576 8.784 36.588 ;
     RECT  8.802 36.576 9.036 36.588 ;
     RECT  9.054 36.576 9.252 36.588 ;
     RECT  9.27 36.576 9.504 36.588 ;
     RECT  9.522 36.576 9.756 36.588 ;
     RECT  9.774 36.576 10.008 36.588 ;
     RECT  10.026 36.576 10.26 36.588 ;
     RECT  10.278 36.576 10.476 36.588 ;
     RECT  10.494 36.576 10.728 36.588 ;
     RECT  10.746 36.576 10.98 36.588 ;
     RECT  10.998 36.576 11.232 36.588 ;
     RECT  11.25 36.576 11.484 36.588 ;
     RECT  11.502 36.576 11.7 36.588 ;
     RECT  11.718 36.576 11.952 36.588 ;
     RECT  11.97 36.576 12.204 36.588 ;
     RECT  12.222 36.576 12.456 36.588 ;
     RECT  12.474 36.576 12.708 36.588 ;
     RECT  12.726 36.576 12.924 36.588 ;
     RECT  12.942 36.576 13.176 36.588 ;
     RECT  13.194 36.576 13.428 36.588 ;
     RECT  13.446 36.576 13.68 36.588 ;
     RECT  13.698 36.576 13.932 36.588 ;
     RECT  13.95 36.576 14.148 36.588 ;
     RECT  14.166 36.576 14.4 36.588 ;
     RECT  14.418 36.576 14.652 36.588 ;
     RECT  14.67 36.576 14.904 36.588 ;
     RECT  14.922 36.576 15.156 36.588 ;
     RECT  15.174 36.576 15.372 36.588 ;
     RECT  15.39 36.576 15.624 36.588 ;
     RECT  15.642 36.576 15.876 36.588 ;
     RECT  15.894 36.576 16.128 36.588 ;
     RECT  16.146 36.576 16.344 36.588 ;
     RECT  16.362 36.576 16.596 36.588 ;
     RECT  16.614 36.576 16.848 36.588 ;
     RECT  16.866 36.576 17.1 36.588 ;
     RECT  17.118 36.576 17.352 36.588 ;
     RECT  17.37 36.576 17.568 36.588 ;
     RECT  17.586 36.576 17.82 36.588 ;
     RECT  17.838 36.576 18.072 36.588 ;
     RECT  18.09 36.576 18.324 36.588 ;
     RECT  18.342 36.576 18.576 36.588 ;
     RECT  18.594 36.576 18.792 36.588 ;
     RECT  18.81 36.576 19.044 36.588 ;
     RECT  19.062 36.576 19.296 36.588 ;
     RECT  19.314 36.576 19.548 36.588 ;
     RECT  19.566 36.576 19.8 36.588 ;
     RECT  19.818 36.576 20.016 36.588 ;
     RECT  20.034 36.576 20.268 36.588 ;
     RECT  20.286 36.576 20.52 36.588 ;
     RECT  20.538 36.576 20.772 36.588 ;
     RECT  20.79 36.576 21.024 36.588 ;
     RECT  21.042 36.576 21.24 36.588 ;
     RECT  21.258 36.576 21.492 36.588 ;
     RECT  21.51 36.576 21.744 36.588 ;
     RECT  21.762 36.576 21.996 36.588 ;
     RECT  22.014 36.576 22.248 36.588 ;
     RECT  22.266 36.576 22.464 36.588 ;
     RECT  22.482 36.576 22.716 36.588 ;
     RECT  22.734 36.576 22.968 36.588 ;
     RECT  22.986 36.576 23.22 36.588 ;
     RECT  23.238 36.576 23.472 36.588 ;
     RECT  23.49 36.576 23.688 36.588 ;
     RECT  23.706 36.576 23.94 36.588 ;
     RECT  23.958 36.576 24.192 36.588 ;
     RECT  24.21 36.576 24.444 36.588 ;
     RECT  24.462 36.576 24.696 36.588 ;
     RECT  24.714 36.576 24.912 36.588 ;
     RECT  24.93 36.576 25.164 36.588 ;
     RECT  25.182 36.576 25.416 36.588 ;
     RECT  25.434 36.576 25.668 36.588 ;
     RECT  25.686 36.576 25.92 36.588 ;
     RECT  25.938 36.576 26.136 36.588 ;
     RECT  26.154 36.576 26.388 36.588 ;
     RECT  26.406 36.576 26.64 36.588 ;
     RECT  26.658 36.576 26.892 36.588 ;
     RECT  26.91 36.576 27.144 36.588 ;
     RECT  27.162 36.576 27.36 36.588 ;
     RECT  27.378 36.576 27.612 36.588 ;
     RECT  27.63 36.576 27.864 36.588 ;
     RECT  27.882 36.576 28.116 36.588 ;
     RECT  28.134 36.576 28.368 36.588 ;
     RECT  28.386 36.576 28.584 36.588 ;
     RECT  28.602 36.576 28.836 36.588 ;
     RECT  28.854 36.576 29.088 36.588 ;
     RECT  29.106 36.576 29.34 36.588 ;
     RECT  29.358 36.576 29.592 36.588 ;
     RECT  29.61 36.576 29.808 36.588 ;
     RECT  29.826 36.576 30.06 36.588 ;
     RECT  30.078 36.576 30.312 36.588 ;
     RECT  30.33 36.576 30.564 36.588 ;
     RECT  30.582 36.576 30.816 36.588 ;
     RECT  30.834 36.576 31.032 36.588 ;
     RECT  31.05 36.576 31.284 36.588 ;
     RECT  31.302 36.576 31.536 36.588 ;
     RECT  31.554 36.576 31.788 36.588 ;
     RECT  31.806 36.576 32.004 36.588 ;
     RECT  32.022 36.576 32.256 36.588 ;
     RECT  32.274 36.576 32.508 36.588 ;
     RECT  32.526 36.576 32.76 36.588 ;
     RECT  32.778 36.576 33.012 36.588 ;
     RECT  33.03 36.576 33.228 36.588 ;
     RECT  33.246 36.576 33.48 36.588 ;
     RECT  33.498 36.576 33.732 36.588 ;
     RECT  33.75 36.576 33.984 36.588 ;
     RECT  34.002 36.576 34.236 36.588 ;
     RECT  34.254 36.576 34.452 36.588 ;
     RECT  34.47 36.576 34.704 36.588 ;
     RECT  34.722 36.576 34.956 36.588 ;
     RECT  34.974 36.576 35.208 36.588 ;
     RECT  35.226 36.576 35.46 36.588 ;
     RECT  35.478 36.576 35.676 36.588 ;
     RECT  35.694 36.576 35.928 36.588 ;
     RECT  35.946 36.576 36.18 36.588 ;
     RECT  36.198 36.576 36.432 36.588 ;
     RECT  36.45 36.576 36.684 36.588 ;
     RECT  36.702 36.576 36.9 36.588 ;
     RECT  36.918 36.576 37.152 36.588 ;
     RECT  37.17 36.576 37.404 36.588 ;
     RECT  37.422 36.576 37.656 36.588 ;
     RECT  37.674 36.576 37.908 36.588 ;
     RECT  37.926 36.576 38.124 36.588 ;
     RECT  38.142 36.576 38.376 36.588 ;
     RECT  38.394 36.576 38.628 36.588 ;
     RECT  38.646 36.576 38.88 36.588 ;
     RECT  38.898 36.576 39.132 36.588 ;
     RECT  39.15 36.576 39.348 36.588 ;
     RECT  39.366 36.576 39.6 36.588 ;
     RECT  39.618 36.576 39.852 36.588 ;
     RECT  39.87 36.576 40.104 36.588 ;
     RECT  40.122 36.576 40.356 36.588 ;
     RECT  40.374 36.576 40.572 36.588 ;
     RECT  40.59 36.576 40.824 36.588 ;
     RECT  40.842 36.576 41.076 36.588 ;
     RECT  41.094 36.576 41.328 36.588 ;
     RECT  41.346 36.576 41.58 36.588 ;
     RECT  41.598 36.576 41.796 36.588 ;
     RECT  41.814 36.576 42.048 36.588 ;
     RECT  42.066 36.576 42.3 36.588 ;
     RECT  42.318 36.576 42.552 36.588 ;
     RECT  42.57 36.576 42.804 36.588 ;
     RECT  42.822 36.576 43.02 36.588 ;
     RECT  43.038 36.576 43.272 36.588 ;
     RECT  43.29 36.576 43.524 36.588 ;
     RECT  43.542 36.576 43.776 36.588 ;
     RECT  43.794 36.576 44.028 36.588 ;
     RECT  44.046 36.576 44.244 36.588 ;
     RECT  44.262 36.576 44.496 36.588 ;
     RECT  44.514 36.576 44.748 36.588 ;
     RECT  44.766 36.576 45 36.588 ;
     RECT  45.018 36.576 45.252 36.588 ;
     RECT  45.27 36.576 45.468 36.588 ;
     RECT  45.486 36.576 45.72 36.588 ;
     RECT  45.738 36.576 45.972 36.588 ;
     RECT  45.99 36.576 46.224 36.588 ;
     RECT  46.242 36.576 46.476 36.588 ;
     RECT  46.494 36.576 46.692 36.588 ;
     RECT  46.71 36.576 46.944 36.588 ;
     RECT  46.962 36.576 47.196 36.588 ;
     RECT  47.214 36.576 47.448 36.588 ;
     RECT  47.466 36.576 47.664 36.588 ;
     RECT  47.682 36.576 47.916 36.588 ;
     RECT  47.934 36.576 48.168 36.588 ;
     RECT  48.186 36.576 48.42 36.588 ;
     RECT  48.438 36.576 48.672 36.588 ;
     RECT  48.69 36.576 48.888 36.588 ;
     RECT  48.906 36.576 49.14 36.588 ;
     RECT  49.158 36.576 49.392 36.588 ;
     RECT  49.41 36.576 49.644 36.588 ;
     RECT  49.662 36.576 49.896 36.588 ;
     RECT  49.914 36.576 50.112 36.588 ;
     RECT  50.13 36.576 50.364 36.588 ;
     RECT  50.382 36.576 50.616 36.588 ;
     RECT  50.634 36.576 50.868 36.588 ;
     RECT  50.886 36.576 51.12 36.588 ;
     RECT  51.138 36.576 51.336 36.588 ;
     RECT  51.354 36.576 51.588 36.588 ;
     RECT  51.606 36.576 51.84 36.588 ;
     RECT  51.858 36.576 52.092 36.588 ;
     RECT  52.11 36.576 52.344 36.588 ;
     RECT  52.362 36.576 52.56 36.588 ;
     RECT  52.578 36.576 52.812 36.588 ;
     RECT  52.83 36.576 53.064 36.588 ;
     RECT  53.082 36.576 53.316 36.588 ;
     RECT  53.334 36.576 53.568 36.588 ;
     RECT  53.586 36.576 53.784 36.588 ;
     RECT  53.802 36.576 54.036 36.588 ;
     RECT  54.054 36.576 54.288 36.588 ;
     RECT  54.306 36.576 54.54 36.588 ;
     RECT  54.558 36.576 54.792 36.588 ;
     RECT  54.81 36.576 55.008 36.588 ;
     RECT  55.026 36.576 55.26 36.588 ;
     RECT  55.278 36.576 55.512 36.588 ;
     RECT  55.53 36.576 55.764 36.588 ;
     RECT  55.782 36.576 56.016 36.588 ;
     RECT  56.034 36.576 56.232 36.588 ;
     RECT  56.25 36.576 56.484 36.588 ;
     RECT  56.502 36.576 56.736 36.588 ;
     RECT  56.754 36.576 56.988 36.588 ;
     RECT  57.006 36.576 57.24 36.588 ;
     RECT  57.258 36.576 57.456 36.588 ;
     RECT  57.474 36.576 57.708 36.588 ;
     RECT  57.726 36.576 57.96 36.588 ;
     RECT  57.978 36.576 58.212 36.588 ;
     RECT  58.23 36.576 58.464 36.588 ;
     RECT  58.482 36.576 58.68 36.588 ;
     RECT  58.698 36.576 58.932 36.588 ;
     RECT  58.95 36.576 59.184 36.588 ;
     RECT  59.202 36.576 59.436 36.588 ;
     RECT  59.454 36.576 59.688 36.588 ;
     RECT  59.706 36.576 59.904 36.588 ;
     RECT  59.922 36.576 60.156 36.588 ;
     RECT  60.174 36.576 60.408 36.588 ;
     RECT  60.426 36.576 60.66 36.588 ;
     RECT  60.678 36.576 60.912 36.588 ;
     RECT  60.93 36.576 61.128 36.588 ;
     RECT  61.146 36.576 61.38 36.588 ;
     RECT  61.398 36.576 61.632 36.588 ;
     RECT  61.65 36.576 61.884 36.588 ;
     RECT  61.902 36.576 62.136 36.588 ;
     RECT  62.154 36.576 62.352 36.588 ;
     RECT  62.37 36.576 62.604 36.588 ;
     RECT  62.622 36.576 62.856 36.588 ;
     RECT  62.874 36.576 63.108 36.588 ;
     RECT  63.126 36.576 63.324 36.588 ;
     RECT  63.342 36.576 63.576 36.588 ;
     RECT  63.594 36.576 63.828 36.588 ;
     RECT  63.846 36.576 64.08 36.588 ;
     RECT  64.098 36.576 64.332 36.588 ;
     RECT  64.35 36.576 64.548 36.588 ;
     RECT  64.566 36.576 64.8 36.588 ;
     RECT  64.818 36.576 65.052 36.588 ;
     RECT  65.07 36.576 65.304 36.588 ;
     RECT  65.322 36.576 65.556 36.588 ;
     RECT  65.574 36.576 65.772 36.588 ;
     RECT  65.79 36.576 66.024 36.588 ;
     RECT  66.042 36.576 66.276 36.588 ;
     RECT  66.294 36.576 66.528 36.588 ;
     RECT  66.546 36.576 66.78 36.588 ;
     RECT  5.004 36.588 5.094 36.653 ;
     RECT  23.508 36.588 23.598 36.653 ;
     RECT  33.768 36.588 33.858 36.653 ;
    LAYER M4 ;
     RECT  0.229 6.048 2.408 6.072 ;
     RECT  2.408 2.148 2.512 34.572 ;
     RECT  2.512 2.418 2.704 34.302 ;
     RECT  4.481 34.752 4.565 34.776 ;
     RECT  4.741 30.672 4.981 30.696 ;
     RECT  4.481 1.728 5.108 1.752 ;
     RECT  5.101 4.752 5.108 4.776 ;
     RECT  2.704 6.048 5.108 6.072 ;
     RECT  4.981 30.48 5.108 30.696 ;
     RECT  5.108 1.728 5.404 34.728 ;
     RECT  5.404 1.728 5.669 1.752 ;
     RECT  5.404 34.224 5.681 34.728 ;
     RECT  5.669 1.152 5.753 1.752 ;
     RECT  5.753 1.728 6.149 1.752 ;
     RECT  5.681 34.224 6.257 34.296 ;
     RECT  5.404 4.224 6.275 6.072 ;
     RECT  5.404 30.816 6.661 30.84 ;
     RECT  6.661 30.816 6.803 31.32 ;
     RECT  5.404 2.88 6.949 2.904 ;
     RECT  6.257 34.224 6.949 34.248 ;
     RECT  6.803 30.816 7.189 31.224 ;
     RECT  6.275 5.664 7.369 6.072 ;
     RECT  6.949 33.648 7.429 34.248 ;
     RECT  7.429 33.072 7.621 34.248 ;
     RECT  7.181 1.728 7.808 1.752 ;
     RECT  6.949 2.88 7.808 2.952 ;
     RECT  6.275 4.224 7.808 4.248 ;
     RECT  7.369 5.664 7.808 6.408 ;
     RECT  7.189 30.672 7.808 31.224 ;
     RECT  7.621 33.072 7.808 34.728 ;
     RECT  7.808 1.728 7.955 34.728 ;
     RECT  7.955 1.728 8.104 34.68 ;
     RECT  8.104 34.656 8.195 34.68 ;
     RECT  8.104 4.176 8.435 6.84 ;
     RECT  8.435 4.224 8.476 6.84 ;
     RECT  8.104 30.816 8.921 31.224 ;
     RECT  8.104 33.648 8.957 33.672 ;
     RECT  8.476 4.224 8.993 4.296 ;
     RECT  8.476 5.28 9.029 6.84 ;
     RECT  8.104 2.88 9.065 2.904 ;
     RECT  8.921 30.816 9.109 30.84 ;
     RECT  8.389 35.904 9.173 35.928 ;
     RECT  9.109 30.48 9.245 30.84 ;
     RECT  8.104 1.728 9.385 1.752 ;
     RECT  8.993 4.272 9.529 4.296 ;
     RECT  9.397 34.224 9.596 34.248 ;
     RECT  9.529 4.272 10.141 5.064 ;
     RECT  9.029 6.048 10.141 6.84 ;
     RECT  9.385 1.728 10.181 2.328 ;
     RECT  10.141 4.272 10.357 6.84 ;
     RECT  10.249 19.632 10.357 19.656 ;
     RECT  10.357 19.536 10.429 19.656 ;
     RECT  9.596 34.224 10.429 34.344 ;
     RECT  10.181 1.776 10.508 2.328 ;
     RECT  10.357 3.408 10.508 6.84 ;
     RECT  10.321 15.552 10.508 15.576 ;
     RECT  10.429 18.96 10.508 19.656 ;
     RECT  9.245 30.48 10.508 30.504 ;
     RECT  10.033 33.072 10.508 33.096 ;
     RECT  10.429 34.224 10.508 34.728 ;
     RECT  10.508 1.776 10.643 34.728 ;
     RECT  10.643 1.776 10.804 34.68 ;
     RECT  10.804 19.632 10.829 19.656 ;
     RECT  10.837 0.192 10.979 0.216 ;
     RECT  10.357 35.904 11.009 35.928 ;
     RECT  10.804 2.88 11.117 3.144 ;
     RECT  10.804 34.224 11.117 34.68 ;
     RECT  11.117 2.928 11.363 3.144 ;
     RECT  11.363 2.928 11.405 2.952 ;
     RECT  10.804 4.272 11.477 7.464 ;
     RECT  11.477 4.272 11.747 7.032 ;
     RECT  11.557 1.728 11.825 1.752 ;
     RECT  11.825 1.728 11.909 1.848 ;
     RECT  10.804 30.48 12.085 30.744 ;
     RECT  12.085 30.48 12.125 30.84 ;
     RECT  12.841 3.024 13.021 3.048 ;
     RECT  11.747 4.272 13.021 6.84 ;
     RECT  13.021 3.024 13.093 6.84 ;
     RECT  11.909 1.728 13.208 1.8 ;
     RECT  13.093 2.784 13.208 6.84 ;
     RECT  12.125 30.576 13.208 30.84 ;
     RECT  11.117 34.224 13.208 34.248 ;
     RECT  13.208 1.728 13.285 34.572 ;
     RECT  13.285 1.728 13.504 34.728 ;
     RECT  13.504 30.192 13.565 30.696 ;
     RECT  13.504 34.224 13.673 34.728 ;
     RECT  13.565 30.192 14.393 30.552 ;
     RECT  13.504 2.88 14.723 6.888 ;
     RECT  13.673 34.224 14.732 34.248 ;
     RECT  14.732 34.224 14.819 34.344 ;
     RECT  14.393 30.528 14.933 30.552 ;
     RECT  13.504 1.728 15.725 1.752 ;
     RECT  14.819 34.224 15.733 34.248 ;
     RECT  14.723 2.88 15.829 6.6 ;
     RECT  15.829 2.88 15.908 6.84 ;
     RECT  15.253 30.672 15.908 30.696 ;
     RECT  15.733 33.648 15.908 34.248 ;
     RECT  15.908 2.016 15.973 34.572 ;
     RECT  15.973 2.016 16.204 34.728 ;
     RECT  16.204 2.016 16.301 2.04 ;
     RECT  15.973 0.192 16.355 0.216 ;
     RECT  16.204 3.264 16.517 6.84 ;
     RECT  16.204 34.656 16.517 34.728 ;
     RECT  16.204 33.648 17.057 33.672 ;
     RECT  16.693 1.728 17.593 1.8 ;
     RECT  17.593 1.728 17.605 2.664 ;
     RECT  16.517 3.84 17.605 6.84 ;
     RECT  17.221 34.752 17.633 34.776 ;
     RECT  17.804 0.144 17.891 0.168 ;
     RECT  16.204 30.48 17.941 30.84 ;
     RECT  17.941 30.48 18.181 30.984 ;
     RECT  17.605 1.728 18.608 6.84 ;
     RECT  18.181 30.48 18.608 31.224 ;
     RECT  18.38 33.648 18.608 33.672 ;
     RECT  18.469 34.8 18.608 34.824 ;
     RECT  18.608 1.728 18.901 34.824 ;
     RECT  18.901 1.728 18.904 34.872 ;
     RECT  18.904 30.48 18.965 31.224 ;
     RECT  18.901 0.192 19.043 0.216 ;
     RECT  18.904 34.704 19.043 34.872 ;
     RECT  18.965 30.48 19.145 30.6 ;
     RECT  18.904 1.728 19.505 1.752 ;
     RECT  18.904 2.784 19.619 6.696 ;
     RECT  19.619 2.784 19.657 4.824 ;
     RECT  19.043 34.704 19.868 34.776 ;
     RECT  19.868 34.224 19.955 34.776 ;
     RECT  19.145 30.48 20.389 30.504 ;
     RECT  19.619 6.048 20.761 6.696 ;
     RECT  19.657 2.88 20.869 4.824 ;
     RECT  20.761 5.952 20.869 6.696 ;
     RECT  20.389 30.48 20.869 31.32 ;
     RECT  20.869 2.88 20.917 6.696 ;
     RECT  19.955 34.752 21.088 34.776 ;
     RECT  21.088 34.752 21.109 34.824 ;
     RECT  21.085 15.312 21.265 15.336 ;
     RECT  21.109 1.728 21.308 1.752 ;
     RECT  20.917 2.736 21.308 6.696 ;
     RECT  21.265 14.976 21.308 15.336 ;
     RECT  20.869 30.432 21.308 31.32 ;
     RECT  21.109 34.752 21.308 35.064 ;
     RECT  21.308 1.728 21.539 35.064 ;
     RECT  21.539 1.728 21.604 34.824 ;
     RECT  21.604 33.648 21.635 34.824 ;
     RECT  21.635 33.648 21.923 34.776 ;
     RECT  21.604 30.576 21.953 30.696 ;
     RECT  21.604 1.728 22.205 7.464 ;
     RECT  21.953 30.672 22.205 30.696 ;
     RECT  22.205 1.728 22.636 6.888 ;
     RECT  22.636 2.88 22.787 6.888 ;
     RECT  22.636 1.728 23.123 1.752 ;
     RECT  23.077 30.816 23.317 30.84 ;
     RECT  23.42 0.144 23.507 0.168 ;
     RECT  23.317 30.816 23.797 31.224 ;
     RECT  22.787 2.88 23.86 6.84 ;
     RECT  23.86 2.832 24.008 6.84 ;
     RECT  23.797 30.672 24.008 31.224 ;
     RECT  21.923 34.176 24.008 34.776 ;
     RECT  24.008 2.148 24.037 34.776 ;
     RECT  24.037 0.192 24.277 0.216 ;
     RECT  24.037 2.148 24.277 34.824 ;
     RECT  24.277 2.148 24.304 34.872 ;
     RECT  24.277 0.192 24.419 0.312 ;
     RECT  24.304 34.224 24.419 34.872 ;
     RECT  24.419 0.288 24.467 0.312 ;
     RECT  24.419 34.224 24.515 34.824 ;
     RECT  24.304 2.148 24.533 7.464 ;
     RECT  24.533 1.728 24.563 7.464 ;
     RECT  24.563 1.728 24.617 6.84 ;
     RECT  24.304 30.672 25.013 30.744 ;
     RECT  24.617 1.728 25.091 6.072 ;
     RECT  24.515 34.224 25.571 34.776 ;
     RECT  25.091 3.792 25.585 6.072 ;
     RECT  25.285 30.816 26.005 30.84 ;
     RECT  25.585 3.792 26.389 6.264 ;
     RECT  26.389 3.6 26.437 6.264 ;
     RECT  25.091 1.728 26.533 2.28 ;
     RECT  26.437 3.312 26.533 6.264 ;
     RECT  26.533 0.288 26.581 0.312 ;
     RECT  26.005 30.144 26.581 30.84 ;
     RECT  25.571 34.704 26.581 34.776 ;
     RECT  26.581 0.288 26.669 0.552 ;
     RECT  26.533 1.728 26.708 6.264 ;
     RECT  26.581 30.096 26.708 30.84 ;
     RECT  26.581 34.704 26.708 34.824 ;
     RECT  26.669 0.288 26.771 0.312 ;
     RECT  26.708 1.728 27.004 34.824 ;
     RECT  27.004 34.752 27.155 34.824 ;
     RECT  27.004 29.616 27.605 30.84 ;
     RECT  27.605 30.72 27.785 30.84 ;
     RECT  27.004 1.728 27.821 6.408 ;
     RECT  27.004 9.696 27.827 9.72 ;
     RECT  27.821 2.256 28.117 6.408 ;
     RECT  28.117 2.688 28.217 6.408 ;
     RECT  28.217 2.832 28.364 6.408 ;
     RECT  27.155 34.752 28.393 34.776 ;
     RECT  28.393 34.224 28.693 34.776 ;
     RECT  27.889 0.192 28.739 0.216 ;
     RECT  27.785 30.816 28.933 30.84 ;
     RECT  28.364 2.832 29.221 6.792 ;
     RECT  28.693 33.6 29.269 34.776 ;
     RECT  29.221 2.016 29.408 6.792 ;
     RECT  27.605 29.616 29.408 29.64 ;
     RECT  28.933 30.816 29.408 31.224 ;
     RECT  29.269 33.6 29.408 34.824 ;
     RECT  29.408 2.016 29.701 34.824 ;
     RECT  29.701 1.728 29.704 34.824 ;
     RECT  29.704 30.72 29.765 31.224 ;
     RECT  29.704 34.176 29.843 34.824 ;
     RECT  29.843 34.176 30.197 34.776 ;
     RECT  30.181 35.904 30.665 35.928 ;
     RECT  29.765 30.72 30.737 30.888 ;
     RECT  29.704 1.728 30.773 6.312 ;
     RECT  30.737 30.72 30.809 30.792 ;
     RECT  30.773 2.256 31.1 6.312 ;
     RECT  31.244 0.144 31.331 0.168 ;
     RECT  31.1 2.256 31.909 6.552 ;
     RECT  30.197 34.656 31.909 34.776 ;
     RECT  31.813 0.192 31.955 0.216 ;
     RECT  30.809 30.72 31.957 30.744 ;
     RECT  31.909 34.176 31.957 34.776 ;
     RECT  31.909 2.256 32.108 6.888 ;
     RECT  31.957 30.672 32.108 30.744 ;
     RECT  31.957 34.176 32.108 34.92 ;
     RECT  32.108 2.148 32.149 34.92 ;
     RECT  31.957 0.528 32.285 0.552 ;
     RECT  32.149 1.728 32.404 34.92 ;
     RECT  32.404 34.656 32.435 34.92 ;
     RECT  32.435 34.656 32.483 34.824 ;
     RECT  32.404 2.784 32.573 6.888 ;
     RECT  32.404 1.728 32.933 1.752 ;
     RECT  32.483 34.704 33.077 34.776 ;
     RECT  33.217 0.288 33.443 0.312 ;
     RECT  33.077 34.704 33.617 34.728 ;
     RECT  32.573 2.88 33.721 6.552 ;
     RECT  32.404 30.48 34.069 30.84 ;
     RECT  33.721 2.304 34.117 6.552 ;
     RECT  33.692 0.144 34.412 0.168 ;
     RECT  34.117 2.208 34.441 6.552 ;
     RECT  34.412 0.144 34.451 0.264 ;
     RECT  34.441 2.208 34.513 6.6 ;
     RECT  34.513 2.208 34.808 6.888 ;
     RECT  33.973 9.696 34.808 9.72 ;
     RECT  34.069 30.48 34.808 30.888 ;
     RECT  34.309 34.752 34.808 34.776 ;
     RECT  34.808 2.148 34.837 34.776 ;
     RECT  34.837 2.148 34.912 34.872 ;
     RECT  34.451 0.192 35.077 0.264 ;
     RECT  34.912 2.208 35.077 34.872 ;
     RECT  35.077 2.208 35.104 34.968 ;
     RECT  35.104 30.672 35.129 31.32 ;
     RECT  35.104 15.456 35.165 15.48 ;
     RECT  35.077 0.192 35.219 0.312 ;
     RECT  35.104 34.176 35.267 34.968 ;
     RECT  35.219 0.288 35.315 0.312 ;
     RECT  35.104 2.208 35.507 6.84 ;
     RECT  35.104 10.272 35.699 10.296 ;
     RECT  35.507 2.88 35.741 6.84 ;
     RECT  35.741 4.128 35.921 6.84 ;
     RECT  35.921 4.128 36.065 6.6 ;
     RECT  35.129 31.296 36.277 31.32 ;
     RECT  36.065 4.56 36.353 6.6 ;
     RECT  36.277 31.248 36.533 31.32 ;
     RECT  35.741 2.88 36.565 2.904 ;
     RECT  36.037 1.728 36.989 1.752 ;
     RECT  36.565 2.832 36.989 2.904 ;
     RECT  36.353 4.56 37.141 5.208 ;
     RECT  36.989 1.728 37.253 2.904 ;
     RECT  37.253 1.776 37.333 2.904 ;
     RECT  37.141 3.936 37.333 5.208 ;
     RECT  37.333 1.776 37.357 5.208 ;
     RECT  36.353 6.576 37.357 6.6 ;
     RECT  37.357 1.776 37.361 6.6 ;
     RECT  35.267 34.176 37.381 34.776 ;
     RECT  37.361 2.016 37.508 6.6 ;
     RECT  37.381 30.144 37.508 30.168 ;
     RECT  36.533 31.248 37.508 31.272 ;
     RECT  37.381 34.176 37.508 34.824 ;
     RECT  37.508 2.016 37.804 34.824 ;
     RECT  37.381 0.192 37.868 0.216 ;
     RECT  37.868 0.144 37.955 0.216 ;
     RECT  37.804 33.6 37.955 34.824 ;
     RECT  37.955 33.6 38.189 34.776 ;
     RECT  38.149 0.528 38.291 0.552 ;
     RECT  37.804 30.144 38.297 30.84 ;
     RECT  38.297 30.192 38.513 30.84 ;
     RECT  37.804 14.832 38.549 14.856 ;
     RECT  38.189 33.6 38.693 34.68 ;
     RECT  37.804 2.016 38.725 6.648 ;
     RECT  38.725 1.728 38.809 6.648 ;
     RECT  38.513 30.192 38.837 30.744 ;
     RECT  38.809 1.776 39.011 6.648 ;
     RECT  39.011 2.208 39.013 6.648 ;
     RECT  38.837 30.72 39.161 30.744 ;
     RECT  38.693 34.176 39.205 34.68 ;
     RECT  39.013 2.208 39.373 6.936 ;
     RECT  39.205 34.176 40.069 34.776 ;
     RECT  39.373 2.208 40.208 7.464 ;
     RECT  39.973 30.432 40.208 30.696 ;
     RECT  40.069 34.176 40.208 34.824 ;
     RECT  40.069 0.192 40.259 0.216 ;
     RECT  40.208 2.148 40.453 34.824 ;
     RECT  40.453 2.016 40.504 34.872 ;
     RECT  40.504 2.016 40.565 2.904 ;
     RECT  40.504 34.176 40.643 34.872 ;
     RECT  40.504 30.672 40.853 30.84 ;
     RECT  40.643 34.176 41.033 34.776 ;
     RECT  40.853 30.816 41.429 30.84 ;
     RECT  40.565 2.784 41.509 2.904 ;
     RECT  40.504 3.936 41.509 6.648 ;
     RECT  40.661 1.728 41.557 1.752 ;
     RECT  41.509 2.784 41.557 6.648 ;
     RECT  41.033 34.656 41.573 34.776 ;
     RECT  41.557 1.728 42.373 6.648 ;
     RECT  42.373 1.728 42.653 6.888 ;
     RECT  41.941 30.48 42.661 30.696 ;
     RECT  42.653 1.776 42.725 6.888 ;
     RECT  42.613 0.528 42.757 0.552 ;
     RECT  41.573 34.752 42.757 34.776 ;
     RECT  42.725 2.016 42.908 6.888 ;
     RECT  42.661 30.48 42.908 30.792 ;
     RECT  42.757 34.176 42.908 34.824 ;
     RECT  42.908 2.016 43.141 34.824 ;
     RECT  43.141 2.016 43.204 34.872 ;
     RECT  43.204 34.224 43.331 34.872 ;
     RECT  43.204 15.84 43.337 15.864 ;
     RECT  43.331 34.224 43.337 34.776 ;
     RECT  43.204 5.712 43.523 7.176 ;
     RECT  42.757 0.192 43.553 0.552 ;
     RECT  43.337 34.224 43.841 34.728 ;
     RECT  43.204 2.016 43.861 4.68 ;
     RECT  43.841 34.224 43.907 34.248 ;
     RECT  43.204 30.72 44.341 30.744 ;
     RECT  43.861 1.728 44.453 4.68 ;
     RECT  44.341 30.48 44.629 30.744 ;
     RECT  44.101 35.904 44.669 35.928 ;
     RECT  44.629 30.48 44.869 30.84 ;
     RECT  43.724 0.144 44.945 0.168 ;
     RECT  44.945 0.144 45.029 0.552 ;
     RECT  44.453 1.728 45.245 1.752 ;
     RECT  44.453 2.784 45.445 4.68 ;
     RECT  43.523 5.712 45.445 6.84 ;
     RECT  45.029 0.144 45.539 0.312 ;
     RECT  45.445 2.784 45.608 6.84 ;
     RECT  44.869 30.144 45.608 30.84 ;
     RECT  45.589 34.8 45.608 34.824 ;
     RECT  45.608 2.148 45.904 34.824 ;
     RECT  45.539 0.192 46.019 0.312 ;
     RECT  45.904 34.128 46.019 34.824 ;
     RECT  45.904 30.576 46.037 30.84 ;
     RECT  46.019 0.288 46.067 0.312 ;
     RECT  45.829 35.904 46.069 35.928 ;
     RECT  45.904 10.656 46.115 11.256 ;
     RECT  46.115 10.656 46.117 10.68 ;
     RECT  45.904 2.736 46.145 7.464 ;
     RECT  46.145 3.888 46.163 7.464 ;
     RECT  46.145 2.736 46.181 2.904 ;
     RECT  46.181 2.736 46.261 2.808 ;
     RECT  46.037 30.816 46.289 30.84 ;
     RECT  46.261 2.736 46.397 2.76 ;
     RECT  46.069 35.904 46.433 36.024 ;
     RECT  46.019 34.128 46.79 34.2 ;
     RECT  46.433 35.904 47.117 35.928 ;
     RECT  46.79 34.176 47.261 34.2 ;
     RECT  46.285 1.728 47.269 1.752 ;
     RECT  46.163 3.888 47.324 6.84 ;
     RECT  47.269 1.728 47.509 2.712 ;
     RECT  47.324 3.744 47.509 6.84 ;
     RECT  47.077 29.952 47.797 30.312 ;
     RECT  47.612 0.144 47.989 0.168 ;
     RECT  47.317 34.752 48.037 34.776 ;
     RECT  47.989 0.144 48.227 0.552 ;
     RECT  48.037 34.752 48.233 34.824 ;
     RECT  47.509 1.728 48.308 6.84 ;
     RECT  47.797 29.952 48.308 30.696 ;
     RECT  48.233 34.752 48.308 34.776 ;
     RECT  48.227 0.24 48.323 0.552 ;
     RECT  48.323 0.528 48.449 0.552 ;
     RECT  48.277 35.904 48.517 35.928 ;
     RECT  48.308 1.728 48.604 34.776 ;
     RECT  48.604 1.728 48.947 6.84 ;
     RECT  48.947 1.728 48.997 2.664 ;
     RECT  48.997 1.152 49.139 2.664 ;
     RECT  49.139 1.728 49.313 2.664 ;
     RECT  48.604 34.752 49.601 34.776 ;
     RECT  48.604 30.816 49.925 30.84 ;
     RECT  48.947 3.888 49.964 6.84 ;
     RECT  49.765 34.176 49.997 34.248 ;
     RECT  48.517 35.904 50.501 35.976 ;
     RECT  49.964 3.024 50.713 6.84 ;
     RECT  49.997 34.224 50.725 34.248 ;
     RECT  49.313 1.728 50.821 1.8 ;
     RECT  50.713 2.88 50.821 6.84 ;
     RECT  50.725 34.224 50.869 34.776 ;
     RECT  50.821 1.728 51.008 6.84 ;
     RECT  50.485 30.768 51.008 30.792 ;
     RECT  50.869 34.224 51.008 34.824 ;
     RECT  50.869 0.192 51.011 0.216 ;
     RECT  51.008 1.728 51.011 34.824 ;
     RECT  51.011 1.728 51.304 34.776 ;
     RECT  51.304 3.888 51.617 6.84 ;
     RECT  51.617 5.232 52.157 6.84 ;
     RECT  51.304 34.752 52.337 34.776 ;
     RECT  51.304 1.728 52.373 1.8 ;
     RECT  50.501 35.904 52.453 35.928 ;
     RECT  51.304 29.952 52.517 29.976 ;
     RECT  52.453 35.904 52.933 35.976 ;
     RECT  52.933 35.904 53.129 36.024 ;
     RECT  51.617 3.888 53.132 4.248 ;
     RECT  52.157 5.472 53.132 6.84 ;
     RECT  52.933 2.88 53.161 2.904 ;
     RECT  53.132 3.888 53.161 6.84 ;
     RECT  53.129 35.904 53.345 35.976 ;
     RECT  52.693 30.192 53.413 30.216 ;
     RECT  53.173 34.224 53.653 34.248 ;
     RECT  52.373 1.728 53.708 1.752 ;
     RECT  53.161 2.88 53.708 6.84 ;
     RECT  53.413 30.192 53.708 30.696 ;
     RECT  53.653 34.224 53.708 34.728 ;
     RECT  53.708 1.728 54.004 34.728 ;
     RECT  54.004 23.856 54.029 23.88 ;
     RECT  53.893 0.288 54.131 0.312 ;
     RECT  54.004 2.832 54.131 6.552 ;
     RECT  54.004 33.648 54.131 34.728 ;
     RECT  54.004 1.728 54.133 1.752 ;
     RECT  54.004 30.672 54.173 30.84 ;
     RECT  54.133 1.152 54.217 1.752 ;
     RECT  54.131 2.832 54.317 6.312 ;
     RECT  53.345 35.904 54.373 35.928 ;
     RECT  54.173 30.768 54.389 30.84 ;
     RECT  54.131 33.648 54.497 34.248 ;
     RECT  54.389 30.768 54.768 30.792 ;
     RECT  54.373 35.904 54.857 35.976 ;
     RECT  54.217 1.728 55.033 1.752 ;
     RECT  54.317 3.888 55.093 6.312 ;
     RECT  55.093 3.888 55.247 6.552 ;
     RECT  54.317 2.832 55.537 2.904 ;
     RECT  54.857 35.904 55.577 35.928 ;
     RECT  54.497 33.648 55.861 33.672 ;
     RECT  55.537 2.784 56.213 2.904 ;
     RECT  55.247 3.888 56.213 7.272 ;
     RECT  55.861 33.648 56.252 34.248 ;
     RECT  55.033 1.728 56.293 1.8 ;
     RECT  56.213 2.784 56.293 7.272 ;
     RECT  55.621 30.48 56.293 30.504 ;
     RECT  56.252 33.648 56.293 34.632 ;
     RECT  56.245 0.192 56.365 0.216 ;
     RECT  56.293 33.648 56.387 34.728 ;
     RECT  56.293 1.728 56.408 7.272 ;
     RECT  56.293 29.616 56.408 30.504 ;
     RECT  56.387 33.648 56.408 34.68 ;
     RECT  56.365 0.144 56.513 0.216 ;
     RECT  56.408 1.728 56.704 34.68 ;
     RECT  56.581 0.288 56.819 0.312 ;
     RECT  56.704 34.224 56.819 34.68 ;
     RECT  56.704 29.616 57.089 30.744 ;
     RECT  57.089 29.616 57.341 30.504 ;
     RECT  56.704 1.728 57.443 6.888 ;
     RECT  57.443 1.728 57.587 6.84 ;
     RECT  57.341 30.192 57.737 30.504 ;
     RECT  56.704 10.8 57.809 10.824 ;
     RECT  57.587 1.728 57.845 2.28 ;
     RECT  57.737 30.48 58.069 30.504 ;
     RECT  57.349 35.904 58.097 35.928 ;
     RECT  57.845 1.728 58.141 1.848 ;
     RECT  57.587 3.36 58.549 6.84 ;
     RECT  58.069 30.48 58.789 30.84 ;
     RECT  56.819 34.224 58.949 34.248 ;
     RECT  58.949 34.224 58.988 34.632 ;
     RECT  58.988 34.224 59.075 34.728 ;
     RECT  58.141 1.728 59.108 1.752 ;
     RECT  58.549 2.88 59.108 6.84 ;
     RECT  58.789 29.616 59.108 30.84 ;
     RECT  59.075 34.224 59.108 34.68 ;
     RECT  59.108 1.728 59.404 34.68 ;
     RECT  59.404 1.728 59.465 2.04 ;
     RECT  59.404 29.616 59.465 30.744 ;
     RECT  59.465 30.048 59.537 30.744 ;
     RECT  59.404 34.656 59.555 34.68 ;
     RECT  59.404 3.024 59.609 6.84 ;
     RECT  59.537 30.192 60.113 30.744 ;
     RECT  59.557 35.904 60.277 35.928 ;
     RECT  60.277 35.904 60.289 35.976 ;
     RECT  59.404 33.648 60.329 33.672 ;
     RECT  60.289 35.856 60.401 35.976 ;
     RECT  59.609 3.408 60.409 6.84 ;
     RECT  60.401 35.904 60.473 35.976 ;
     RECT  60.517 34.224 60.604 34.248 ;
     RECT  60.113 30.48 60.757 30.744 ;
     RECT  60.473 35.952 60.761 35.976 ;
     RECT  59.465 1.728 61.237 1.752 ;
     RECT  60.757 30.48 61.237 30.84 ;
     RECT  60.409 3.888 61.513 6.84 ;
     RECT  61.513 3.312 61.669 6.84 ;
     RECT  61.237 1.728 61.808 1.8 ;
     RECT  61.669 3.12 61.808 6.84 ;
     RECT  61.657 22.752 61.808 22.776 ;
     RECT  61.237 30.192 61.808 30.84 ;
     RECT  61.808 1.728 61.912 34.572 ;
     RECT  61.717 35.904 62.005 35.928 ;
     RECT  61.573 0.192 62.051 0.216 ;
     RECT  61.912 1.728 62.104 34.302 ;
     RECT  62.104 30.192 62.345 30.6 ;
     RECT  62.104 1.728 62.701 1.752 ;
     RECT  62.701 1.104 62.785 1.752 ;
     RECT  62.345 30.192 62.813 30.312 ;
     RECT  62.005 35.904 62.965 35.976 ;
     RECT  62.104 4.272 63.065 6.84 ;
     RECT  63.065 4.272 63.107 6.504 ;
     RECT  62.104 2.784 63.205 3.096 ;
     RECT  63.107 4.272 63.205 6.264 ;
     RECT  63.205 2.784 63.251 6.264 ;
     RECT  63.251 2.832 63.353 6.264 ;
     RECT  62.785 1.68 63.461 1.752 ;
     RECT  62.965 35.904 63.497 36.024 ;
     RECT  63.353 2.832 64.213 3.768 ;
     RECT  63.461 1.728 64.357 1.752 ;
     RECT  64.213 2.736 64.357 3.768 ;
     RECT  63.925 34.752 64.405 34.776 ;
     RECT  64.357 1.728 64.508 3.768 ;
     RECT  63.353 4.896 64.508 6.264 ;
     RECT  62.813 30.192 64.508 30.216 ;
     RECT  64.405 34.752 64.508 34.872 ;
     RECT  64.508 1.728 64.804 34.872 ;
     RECT  64.693 0.288 64.931 0.312 ;
     RECT  64.804 34.176 64.931 34.872 ;
     RECT  63.497 35.904 64.933 35.928 ;
     RECT  64.931 34.176 64.937 34.776 ;
     RECT  64.804 3.024 65.017 3.864 ;
     RECT  64.933 35.904 65.261 36.024 ;
     RECT  65.261 36 65.297 36.024 ;
     RECT  64.804 30.48 66.017 30.84 ;
     RECT  65.833 2.832 66.121 2.856 ;
     RECT  65.017 3.84 66.121 3.864 ;
     RECT  66.121 2.832 66.161 3.864 ;
     RECT  66.161 2.832 66.179 3.432 ;
     RECT  64.804 5.712 66.301 6.264 ;
     RECT  66.017 30.48 66.373 30.744 ;
     RECT  64.804 1.728 66.613 1.752 ;
     RECT  64.937 34.176 66.853 34.2 ;
     RECT  66.613 35.904 67.025 35.928 ;
     RECT  66.853 34.176 67.205 34.776 ;
     RECT  66.613 1.728 67.208 1.8 ;
     RECT  66.179 3.408 67.208 3.432 ;
     RECT  66.301 5.184 67.208 6.264 ;
     RECT  66.373 30.192 67.208 30.744 ;
     RECT  67.205 34.176 67.208 34.572 ;
     RECT  67.208 1.728 67.312 34.572 ;
     RECT  67.312 1.728 67.504 34.302 ;
     RECT  67.504 1.728 67.709 1.752 ;
    LAYER M5 ;
     RECT  17.856 0.133 17.88 0.144 ;
     RECT  23.472 0.133 23.496 0.144 ;
     RECT  31.296 0.133 31.32 0.144 ;
     RECT  33.744 0.133 33.84 0.144 ;
     RECT  33.864 0.133 34.08 0.144 ;
     RECT  34.104 0.133 34.32 0.144 ;
     RECT  34.344 0.133 34.44 0.144 ;
     RECT  37.92 0.133 37.944 0.144 ;
     RECT  43.776 0.133 43.8 0.144 ;
     RECT  44.784 0.133 44.88 0.144 ;
     RECT  44.904 0.133 45.12 0.144 ;
     RECT  45.144 0.133 45.36 0.144 ;
     RECT  45.384 0.133 45.528 0.144 ;
     RECT  47.664 0.133 47.808 0.144 ;
     RECT  47.832 0.133 48.048 0.144 ;
     RECT  48.072 0.133 48.216 0.144 ;
     RECT  4.536 0.144 4.752 0.192 ;
     RECT  4.776 0.144 4.992 0.192 ;
     RECT  5.016 0.144 5.232 0.192 ;
     RECT  5.256 0.144 5.472 0.192 ;
     RECT  5.496 0.144 5.712 0.192 ;
     RECT  5.736 0.144 5.952 0.192 ;
     RECT  5.976 0.144 6.192 0.192 ;
     RECT  6.216 0.144 6.432 0.192 ;
     RECT  6.456 0.144 6.672 0.192 ;
     RECT  6.696 0.144 6.96 0.192 ;
     RECT  6.984 0.144 7.2 0.192 ;
     RECT  7.224 0.144 7.44 0.192 ;
     RECT  7.464 0.144 7.68 0.192 ;
     RECT  7.704 0.144 7.92 0.192 ;
     RECT  7.944 0.144 8.16 0.192 ;
     RECT  8.184 0.144 8.4 0.192 ;
     RECT  8.424 0.144 8.64 0.192 ;
     RECT  8.664 0.144 8.88 0.192 ;
     RECT  8.904 0.144 9.12 0.192 ;
     RECT  9.144 0.144 9.408 0.192 ;
     RECT  9.432 0.144 9.648 0.192 ;
     RECT  9.672 0.144 9.888 0.192 ;
     RECT  9.912 0.144 10.128 0.192 ;
     RECT  10.152 0.144 10.368 0.192 ;
     RECT  10.392 0.144 10.608 0.192 ;
     RECT  10.632 0.144 10.848 0.192 ;
     RECT  10.872 0.144 11.088 0.192 ;
     RECT  11.112 0.144 11.328 0.192 ;
     RECT  11.352 0.144 11.568 0.192 ;
     RECT  11.592 0.144 11.856 0.192 ;
     RECT  11.88 0.144 12.096 0.192 ;
     RECT  12.12 0.144 12.336 0.192 ;
     RECT  12.36 0.144 12.576 0.192 ;
     RECT  12.6 0.144 12.816 0.192 ;
     RECT  12.84 0.144 13.056 0.192 ;
     RECT  13.08 0.144 13.296 0.192 ;
     RECT  13.32 0.144 13.536 0.192 ;
     RECT  13.56 0.144 13.776 0.192 ;
     RECT  13.8 0.144 14.016 0.192 ;
     RECT  14.04 0.144 14.256 0.192 ;
     RECT  14.28 0.144 14.544 0.192 ;
     RECT  14.568 0.144 14.784 0.192 ;
     RECT  14.808 0.144 15.024 0.192 ;
     RECT  15.048 0.144 15.264 0.192 ;
     RECT  15.288 0.144 15.504 0.192 ;
     RECT  15.528 0.144 15.744 0.192 ;
     RECT  15.768 0.144 15.984 0.192 ;
     RECT  16.008 0.144 16.224 0.192 ;
     RECT  16.248 0.144 16.464 0.192 ;
     RECT  16.488 0.144 16.704 0.192 ;
     RECT  16.728 0.144 16.992 0.192 ;
     RECT  17.016 0.144 17.232 0.192 ;
     RECT  17.256 0.144 17.472 0.192 ;
     RECT  17.496 0.144 17.712 0.192 ;
     RECT  17.736 0.144 17.952 0.192 ;
     RECT  17.976 0.144 18.192 0.192 ;
     RECT  18.216 0.144 18.432 0.192 ;
     RECT  18.456 0.144 18.672 0.192 ;
     RECT  18.696 0.144 18.912 0.192 ;
     RECT  18.936 0.144 19.152 0.192 ;
     RECT  19.176 0.144 19.44 0.192 ;
     RECT  19.464 0.144 19.68 0.192 ;
     RECT  19.704 0.144 19.92 0.192 ;
     RECT  19.944 0.144 20.16 0.192 ;
     RECT  20.184 0.144 20.4 0.192 ;
     RECT  20.424 0.144 20.64 0.192 ;
     RECT  20.664 0.144 20.88 0.192 ;
     RECT  20.904 0.144 21.12 0.192 ;
     RECT  21.144 0.144 21.36 0.192 ;
     RECT  21.384 0.144 21.6 0.192 ;
     RECT  21.624 0.144 21.888 0.192 ;
     RECT  21.912 0.144 22.128 0.192 ;
     RECT  22.152 0.144 22.368 0.192 ;
     RECT  22.392 0.144 22.608 0.192 ;
     RECT  22.632 0.144 22.848 0.192 ;
     RECT  22.872 0.144 23.088 0.192 ;
     RECT  23.112 0.144 23.328 0.192 ;
     RECT  23.352 0.144 23.568 0.192 ;
     RECT  23.592 0.144 23.808 0.192 ;
     RECT  23.832 0.144 24.048 0.192 ;
     RECT  24.072 0.144 24.288 0.192 ;
     RECT  24.312 0.144 24.576 0.192 ;
     RECT  24.6 0.144 24.816 0.192 ;
     RECT  24.84 0.144 25.056 0.192 ;
     RECT  25.08 0.144 25.296 0.192 ;
     RECT  25.32 0.144 25.536 0.192 ;
     RECT  25.56 0.144 25.776 0.192 ;
     RECT  25.8 0.144 26.016 0.192 ;
     RECT  26.04 0.144 26.256 0.192 ;
     RECT  26.28 0.144 26.496 0.192 ;
     RECT  26.52 0.144 26.736 0.192 ;
     RECT  26.76 0.144 27.024 0.192 ;
     RECT  27.048 0.144 27.264 0.192 ;
     RECT  27.288 0.144 27.504 0.192 ;
     RECT  27.528 0.144 27.744 0.192 ;
     RECT  27.768 0.144 27.984 0.192 ;
     RECT  28.008 0.144 28.224 0.192 ;
     RECT  28.248 0.144 28.464 0.192 ;
     RECT  28.488 0.144 28.704 0.192 ;
     RECT  28.728 0.144 28.944 0.192 ;
     RECT  28.968 0.144 29.184 0.192 ;
     RECT  29.208 0.144 29.472 0.192 ;
     RECT  29.496 0.144 29.712 0.192 ;
     RECT  29.736 0.144 29.952 0.192 ;
     RECT  29.976 0.144 30.192 0.192 ;
     RECT  30.216 0.144 30.432 0.192 ;
     RECT  30.456 0.144 30.672 0.192 ;
     RECT  30.696 0.144 30.912 0.192 ;
     RECT  30.936 0.144 31.152 0.192 ;
     RECT  31.176 0.144 31.392 0.192 ;
     RECT  31.416 0.144 31.632 0.192 ;
     RECT  31.656 0.144 31.92 0.192 ;
     RECT  31.944 0.144 32.16 0.192 ;
     RECT  32.184 0.144 32.4 0.192 ;
     RECT  32.424 0.144 32.64 0.192 ;
     RECT  32.664 0.144 32.88 0.192 ;
     RECT  32.904 0.144 33.12 0.192 ;
     RECT  33.144 0.144 33.36 0.192 ;
     RECT  33.384 0.144 33.6 0.192 ;
     RECT  33.624 0.144 33.84 0.192 ;
     RECT  33.864 0.144 34.08 0.192 ;
     RECT  34.104 0.144 34.32 0.192 ;
     RECT  34.344 0.144 34.608 0.192 ;
     RECT  34.632 0.144 34.848 0.192 ;
     RECT  34.872 0.144 35.088 0.192 ;
     RECT  35.112 0.144 35.328 0.192 ;
     RECT  35.352 0.144 35.568 0.192 ;
     RECT  35.592 0.144 35.808 0.192 ;
     RECT  35.832 0.144 36.048 0.192 ;
     RECT  36.072 0.144 36.288 0.192 ;
     RECT  36.312 0.144 36.528 0.192 ;
     RECT  36.552 0.144 36.768 0.192 ;
     RECT  36.792 0.144 37.056 0.192 ;
     RECT  37.08 0.144 37.296 0.192 ;
     RECT  37.32 0.144 37.536 0.192 ;
     RECT  37.56 0.144 37.776 0.192 ;
     RECT  37.8 0.144 38.016 0.192 ;
     RECT  38.04 0.144 38.256 0.192 ;
     RECT  38.28 0.144 38.496 0.192 ;
     RECT  38.52 0.144 38.736 0.192 ;
     RECT  38.76 0.144 38.976 0.192 ;
     RECT  39 0.144 39.216 0.192 ;
     RECT  39.24 0.144 39.504 0.192 ;
     RECT  39.528 0.144 39.744 0.192 ;
     RECT  39.768 0.144 39.984 0.192 ;
     RECT  40.008 0.144 40.224 0.192 ;
     RECT  40.248 0.144 40.464 0.192 ;
     RECT  40.488 0.144 40.704 0.192 ;
     RECT  40.728 0.144 40.944 0.192 ;
     RECT  40.968 0.144 41.184 0.192 ;
     RECT  41.208 0.144 41.424 0.192 ;
     RECT  41.448 0.144 41.664 0.192 ;
     RECT  41.688 0.144 41.952 0.192 ;
     RECT  41.976 0.144 42.192 0.192 ;
     RECT  42.216 0.144 42.432 0.192 ;
     RECT  42.456 0.144 42.672 0.192 ;
     RECT  42.696 0.144 42.912 0.192 ;
     RECT  42.936 0.144 43.152 0.192 ;
     RECT  43.176 0.144 43.392 0.192 ;
     RECT  43.416 0.144 43.632 0.192 ;
     RECT  43.656 0.144 43.872 0.192 ;
     RECT  43.896 0.144 44.112 0.192 ;
     RECT  44.136 0.144 44.352 0.192 ;
     RECT  44.376 0.144 44.64 0.192 ;
     RECT  44.664 0.144 44.88 0.192 ;
     RECT  44.904 0.144 45.12 0.192 ;
     RECT  45.144 0.144 45.36 0.192 ;
     RECT  45.384 0.144 45.6 0.192 ;
     RECT  45.624 0.144 45.84 0.192 ;
     RECT  45.864 0.144 46.08 0.192 ;
     RECT  46.104 0.144 46.32 0.192 ;
     RECT  46.344 0.144 46.56 0.192 ;
     RECT  46.584 0.144 46.8 0.192 ;
     RECT  46.824 0.144 47.088 0.192 ;
     RECT  47.112 0.144 47.328 0.192 ;
     RECT  47.352 0.144 47.568 0.192 ;
     RECT  47.592 0.144 47.808 0.192 ;
     RECT  47.832 0.144 48.048 0.192 ;
     RECT  48.072 0.144 48.288 0.192 ;
     RECT  48.312 0.144 48.528 0.192 ;
     RECT  48.552 0.144 48.768 0.192 ;
     RECT  48.792 0.144 49.008 0.192 ;
     RECT  49.032 0.144 49.248 0.192 ;
     RECT  49.272 0.144 49.536 0.192 ;
     RECT  49.56 0.144 49.776 0.192 ;
     RECT  49.8 0.144 50.016 0.192 ;
     RECT  50.04 0.144 50.256 0.192 ;
     RECT  50.28 0.144 50.496 0.192 ;
     RECT  50.52 0.144 50.736 0.192 ;
     RECT  50.76 0.144 50.976 0.192 ;
     RECT  51 0.144 51.216 0.192 ;
     RECT  51.24 0.144 51.456 0.192 ;
     RECT  51.48 0.144 51.696 0.192 ;
     RECT  51.72 0.144 51.984 0.192 ;
     RECT  52.008 0.144 52.224 0.192 ;
     RECT  52.248 0.144 52.464 0.192 ;
     RECT  52.488 0.144 52.704 0.192 ;
     RECT  52.728 0.144 52.944 0.192 ;
     RECT  52.968 0.144 53.184 0.192 ;
     RECT  53.208 0.144 53.424 0.192 ;
     RECT  53.448 0.144 53.664 0.192 ;
     RECT  53.688 0.144 53.904 0.192 ;
     RECT  53.928 0.144 54.144 0.192 ;
     RECT  54.168 0.144 54.384 0.192 ;
     RECT  54.408 0.144 54.672 0.192 ;
     RECT  54.696 0.144 54.912 0.192 ;
     RECT  54.936 0.144 55.152 0.192 ;
     RECT  55.176 0.144 55.392 0.192 ;
     RECT  55.416 0.144 55.632 0.192 ;
     RECT  55.656 0.144 55.872 0.192 ;
     RECT  55.896 0.144 56.112 0.192 ;
     RECT  56.136 0.144 56.352 0.192 ;
     RECT  56.376 0.144 56.592 0.192 ;
     RECT  56.616 0.144 56.832 0.192 ;
     RECT  56.856 0.144 57.12 0.192 ;
     RECT  57.144 0.144 57.36 0.192 ;
     RECT  57.384 0.144 57.6 0.192 ;
     RECT  57.624 0.144 57.84 0.192 ;
     RECT  57.864 0.144 58.08 0.192 ;
     RECT  58.104 0.144 58.32 0.192 ;
     RECT  58.344 0.144 58.56 0.192 ;
     RECT  58.584 0.144 58.8 0.192 ;
     RECT  58.824 0.144 59.04 0.192 ;
     RECT  59.064 0.144 59.28 0.192 ;
     RECT  59.304 0.144 59.568 0.192 ;
     RECT  59.592 0.144 59.808 0.192 ;
     RECT  59.832 0.144 60.048 0.192 ;
     RECT  60.072 0.144 60.288 0.192 ;
     RECT  60.312 0.144 60.528 0.192 ;
     RECT  60.552 0.144 60.768 0.192 ;
     RECT  60.792 0.144 61.008 0.192 ;
     RECT  61.032 0.144 61.248 0.192 ;
     RECT  61.272 0.144 61.488 0.192 ;
     RECT  61.512 0.144 61.728 0.192 ;
     RECT  61.752 0.144 62.016 0.192 ;
     RECT  62.04 0.144 62.256 0.192 ;
     RECT  62.28 0.144 62.496 0.192 ;
     RECT  62.52 0.144 62.736 0.192 ;
     RECT  62.76 0.144 62.976 0.192 ;
     RECT  63 0.144 63.216 0.192 ;
     RECT  63.24 0.144 63.456 0.192 ;
     RECT  63.48 0.144 63.696 0.192 ;
     RECT  63.72 0.144 63.936 0.192 ;
     RECT  63.96 0.144 64.176 0.192 ;
     RECT  64.2 0.144 64.416 0.192 ;
     RECT  64.44 0.144 64.704 0.192 ;
     RECT  64.728 0.144 64.944 0.192 ;
     RECT  64.968 0.144 65.184 0.192 ;
     RECT  65.208 0.144 65.424 0.192 ;
     RECT  65.448 0.144 65.664 0.192 ;
     RECT  65.688 0.144 65.904 0.192 ;
     RECT  65.928 0.144 66.144 0.192 ;
     RECT  66.168 0.144 66.384 0.192 ;
     RECT  66.408 0.144 66.624 0.192 ;
     RECT  66.648 0.144 66.864 0.192 ;
     RECT  4.512 0.192 66.888 1.763 ;
     RECT  5.1 1.763 46.104 1.811 ;
     RECT  47.28 1.763 59.412 1.811 ;
     RECT  61.248 1.763 66.888 1.811 ;
     RECT  5.1 1.811 16.488 1.859 ;
     RECT  52.944 1.811 59.412 1.859 ;
     RECT  2.4 2.137 2.52 2.151 ;
     RECT  67.2 2.137 67.32 2.151 ;
     RECT  17.616 1.811 46.104 2.291 ;
     RECT  9.888 1.859 11.352 2.339 ;
     RECT  26.4 2.291 46.104 2.725 ;
     RECT  26.4 2.725 46.152 2.773 ;
     RECT  52.944 1.859 57.48 2.821 ;
     RECT  61.584 1.811 66.168 2.867 ;
     RECT  5.1 1.859 8.904 2.915 ;
     RECT  12.816 1.859 16.488 2.915 ;
     RECT  26.4 2.773 46.248 2.915 ;
     RECT  52.944 2.821 57.576 2.915 ;
     RECT  58.56 1.859 59.412 2.915 ;
     RECT  61.584 2.867 65.688 2.915 ;
     RECT  6.96 2.915 8.112 2.963 ;
     RECT  17.616 2.291 25.08 2.963 ;
     RECT  50.736 1.811 51.312 3.013 ;
     RECT  58.8 2.915 59.412 3.059 ;
     RECT  10.368 2.339 11.352 3.155 ;
     RECT  26.4 2.915 43.32 3.299 ;
     RECT  59.1 3.059 59.412 3.397 ;
     RECT  10.368 3.155 10.812 3.443 ;
     RECT  14.784 2.915 16.488 3.443 ;
     RECT  26.4 3.299 30.216 3.539 ;
     RECT  17.616 2.963 25.032 3.587 ;
     RECT  31.296 3.299 43.32 3.877 ;
     RECT  31.296 3.877 43.512 3.925 ;
     RECT  44.592 2.915 46.248 3.925 ;
     RECT  53.7 2.915 57.576 3.925 ;
     RECT  18.144 3.587 25.032 4.019 ;
     RECT  47.28 1.811 48.984 4.163 ;
     RECT  7.8 2.963 8.112 4.165 ;
     RECT  53.7 3.925 57.912 4.213 ;
     RECT  61.584 2.915 62.232 4.261 ;
     RECT  63.216 2.915 65.688 4.261 ;
     RECT  20.928 4.019 25.032 4.501 ;
     RECT  26.4 3.539 30.12 4.501 ;
     RECT  59.1 3.397 60.36 4.549 ;
     RECT  61.584 4.261 65.688 4.549 ;
     RECT  7.8 4.165 8.424 4.595 ;
     RECT  12.816 2.915 13.512 4.595 ;
     RECT  14.784 3.443 16.344 4.595 ;
     RECT  18.144 4.019 19.944 4.595 ;
     RECT  20.928 4.501 30.12 4.595 ;
     RECT  31.296 3.925 46.248 4.595 ;
     RECT  13.104 4.595 13.512 4.645 ;
     RECT  41.568 4.595 46.248 4.645 ;
     RECT  47.28 4.163 48.612 4.645 ;
     RECT  53.184 4.213 57.912 4.691 ;
     RECT  18.192 4.595 19.944 4.787 ;
     RECT  31.296 4.595 40.512 4.837 ;
     RECT  18.192 4.787 19.608 4.883 ;
     RECT  55.248 4.691 57.912 4.931 ;
     RECT  10.5 3.443 10.812 5.029 ;
     RECT  21.024 4.595 30.12 5.075 ;
     RECT  5.1 2.915 5.412 5.077 ;
     RECT  10.5 5.029 11.448 5.077 ;
     RECT  15.696 4.595 16.344 5.171 ;
     RECT  31.152 4.837 40.512 5.171 ;
     RECT  41.568 4.645 48.612 5.171 ;
     RECT  18.384 4.883 19.608 5.219 ;
     RECT  21.024 5.075 24.552 5.219 ;
     RECT  26.448 5.075 30.12 5.219 ;
     RECT  53.184 4.691 54.012 5.219 ;
     RECT  31.152 5.171 35.688 5.267 ;
     RECT  50.016 3.013 51.312 5.461 ;
     RECT  42.096 5.171 48.612 5.507 ;
     RECT  26.544 5.219 30.12 5.603 ;
     RECT  10.5 5.077 11.64 5.605 ;
     RECT  15.9 5.171 16.344 5.605 ;
     RECT  45.6 5.507 48.612 5.651 ;
     RECT  55.248 4.931 55.272 5.701 ;
     RECT  42.096 5.507 44.616 5.747 ;
     RECT  50.016 5.461 51.912 5.747 ;
     RECT  59.1 4.549 65.688 5.747 ;
     RECT  13.104 4.645 14.568 5.795 ;
     RECT  18.384 5.219 18.912 5.795 ;
     RECT  26.7 5.603 30.12 5.795 ;
     RECT  53.376 5.219 54.012 5.797 ;
     RECT  56.256 4.931 57.912 5.843 ;
     RECT  5.1 5.077 6.264 5.987 ;
     RECT  37.152 5.171 40.512 5.987 ;
     RECT  59.1 5.747 63.096 6.035 ;
     RECT  55.104 5.701 55.272 6.133 ;
     RECT  56.256 5.843 57.528 6.133 ;
     RECT  13.104 5.795 13.512 6.179 ;
     RECT  7.8 4.595 8.232 6.229 ;
     RECT  14.544 5.795 14.568 6.229 ;
     RECT  14.544 6.229 14.712 6.275 ;
     RECT  21.3 5.219 24.552 6.323 ;
     RECT  33.6 5.267 35.688 6.323 ;
     RECT  50.88 5.747 51.912 6.323 ;
     RECT  55.104 6.133 57.528 6.371 ;
     RECT  60.768 6.035 63.096 6.419 ;
     RECT  42.096 5.747 43.512 6.467 ;
     RECT  45.6 5.651 46.248 6.467 ;
     RECT  47.28 5.651 48.612 6.467 ;
     RECT  61.8 6.419 63.096 6.515 ;
     RECT  31.152 5.267 32.412 6.563 ;
     RECT  51 6.323 51.912 6.563 ;
     RECT  53.376 5.797 54.12 6.563 ;
     RECT  55.104 6.371 57.432 6.563 ;
     RECT  37.152 5.987 37.812 6.611 ;
     RECT  47.28 6.467 47.304 6.611 ;
     RECT  26.7 5.795 29.712 6.803 ;
     RECT  60.768 6.419 60.792 6.803 ;
     RECT  7.8 6.229 9.096 6.851 ;
     RECT  15.9 5.605 16.776 6.851 ;
     RECT  21.3 6.323 23.016 6.851 ;
     RECT  53.376 6.563 54.012 6.851 ;
     RECT  14.688 6.275 14.712 6.899 ;
     RECT  21.3 6.851 22.776 6.899 ;
     RECT  31.92 6.563 32.412 6.899 ;
     RECT  42.384 6.467 43.512 6.899 ;
     RECT  55.296 6.563 57.432 6.899 ;
     RECT  39.024 5.987 40.512 6.947 ;
     RECT  10.5 5.605 11.736 7.043 ;
     RECT  55.296 6.899 56.712 7.139 ;
     RECT  42.9 6.899 43.512 7.187 ;
     RECT  55.296 7.139 55.32 7.283 ;
     RECT  10.5 7.043 11.448 7.475 ;
     RECT  21.3 6.899 22.152 7.475 ;
     RECT  24 6.323 24.552 7.475 ;
     RECT  39.84 6.947 40.512 7.475 ;
     RECT  45.6 6.467 46.152 7.475 ;
     RECT  26.7 6.803 27.816 9.731 ;
     RECT  33.984 6.323 35.688 9.731 ;
     RECT  34.8 9.731 35.688 10.307 ;
     RECT  45.6 7.475 45.912 10.645 ;
     RECT  45.6 10.645 46.104 11.267 ;
     RECT  0.24 6.037 0.264 18.419 ;
     RECT  26.7 9.731 27.012 29.605 ;
     RECT  56.4 7.139 56.712 29.605 ;
     RECT  59.1 6.035 59.412 29.605 ;
     RECT  51 6.563 51.312 29.941 ;
     RECT  26.7 29.605 27.768 30.085 ;
     RECT  26.592 30.085 27.768 30.133 ;
     RECT  37.5 6.611 37.812 30.133 ;
     RECT  45.6 11.267 45.912 30.133 ;
     RECT  13.2 6.179 13.512 30.181 ;
     RECT  47.088 29.941 47.112 30.181 ;
     RECT  48.3 6.467 48.612 30.181 ;
     RECT  56.304 29.605 56.712 30.181 ;
     RECT  58.8 29.605 59.412 30.181 ;
     RECT  61.8 6.515 62.112 30.181 ;
     RECT  64.5 5.747 64.812 30.181 ;
     RECT  67.2 2.151 67.512 30.181 ;
     RECT  21.3 7.475 21.612 30.421 ;
     RECT  40.2 7.475 40.512 30.421 ;
     RECT  5.1 5.987 5.412 30.469 ;
     RECT  10.5 7.475 10.812 30.469 ;
     RECT  13.2 30.181 13.608 30.469 ;
     RECT  15.9 6.851 16.212 30.469 ;
     RECT  18.6 5.795 18.912 30.469 ;
     RECT  32.1 6.899 32.412 30.469 ;
     RECT  34.8 10.307 35.112 30.469 ;
     RECT  42.9 7.187 43.212 30.469 ;
     RECT  44.88 30.133 45.912 30.469 ;
     RECT  56.304 30.181 57.144 30.469 ;
     RECT  58.8 30.181 59.544 30.469 ;
     RECT  61.248 30.181 62.28 30.469 ;
     RECT  63.456 30.181 64.812 30.469 ;
     RECT  66.384 30.181 67.512 30.469 ;
     RECT  13.2 30.469 13.8 30.517 ;
     RECT  13.2 30.517 14.28 30.565 ;
     RECT  4.992 30.469 5.412 30.661 ;
     RECT  7.8 6.851 8.112 30.661 ;
     RECT  15.9 30.469 19.704 30.661 ;
     RECT  24 7.475 24.312 30.661 ;
     RECT  32.1 30.469 35.112 30.661 ;
     RECT  52.704 30.181 52.728 30.661 ;
     RECT  53.7 6.851 54.012 30.661 ;
     RECT  10.5 30.469 11.592 30.709 ;
     RECT  12.576 30.565 14.28 30.709 ;
     RECT  23.808 30.661 24.408 30.709 ;
     RECT  29.4 6.803 29.712 30.709 ;
     RECT  31.968 30.661 35.112 30.709 ;
     RECT  37.392 30.133 37.812 30.709 ;
     RECT  41.952 30.469 43.212 30.709 ;
     RECT  44.352 30.469 45.912 30.709 ;
     RECT  55.632 30.469 59.544 30.709 ;
     RECT  51 29.941 51.72 30.757 ;
     RECT  52.704 30.661 54.012 30.757 ;
     RECT  55.632 30.709 59.832 30.757 ;
     RECT  4.752 30.661 5.412 30.805 ;
     RECT  7.2 30.661 8.112 30.805 ;
     RECT  9.12 30.469 9.144 30.805 ;
     RECT  23.808 30.709 24.504 30.805 ;
     RECT  26.016 30.133 27.768 30.805 ;
     RECT  39.984 30.421 40.512 30.805 ;
     RECT  41.952 30.709 45.912 30.805 ;
     RECT  47.088 30.181 48.612 30.805 ;
     RECT  52.704 30.757 59.832 30.805 ;
     RECT  61.008 30.469 62.28 30.805 ;
     RECT  23.088 30.805 28.008 31.189 ;
     RECT  29.4 30.709 35.112 31.189 ;
     RECT  15.264 30.661 19.704 31.285 ;
     RECT  20.88 30.421 21.612 31.285 ;
     RECT  23.088 31.189 35.112 31.285 ;
     RECT  36.288 31.237 36.312 31.285 ;
     RECT  15.264 31.285 21.612 33.637 ;
     RECT  41.952 30.805 46.008 34.117 ;
     RECT  47.088 30.805 49.032 34.117 ;
     RECT  15.264 33.637 21.912 34.165 ;
     RECT  23.088 31.285 36.312 34.165 ;
     RECT  37.392 30.709 38.52 34.165 ;
     RECT  39.984 30.805 40.968 34.165 ;
     RECT  41.952 34.117 49.032 34.165 ;
     RECT  50.496 30.757 51.72 34.165 ;
     RECT  4.752 30.805 9.144 34.213 ;
     RECT  10.5 30.709 14.28 34.213 ;
     RECT  15.264 34.165 36.312 34.213 ;
     RECT  37.296 34.165 38.52 34.213 ;
     RECT  39.504 34.165 40.968 34.213 ;
     RECT  2.4 2.151 2.712 34.569 ;
     RECT  63.456 30.469 67.512 34.569 ;
     RECT  2.4 34.569 2.52 34.583 ;
     RECT  63.456 34.569 67.32 34.583 ;
     RECT  37.296 34.213 40.968 34.645 ;
     RECT  41.952 34.165 51.72 34.645 ;
     RECT  4.752 34.213 36.312 34.693 ;
     RECT  37.296 34.645 51.72 34.693 ;
     RECT  4.752 34.693 51.72 34.741 ;
     RECT  52.704 30.805 62.28 34.741 ;
     RECT  4.512 34.741 62.28 35.893 ;
     RECT  63.456 34.583 66.888 35.893 ;
     RECT  4.512 35.893 66.888 36.528 ;
     RECT  4.536 36.528 4.752 36.56 ;
     RECT  4.776 36.528 4.992 36.56 ;
     RECT  5.016 36.528 5.232 36.56 ;
     RECT  5.256 36.528 5.472 36.56 ;
     RECT  5.496 36.528 5.712 36.56 ;
     RECT  5.736 36.528 5.952 36.56 ;
     RECT  5.976 36.528 6.192 36.56 ;
     RECT  6.216 36.528 6.432 36.56 ;
     RECT  6.456 36.528 6.672 36.56 ;
     RECT  6.696 36.528 6.96 36.56 ;
     RECT  6.984 36.528 7.2 36.56 ;
     RECT  7.224 36.528 7.44 36.56 ;
     RECT  7.464 36.528 7.68 36.56 ;
     RECT  7.704 36.528 7.92 36.56 ;
     RECT  7.944 36.528 8.16 36.56 ;
     RECT  8.184 36.528 8.4 36.56 ;
     RECT  8.424 36.528 8.64 36.56 ;
     RECT  8.664 36.528 8.88 36.56 ;
     RECT  8.904 36.528 9.12 36.56 ;
     RECT  9.144 36.528 9.408 36.56 ;
     RECT  9.432 36.528 9.648 36.56 ;
     RECT  9.672 36.528 9.888 36.56 ;
     RECT  9.912 36.528 10.128 36.56 ;
     RECT  10.152 36.528 10.368 36.56 ;
     RECT  10.392 36.528 10.608 36.56 ;
     RECT  10.632 36.528 10.848 36.56 ;
     RECT  10.872 36.528 11.088 36.56 ;
     RECT  11.112 36.528 11.328 36.56 ;
     RECT  11.352 36.528 11.568 36.56 ;
     RECT  11.592 36.528 11.856 36.56 ;
     RECT  11.88 36.528 12.096 36.56 ;
     RECT  12.12 36.528 12.336 36.56 ;
     RECT  12.36 36.528 12.576 36.56 ;
     RECT  12.6 36.528 12.816 36.56 ;
     RECT  12.84 36.528 13.056 36.56 ;
     RECT  13.08 36.528 13.296 36.56 ;
     RECT  13.32 36.528 13.536 36.56 ;
     RECT  13.56 36.528 13.776 36.56 ;
     RECT  13.8 36.528 14.016 36.56 ;
     RECT  14.04 36.528 14.256 36.56 ;
     RECT  14.28 36.528 14.544 36.56 ;
     RECT  14.568 36.528 14.784 36.56 ;
     RECT  14.808 36.528 15.024 36.56 ;
     RECT  15.048 36.528 15.264 36.56 ;
     RECT  15.288 36.528 15.504 36.56 ;
     RECT  15.528 36.528 15.744 36.56 ;
     RECT  15.768 36.528 15.984 36.56 ;
     RECT  16.008 36.528 16.224 36.56 ;
     RECT  16.248 36.528 16.464 36.56 ;
     RECT  16.488 36.528 16.704 36.56 ;
     RECT  16.728 36.528 16.992 36.56 ;
     RECT  17.016 36.528 17.232 36.56 ;
     RECT  17.256 36.528 17.472 36.56 ;
     RECT  17.496 36.528 17.712 36.56 ;
     RECT  17.736 36.528 17.952 36.56 ;
     RECT  17.976 36.528 18.192 36.56 ;
     RECT  18.216 36.528 18.432 36.56 ;
     RECT  18.456 36.528 18.672 36.56 ;
     RECT  18.696 36.528 18.912 36.56 ;
     RECT  18.936 36.528 19.152 36.56 ;
     RECT  19.176 36.528 19.44 36.56 ;
     RECT  19.464 36.528 19.68 36.56 ;
     RECT  19.704 36.528 19.92 36.56 ;
     RECT  19.944 36.528 20.16 36.56 ;
     RECT  20.184 36.528 20.4 36.56 ;
     RECT  20.424 36.528 20.64 36.56 ;
     RECT  20.664 36.528 20.88 36.56 ;
     RECT  20.904 36.528 21.12 36.56 ;
     RECT  21.144 36.528 21.36 36.56 ;
     RECT  21.384 36.528 21.6 36.56 ;
     RECT  21.624 36.528 21.888 36.56 ;
     RECT  21.912 36.528 22.128 36.56 ;
     RECT  22.152 36.528 22.368 36.56 ;
     RECT  22.392 36.528 22.608 36.56 ;
     RECT  22.632 36.528 22.848 36.56 ;
     RECT  22.872 36.528 23.088 36.56 ;
     RECT  23.112 36.528 23.328 36.56 ;
     RECT  23.352 36.528 23.568 36.56 ;
     RECT  23.592 36.528 23.808 36.56 ;
     RECT  23.832 36.528 24.048 36.56 ;
     RECT  24.072 36.528 24.288 36.56 ;
     RECT  24.312 36.528 24.576 36.56 ;
     RECT  24.6 36.528 24.816 36.56 ;
     RECT  24.84 36.528 25.056 36.56 ;
     RECT  25.08 36.528 25.296 36.56 ;
     RECT  25.32 36.528 25.536 36.56 ;
     RECT  25.56 36.528 25.776 36.56 ;
     RECT  25.8 36.528 26.016 36.56 ;
     RECT  26.04 36.528 26.256 36.56 ;
     RECT  26.28 36.528 26.496 36.56 ;
     RECT  26.52 36.528 26.736 36.56 ;
     RECT  26.76 36.528 27.024 36.56 ;
     RECT  27.048 36.528 27.264 36.56 ;
     RECT  27.288 36.528 27.504 36.56 ;
     RECT  27.528 36.528 27.744 36.56 ;
     RECT  27.768 36.528 27.984 36.56 ;
     RECT  28.008 36.528 28.224 36.56 ;
     RECT  28.248 36.528 28.464 36.56 ;
     RECT  28.488 36.528 28.704 36.56 ;
     RECT  28.728 36.528 28.944 36.56 ;
     RECT  28.968 36.528 29.184 36.56 ;
     RECT  29.208 36.528 29.472 36.56 ;
     RECT  29.496 36.528 29.712 36.56 ;
     RECT  29.736 36.528 29.952 36.56 ;
     RECT  29.976 36.528 30.192 36.56 ;
     RECT  30.216 36.528 30.432 36.56 ;
     RECT  30.456 36.528 30.672 36.56 ;
     RECT  30.696 36.528 30.912 36.56 ;
     RECT  30.936 36.528 31.152 36.56 ;
     RECT  31.176 36.528 31.392 36.56 ;
     RECT  31.416 36.528 31.632 36.56 ;
     RECT  31.656 36.528 31.92 36.56 ;
     RECT  31.944 36.528 32.16 36.56 ;
     RECT  32.184 36.528 32.4 36.56 ;
     RECT  32.424 36.528 32.64 36.56 ;
     RECT  32.664 36.528 32.88 36.56 ;
     RECT  32.904 36.528 33.12 36.56 ;
     RECT  33.144 36.528 33.36 36.56 ;
     RECT  33.384 36.528 33.6 36.56 ;
     RECT  33.624 36.528 33.84 36.56 ;
     RECT  33.864 36.528 34.08 36.56 ;
     RECT  34.104 36.528 34.32 36.56 ;
     RECT  34.344 36.528 34.608 36.56 ;
     RECT  34.632 36.528 34.848 36.56 ;
     RECT  34.872 36.528 35.088 36.56 ;
     RECT  35.112 36.528 35.328 36.56 ;
     RECT  35.352 36.528 35.568 36.56 ;
     RECT  35.592 36.528 35.808 36.56 ;
     RECT  35.832 36.528 36.048 36.56 ;
     RECT  36.072 36.528 36.288 36.56 ;
     RECT  36.312 36.528 36.528 36.56 ;
     RECT  36.552 36.528 36.768 36.56 ;
     RECT  36.792 36.528 37.056 36.56 ;
     RECT  37.08 36.528 37.296 36.56 ;
     RECT  37.32 36.528 37.536 36.56 ;
     RECT  37.56 36.528 37.776 36.56 ;
     RECT  37.8 36.528 38.016 36.56 ;
     RECT  38.04 36.528 38.256 36.56 ;
     RECT  38.28 36.528 38.496 36.56 ;
     RECT  38.52 36.528 38.736 36.56 ;
     RECT  38.76 36.528 38.976 36.56 ;
     RECT  39 36.528 39.216 36.56 ;
     RECT  39.24 36.528 39.504 36.56 ;
     RECT  39.528 36.528 39.744 36.56 ;
     RECT  39.768 36.528 39.984 36.56 ;
     RECT  40.008 36.528 40.224 36.56 ;
     RECT  40.248 36.528 40.464 36.56 ;
     RECT  40.488 36.528 40.704 36.56 ;
     RECT  40.728 36.528 40.944 36.56 ;
     RECT  40.968 36.528 41.184 36.56 ;
     RECT  41.208 36.528 41.424 36.56 ;
     RECT  41.448 36.528 41.664 36.56 ;
     RECT  41.688 36.528 41.952 36.56 ;
     RECT  41.976 36.528 42.192 36.56 ;
     RECT  42.216 36.528 42.432 36.56 ;
     RECT  42.456 36.528 42.672 36.56 ;
     RECT  42.696 36.528 42.912 36.56 ;
     RECT  42.936 36.528 43.152 36.56 ;
     RECT  43.176 36.528 43.392 36.56 ;
     RECT  43.416 36.528 43.632 36.56 ;
     RECT  43.656 36.528 43.872 36.56 ;
     RECT  43.896 36.528 44.112 36.56 ;
     RECT  44.136 36.528 44.352 36.56 ;
     RECT  44.376 36.528 44.64 36.56 ;
     RECT  44.664 36.528 44.88 36.56 ;
     RECT  44.904 36.528 45.12 36.56 ;
     RECT  45.144 36.528 45.36 36.56 ;
     RECT  45.384 36.528 45.6 36.56 ;
     RECT  45.624 36.528 45.84 36.56 ;
     RECT  45.864 36.528 46.08 36.56 ;
     RECT  46.104 36.528 46.32 36.56 ;
     RECT  46.344 36.528 46.56 36.56 ;
     RECT  46.584 36.528 46.8 36.56 ;
     RECT  46.824 36.528 47.088 36.56 ;
     RECT  47.112 36.528 47.328 36.56 ;
     RECT  47.352 36.528 47.568 36.56 ;
     RECT  47.592 36.528 47.808 36.56 ;
     RECT  47.832 36.528 48.048 36.56 ;
     RECT  48.072 36.528 48.288 36.56 ;
     RECT  48.312 36.528 48.528 36.56 ;
     RECT  48.552 36.528 48.768 36.56 ;
     RECT  48.792 36.528 49.008 36.56 ;
     RECT  49.032 36.528 49.248 36.56 ;
     RECT  49.272 36.528 49.536 36.56 ;
     RECT  49.56 36.528 49.776 36.56 ;
     RECT  49.8 36.528 50.016 36.56 ;
     RECT  50.04 36.528 50.256 36.56 ;
     RECT  50.28 36.528 50.496 36.56 ;
     RECT  50.52 36.528 50.736 36.56 ;
     RECT  50.76 36.528 50.976 36.56 ;
     RECT  51 36.528 51.216 36.56 ;
     RECT  51.24 36.528 51.456 36.56 ;
     RECT  51.48 36.528 51.696 36.56 ;
     RECT  51.72 36.528 51.984 36.56 ;
     RECT  52.008 36.528 52.224 36.56 ;
     RECT  52.248 36.528 52.464 36.56 ;
     RECT  52.488 36.528 52.704 36.56 ;
     RECT  52.728 36.528 52.944 36.56 ;
     RECT  52.968 36.528 53.184 36.56 ;
     RECT  53.208 36.528 53.424 36.56 ;
     RECT  53.448 36.528 53.664 36.56 ;
     RECT  53.688 36.528 53.904 36.56 ;
     RECT  53.928 36.528 54.144 36.56 ;
     RECT  54.168 36.528 54.384 36.56 ;
     RECT  54.408 36.528 54.672 36.56 ;
     RECT  54.696 36.528 54.912 36.56 ;
     RECT  54.936 36.528 55.152 36.56 ;
     RECT  55.176 36.528 55.392 36.56 ;
     RECT  55.416 36.528 55.632 36.56 ;
     RECT  55.656 36.528 55.872 36.56 ;
     RECT  55.896 36.528 56.112 36.56 ;
     RECT  56.136 36.528 56.352 36.56 ;
     RECT  56.376 36.528 56.592 36.56 ;
     RECT  56.616 36.528 56.832 36.56 ;
     RECT  56.856 36.528 57.12 36.56 ;
     RECT  57.144 36.528 57.36 36.56 ;
     RECT  57.384 36.528 57.6 36.56 ;
     RECT  57.624 36.528 57.84 36.56 ;
     RECT  57.864 36.528 58.08 36.56 ;
     RECT  58.104 36.528 58.32 36.56 ;
     RECT  58.344 36.528 58.56 36.56 ;
     RECT  58.584 36.528 58.8 36.56 ;
     RECT  58.824 36.528 59.04 36.56 ;
     RECT  59.064 36.528 59.28 36.56 ;
     RECT  59.304 36.528 59.568 36.56 ;
     RECT  59.592 36.528 59.808 36.56 ;
     RECT  59.832 36.528 60.048 36.56 ;
     RECT  60.072 36.528 60.288 36.56 ;
     RECT  60.312 36.528 60.528 36.56 ;
     RECT  60.552 36.528 60.768 36.56 ;
     RECT  60.792 36.528 61.008 36.56 ;
     RECT  61.032 36.528 61.248 36.56 ;
     RECT  61.272 36.528 61.488 36.56 ;
     RECT  61.512 36.528 61.728 36.56 ;
     RECT  61.752 36.528 62.016 36.56 ;
     RECT  62.04 36.528 62.256 36.56 ;
     RECT  62.28 36.528 62.496 36.56 ;
     RECT  62.52 36.528 62.736 36.56 ;
     RECT  62.76 36.528 62.976 36.56 ;
     RECT  63 36.528 63.216 36.56 ;
     RECT  63.24 36.528 63.456 36.56 ;
     RECT  63.48 36.528 63.696 36.56 ;
     RECT  63.72 36.528 63.936 36.56 ;
     RECT  63.96 36.528 64.176 36.56 ;
     RECT  64.2 36.528 64.416 36.56 ;
     RECT  64.44 36.528 64.704 36.56 ;
     RECT  64.728 36.528 64.944 36.56 ;
     RECT  64.968 36.528 65.184 36.56 ;
     RECT  65.208 36.528 65.424 36.56 ;
     RECT  65.448 36.528 65.664 36.56 ;
     RECT  65.688 36.528 65.904 36.56 ;
     RECT  65.928 36.528 66.144 36.56 ;
     RECT  66.168 36.528 66.384 36.56 ;
     RECT  66.408 36.528 66.624 36.56 ;
     RECT  66.648 36.528 66.864 36.56 ;
     RECT  43.8 0.133 43.824 0.144 ;
     RECT  43.944 0.133 44.064 0.144 ;
     RECT  44.184 0.133 44.304 0.144 ;
     RECT  44.424 0.133 44.592 0.144 ;
     RECT  44.712 0.133 44.784 0.144 ;
     RECT  46.104 1.763 47.28 2.725 ;
     RECT  16.488 1.811 17.616 3.443 ;
     RECT  48.984 1.811 50.736 3.013 ;
     RECT  66.168 1.811 66.888 2.137 ;
     RECT  8.904 1.859 9.888 2.339 ;
     RECT  11.352 1.859 12.816 3.155 ;
     RECT  57.48 1.859 58.56 2.821 ;
     RECT  66.168 2.137 67.2 2.867 ;
     RECT  25.08 2.291 26.4 2.963 ;
     RECT  8.904 2.339 10.368 2.915 ;
     RECT  46.152 2.725 47.28 2.773 ;
     RECT  46.248 2.773 47.28 4.645 ;
     RECT  57.576 2.821 58.56 2.915 ;
     RECT  65.688 2.867 67.2 5.747 ;
     RECT  8.112 2.915 8.424 4.165 ;
     RECT  13.512 2.915 14.784 4.595 ;
     RECT  43.32 2.915 44.592 3.877 ;
     RECT  53.184 2.915 53.7 4.213 ;
     RECT  57.576 2.915 58.8 3.059 ;
     RECT  62.232 2.915 63.216 4.261 ;
     RECT  25.032 2.963 26.4 4.501 ;
     RECT  48.984 3.013 50.016 4.163 ;
     RECT  57.576 3.059 59.1 3.925 ;
     RECT  30.216 3.299 31.296 3.539 ;
     RECT  60.36 3.397 61.584 4.549 ;
     RECT  16.344 3.443 17.616 3.587 ;
     RECT  30.12 3.539 31.296 4.837 ;
     RECT  43.512 3.877 44.592 3.925 ;
     RECT  57.912 3.925 59.1 5.843 ;
     RECT  19.944 4.019 20.928 4.595 ;
     RECT  48.612 4.163 50.016 5.747 ;
     RECT  12.816 4.595 13.104 5.029 ;
     RECT  13.512 4.595 15.696 4.645 ;
     RECT  19.944 4.595 21.024 4.787 ;
     RECT  40.512 4.595 41.568 5.171 ;
     RECT  14.568 4.645 15.696 5.171 ;
     RECT  54.012 4.691 55.248 5.701 ;
     RECT  19.608 4.787 21.024 5.219 ;
     RECT  30.12 4.837 31.152 5.795 ;
     RECT  55.272 4.931 56.256 6.133 ;
     RECT  11.448 5.029 13.104 5.077 ;
     RECT  11.64 5.077 13.104 5.605 ;
     RECT  14.568 5.171 15.9 6.229 ;
     RECT  35.688 5.171 37.152 6.611 ;
     RECT  53.184 5.219 53.376 5.461 ;
     RECT  32.412 5.267 33.6 6.323 ;
     RECT  51.912 5.461 53.376 6.563 ;
     RECT  44.616 5.507 45.6 5.747 ;
     RECT  11.736 5.605 13.104 6.179 ;
     RECT  46.248 5.651 47.28 6.467 ;
     RECT  54.012 5.701 55.104 5.797 ;
     RECT  63.096 5.747 64.5 6.515 ;
     RECT  13.512 5.795 14.544 6.275 ;
     RECT  29.712 5.795 31.152 6.563 ;
     RECT  54.12 5.797 55.104 6.563 ;
     RECT  37.812 5.987 39.024 6.947 ;
     RECT  59.412 6.035 60.768 6.803 ;
     RECT  11.736 6.179 13.2 7.043 ;
     RECT  9.096 6.229 10.5 6.851 ;
     RECT  14.712 6.229 15.9 6.899 ;
     RECT  13.512 6.275 14.688 6.899 ;
     RECT  23.016 6.323 24 6.851 ;
     RECT  60.792 6.419 61.8 6.803 ;
     RECT  46.152 6.467 47.28 6.611 ;
     RECT  47.304 6.467 48.3 6.611 ;
     RECT  54.012 6.563 55.296 7.283 ;
     RECT  22.776 6.851 24 6.899 ;
     RECT  55.32 7.139 56.4 7.283 ;
     RECT  45.912 29.941 47.088 30.805 ;
     RECT  47.112 29.941 48.3 30.181 ;
     RECT  51.72 30.181 52.704 34.741 ;
     RECT  52.728 30.181 53.7 30.661 ;
     RECT  62.28 30.181 63.456 35.893 ;
     RECT  8.112 30.469 9.12 30.805 ;
     RECT  9.144 30.469 10.5 34.213 ;
     RECT  19.704 30.469 20.88 31.285 ;
     RECT  40.512 30.469 41.952 30.805 ;
     RECT  43.212 30.469 44.352 30.709 ;
     RECT  59.544 30.469 61.008 30.709 ;
     RECT  11.592 30.565 12.576 30.709 ;
     RECT  14.28 30.661 15.264 34.213 ;
     RECT  24.504 30.709 26.016 30.805 ;
     RECT  38.52 30.709 39.984 34.165 ;
     RECT  59.832 30.709 61.008 30.805 ;
     RECT  21.612 30.805 23.088 33.637 ;
     RECT  28.008 30.805 29.4 31.189 ;
     RECT  40.968 30.805 41.952 34.645 ;
     RECT  46.008 30.805 47.088 34.117 ;
     RECT  49.032 30.805 50.496 34.165 ;
     RECT  35.112 31.237 36.288 31.285 ;
     RECT  36.312 31.237 37.392 34.165 ;
     RECT  21.912 33.637 23.088 34.165 ;
     RECT  36.312 34.165 37.296 34.693 ;
     RECT  38.52 34.165 39.504 34.213 ;
  END
END dsfd_hstnv_512
END LIBRARY
